VERSION 5.7 ;
BUSBITCHARS "[]" ;
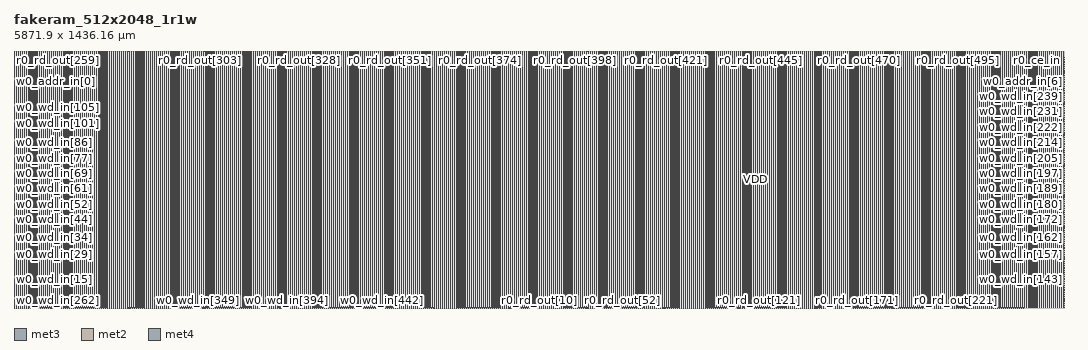
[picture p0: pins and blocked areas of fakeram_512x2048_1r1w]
MACRO fakeram_512x2048_1r1w
  FOREIGN fakeram_512x2048_1r1w 0 0 ;
  SYMMETRY X Y R90 ;
  SIZE 5871.900 BY 1436.160 ;
  CLASS BLOCK ;
  PIN w0_wd_in[0]
    DIRECTION INPUT ;
    USE SIGNAL ;
    SHAPE ABUTMENT ;
    PORT
      LAYER met3 ;
      RECT 0.000 3.930 0.900 4.230 ;
    END
  END w0_wd_in[0]
  PIN w0_wd_in[1]
    DIRECTION INPUT ;
    USE SIGNAL ;
    SHAPE ABUTMENT ;
    PORT
      LAYER met3 ;
      RECT 0.000 14.130 0.900 14.430 ;
    END
  END w0_wd_in[1]
  PIN w0_wd_in[2]
    DIRECTION INPUT ;
    USE SIGNAL ;
    SHAPE ABUTMENT ;
    PORT
      LAYER met3 ;
      RECT 0.000 24.330 0.900 24.630 ;
    END
  END w0_wd_in[2]
  PIN w0_wd_in[3]
    DIRECTION INPUT ;
    USE SIGNAL ;
    SHAPE ABUTMENT ;
    PORT
      LAYER met3 ;
      RECT 0.000 34.530 0.900 34.830 ;
    END
  END w0_wd_in[3]
  PIN w0_wd_in[4]
    DIRECTION INPUT ;
    USE SIGNAL ;
    SHAPE ABUTMENT ;
    PORT
      LAYER met3 ;
      RECT 0.000 44.730 0.900 45.030 ;
    END
  END w0_wd_in[4]
  PIN w0_wd_in[5]
    DIRECTION INPUT ;
    USE SIGNAL ;
    SHAPE ABUTMENT ;
    PORT
      LAYER met3 ;
      RECT 0.000 54.930 0.900 55.230 ;
    END
  END w0_wd_in[5]
  PIN w0_wd_in[6]
    DIRECTION INPUT ;
    USE SIGNAL ;
    SHAPE ABUTMENT ;
    PORT
      LAYER met3 ;
      RECT 0.000 65.130 0.900 65.430 ;
    END
  END w0_wd_in[6]
  PIN w0_wd_in[7]
    DIRECTION INPUT ;
    USE SIGNAL ;
    SHAPE ABUTMENT ;
    PORT
      LAYER met3 ;
      RECT 0.000 75.330 0.900 75.630 ;
    END
  END w0_wd_in[7]
  PIN w0_wd_in[8]
    DIRECTION INPUT ;
    USE SIGNAL ;
    SHAPE ABUTMENT ;
    PORT
      LAYER met3 ;
      RECT 0.000 85.530 0.900 85.830 ;
    END
  END w0_wd_in[8]
  PIN w0_wd_in[9]
    DIRECTION INPUT ;
    USE SIGNAL ;
    SHAPE ABUTMENT ;
    PORT
      LAYER met3 ;
      RECT 0.000 95.730 0.900 96.030 ;
    END
  END w0_wd_in[9]
  PIN w0_wd_in[10]
    DIRECTION INPUT ;
    USE SIGNAL ;
    SHAPE ABUTMENT ;
    PORT
      LAYER met3 ;
      RECT 0.000 105.930 0.900 106.230 ;
    END
  END w0_wd_in[10]
  PIN w0_wd_in[11]
    DIRECTION INPUT ;
    USE SIGNAL ;
    SHAPE ABUTMENT ;
    PORT
      LAYER met3 ;
      RECT 0.000 116.130 0.900 116.430 ;
    END
  END w0_wd_in[11]
  PIN w0_wd_in[12]
    DIRECTION INPUT ;
    USE SIGNAL ;
    SHAPE ABUTMENT ;
    PORT
      LAYER met3 ;
      RECT 0.000 126.330 0.900 126.630 ;
    END
  END w0_wd_in[12]
  PIN w0_wd_in[13]
    DIRECTION INPUT ;
    USE SIGNAL ;
    SHAPE ABUTMENT ;
    PORT
      LAYER met3 ;
      RECT 0.000 136.530 0.900 136.830 ;
    END
  END w0_wd_in[13]
  PIN w0_wd_in[14]
    DIRECTION INPUT ;
    USE SIGNAL ;
    SHAPE ABUTMENT ;
    PORT
      LAYER met3 ;
      RECT 0.000 146.730 0.900 147.030 ;
    END
  END w0_wd_in[14]
  PIN w0_wd_in[15]
    DIRECTION INPUT ;
    USE SIGNAL ;
    SHAPE ABUTMENT ;
    PORT
      LAYER met3 ;
      RECT 0.000 156.930 0.900 157.230 ;
    END
  END w0_wd_in[15]
  PIN w0_wd_in[16]
    DIRECTION INPUT ;
    USE SIGNAL ;
    SHAPE ABUTMENT ;
    PORT
      LAYER met3 ;
      RECT 0.000 167.130 0.900 167.430 ;
    END
  END w0_wd_in[16]
  PIN w0_wd_in[17]
    DIRECTION INPUT ;
    USE SIGNAL ;
    SHAPE ABUTMENT ;
    PORT
      LAYER met3 ;
      RECT 0.000 177.330 0.900 177.630 ;
    END
  END w0_wd_in[17]
  PIN w0_wd_in[18]
    DIRECTION INPUT ;
    USE SIGNAL ;
    SHAPE ABUTMENT ;
    PORT
      LAYER met3 ;
      RECT 0.000 187.530 0.900 187.830 ;
    END
  END w0_wd_in[18]
  PIN w0_wd_in[19]
    DIRECTION INPUT ;
    USE SIGNAL ;
    SHAPE ABUTMENT ;
    PORT
      LAYER met3 ;
      RECT 0.000 197.730 0.900 198.030 ;
    END
  END w0_wd_in[19]
  PIN w0_wd_in[20]
    DIRECTION INPUT ;
    USE SIGNAL ;
    SHAPE ABUTMENT ;
    PORT
      LAYER met3 ;
      RECT 0.000 207.930 0.900 208.230 ;
    END
  END w0_wd_in[20]
  PIN w0_wd_in[21]
    DIRECTION INPUT ;
    USE SIGNAL ;
    SHAPE ABUTMENT ;
    PORT
      LAYER met3 ;
      RECT 0.000 218.130 0.900 218.430 ;
    END
  END w0_wd_in[21]
  PIN w0_wd_in[22]
    DIRECTION INPUT ;
    USE SIGNAL ;
    SHAPE ABUTMENT ;
    PORT
      LAYER met3 ;
      RECT 0.000 228.330 0.900 228.630 ;
    END
  END w0_wd_in[22]
  PIN w0_wd_in[23]
    DIRECTION INPUT ;
    USE SIGNAL ;
    SHAPE ABUTMENT ;
    PORT
      LAYER met3 ;
      RECT 0.000 238.530 0.900 238.830 ;
    END
  END w0_wd_in[23]
  PIN w0_wd_in[24]
    DIRECTION INPUT ;
    USE SIGNAL ;
    SHAPE ABUTMENT ;
    PORT
      LAYER met3 ;
      RECT 0.000 248.730 0.900 249.030 ;
    END
  END w0_wd_in[24]
  PIN w0_wd_in[25]
    DIRECTION INPUT ;
    USE SIGNAL ;
    SHAPE ABUTMENT ;
    PORT
      LAYER met3 ;
      RECT 0.000 258.930 0.900 259.230 ;
    END
  END w0_wd_in[25]
  PIN w0_wd_in[26]
    DIRECTION INPUT ;
    USE SIGNAL ;
    SHAPE ABUTMENT ;
    PORT
      LAYER met3 ;
      RECT 0.000 269.130 0.900 269.430 ;
    END
  END w0_wd_in[26]
  PIN w0_wd_in[27]
    DIRECTION INPUT ;
    USE SIGNAL ;
    SHAPE ABUTMENT ;
    PORT
      LAYER met3 ;
      RECT 0.000 279.330 0.900 279.630 ;
    END
  END w0_wd_in[27]
  PIN w0_wd_in[28]
    DIRECTION INPUT ;
    USE SIGNAL ;
    SHAPE ABUTMENT ;
    PORT
      LAYER met3 ;
      RECT 0.000 289.530 0.900 289.830 ;
    END
  END w0_wd_in[28]
  PIN w0_wd_in[29]
    DIRECTION INPUT ;
    USE SIGNAL ;
    SHAPE ABUTMENT ;
    PORT
      LAYER met3 ;
      RECT 0.000 299.730 0.900 300.030 ;
    END
  END w0_wd_in[29]
  PIN w0_wd_in[30]
    DIRECTION INPUT ;
    USE SIGNAL ;
    SHAPE ABUTMENT ;
    PORT
      LAYER met3 ;
      RECT 0.000 309.930 0.900 310.230 ;
    END
  END w0_wd_in[30]
  PIN w0_wd_in[31]
    DIRECTION INPUT ;
    USE SIGNAL ;
    SHAPE ABUTMENT ;
    PORT
      LAYER met3 ;
      RECT 0.000 320.130 0.900 320.430 ;
    END
  END w0_wd_in[31]
  PIN w0_wd_in[32]
    DIRECTION INPUT ;
    USE SIGNAL ;
    SHAPE ABUTMENT ;
    PORT
      LAYER met3 ;
      RECT 0.000 330.330 0.900 330.630 ;
    END
  END w0_wd_in[32]
  PIN w0_wd_in[33]
    DIRECTION INPUT ;
    USE SIGNAL ;
    SHAPE ABUTMENT ;
    PORT
      LAYER met3 ;
      RECT 0.000 340.530 0.900 340.830 ;
    END
  END w0_wd_in[33]
  PIN w0_wd_in[34]
    DIRECTION INPUT ;
    USE SIGNAL ;
    SHAPE ABUTMENT ;
    PORT
      LAYER met3 ;
      RECT 0.000 350.730 0.900 351.030 ;
    END
  END w0_wd_in[34]
  PIN w0_wd_in[35]
    DIRECTION INPUT ;
    USE SIGNAL ;
    SHAPE ABUTMENT ;
    PORT
      LAYER met3 ;
      RECT 0.000 360.930 0.900 361.230 ;
    END
  END w0_wd_in[35]
  PIN w0_wd_in[36]
    DIRECTION INPUT ;
    USE SIGNAL ;
    SHAPE ABUTMENT ;
    PORT
      LAYER met3 ;
      RECT 0.000 371.130 0.900 371.430 ;
    END
  END w0_wd_in[36]
  PIN w0_wd_in[37]
    DIRECTION INPUT ;
    USE SIGNAL ;
    SHAPE ABUTMENT ;
    PORT
      LAYER met3 ;
      RECT 0.000 381.330 0.900 381.630 ;
    END
  END w0_wd_in[37]
  PIN w0_wd_in[38]
    DIRECTION INPUT ;
    USE SIGNAL ;
    SHAPE ABUTMENT ;
    PORT
      LAYER met3 ;
      RECT 0.000 391.530 0.900 391.830 ;
    END
  END w0_wd_in[38]
  PIN w0_wd_in[39]
    DIRECTION INPUT ;
    USE SIGNAL ;
    SHAPE ABUTMENT ;
    PORT
      LAYER met3 ;
      RECT 0.000 401.730 0.900 402.030 ;
    END
  END w0_wd_in[39]
  PIN w0_wd_in[40]
    DIRECTION INPUT ;
    USE SIGNAL ;
    SHAPE ABUTMENT ;
    PORT
      LAYER met3 ;
      RECT 0.000 411.930 0.900 412.230 ;
    END
  END w0_wd_in[40]
  PIN w0_wd_in[41]
    DIRECTION INPUT ;
    USE SIGNAL ;
    SHAPE ABUTMENT ;
    PORT
      LAYER met3 ;
      RECT 0.000 422.130 0.900 422.430 ;
    END
  END w0_wd_in[41]
  PIN w0_wd_in[42]
    DIRECTION INPUT ;
    USE SIGNAL ;
    SHAPE ABUTMENT ;
    PORT
      LAYER met3 ;
      RECT 0.000 432.330 0.900 432.630 ;
    END
  END w0_wd_in[42]
  PIN w0_wd_in[43]
    DIRECTION INPUT ;
    USE SIGNAL ;
    SHAPE ABUTMENT ;
    PORT
      LAYER met3 ;
      RECT 0.000 442.530 0.900 442.830 ;
    END
  END w0_wd_in[43]
  PIN w0_wd_in[44]
    DIRECTION INPUT ;
    USE SIGNAL ;
    SHAPE ABUTMENT ;
    PORT
      LAYER met3 ;
      RECT 0.000 452.730 0.900 453.030 ;
    END
  END w0_wd_in[44]
  PIN w0_wd_in[45]
    DIRECTION INPUT ;
    USE SIGNAL ;
    SHAPE ABUTMENT ;
    PORT
      LAYER met3 ;
      RECT 0.000 462.930 0.900 463.230 ;
    END
  END w0_wd_in[45]
  PIN w0_wd_in[46]
    DIRECTION INPUT ;
    USE SIGNAL ;
    SHAPE ABUTMENT ;
    PORT
      LAYER met3 ;
      RECT 0.000 473.130 0.900 473.430 ;
    END
  END w0_wd_in[46]
  PIN w0_wd_in[47]
    DIRECTION INPUT ;
    USE SIGNAL ;
    SHAPE ABUTMENT ;
    PORT
      LAYER met3 ;
      RECT 0.000 483.330 0.900 483.630 ;
    END
  END w0_wd_in[47]
  PIN w0_wd_in[48]
    DIRECTION INPUT ;
    USE SIGNAL ;
    SHAPE ABUTMENT ;
    PORT
      LAYER met3 ;
      RECT 0.000 493.530 0.900 493.830 ;
    END
  END w0_wd_in[48]
  PIN w0_wd_in[49]
    DIRECTION INPUT ;
    USE SIGNAL ;
    SHAPE ABUTMENT ;
    PORT
      LAYER met3 ;
      RECT 0.000 503.730 0.900 504.030 ;
    END
  END w0_wd_in[49]
  PIN w0_wd_in[50]
    DIRECTION INPUT ;
    USE SIGNAL ;
    SHAPE ABUTMENT ;
    PORT
      LAYER met3 ;
      RECT 0.000 513.930 0.900 514.230 ;
    END
  END w0_wd_in[50]
  PIN w0_wd_in[51]
    DIRECTION INPUT ;
    USE SIGNAL ;
    SHAPE ABUTMENT ;
    PORT
      LAYER met3 ;
      RECT 0.000 524.130 0.900 524.430 ;
    END
  END w0_wd_in[51]
  PIN w0_wd_in[52]
    DIRECTION INPUT ;
    USE SIGNAL ;
    SHAPE ABUTMENT ;
    PORT
      LAYER met3 ;
      RECT 0.000 534.330 0.900 534.630 ;
    END
  END w0_wd_in[52]
  PIN w0_wd_in[53]
    DIRECTION INPUT ;
    USE SIGNAL ;
    SHAPE ABUTMENT ;
    PORT
      LAYER met3 ;
      RECT 0.000 544.530 0.900 544.830 ;
    END
  END w0_wd_in[53]
  PIN w0_wd_in[54]
    DIRECTION INPUT ;
    USE SIGNAL ;
    SHAPE ABUTMENT ;
    PORT
      LAYER met3 ;
      RECT 0.000 554.730 0.900 555.030 ;
    END
  END w0_wd_in[54]
  PIN w0_wd_in[55]
    DIRECTION INPUT ;
    USE SIGNAL ;
    SHAPE ABUTMENT ;
    PORT
      LAYER met3 ;
      RECT 0.000 564.930 0.900 565.230 ;
    END
  END w0_wd_in[55]
  PIN w0_wd_in[56]
    DIRECTION INPUT ;
    USE SIGNAL ;
    SHAPE ABUTMENT ;
    PORT
      LAYER met3 ;
      RECT 0.000 575.130 0.900 575.430 ;
    END
  END w0_wd_in[56]
  PIN w0_wd_in[57]
    DIRECTION INPUT ;
    USE SIGNAL ;
    SHAPE ABUTMENT ;
    PORT
      LAYER met3 ;
      RECT 0.000 585.330 0.900 585.630 ;
    END
  END w0_wd_in[57]
  PIN w0_wd_in[58]
    DIRECTION INPUT ;
    USE SIGNAL ;
    SHAPE ABUTMENT ;
    PORT
      LAYER met3 ;
      RECT 0.000 595.530 0.900 595.830 ;
    END
  END w0_wd_in[58]
  PIN w0_wd_in[59]
    DIRECTION INPUT ;
    USE SIGNAL ;
    SHAPE ABUTMENT ;
    PORT
      LAYER met3 ;
      RECT 0.000 605.730 0.900 606.030 ;
    END
  END w0_wd_in[59]
  PIN w0_wd_in[60]
    DIRECTION INPUT ;
    USE SIGNAL ;
    SHAPE ABUTMENT ;
    PORT
      LAYER met3 ;
      RECT 0.000 615.930 0.900 616.230 ;
    END
  END w0_wd_in[60]
  PIN w0_wd_in[61]
    DIRECTION INPUT ;
    USE SIGNAL ;
    SHAPE ABUTMENT ;
    PORT
      LAYER met3 ;
      RECT 0.000 626.130 0.900 626.430 ;
    END
  END w0_wd_in[61]
  PIN w0_wd_in[62]
    DIRECTION INPUT ;
    USE SIGNAL ;
    SHAPE ABUTMENT ;
    PORT
      LAYER met3 ;
      RECT 0.000 636.330 0.900 636.630 ;
    END
  END w0_wd_in[62]
  PIN w0_wd_in[63]
    DIRECTION INPUT ;
    USE SIGNAL ;
    SHAPE ABUTMENT ;
    PORT
      LAYER met3 ;
      RECT 0.000 646.530 0.900 646.830 ;
    END
  END w0_wd_in[63]
  PIN w0_wd_in[64]
    DIRECTION INPUT ;
    USE SIGNAL ;
    SHAPE ABUTMENT ;
    PORT
      LAYER met3 ;
      RECT 0.000 656.730 0.900 657.030 ;
    END
  END w0_wd_in[64]
  PIN w0_wd_in[65]
    DIRECTION INPUT ;
    USE SIGNAL ;
    SHAPE ABUTMENT ;
    PORT
      LAYER met3 ;
      RECT 0.000 666.930 0.900 667.230 ;
    END
  END w0_wd_in[65]
  PIN w0_wd_in[66]
    DIRECTION INPUT ;
    USE SIGNAL ;
    SHAPE ABUTMENT ;
    PORT
      LAYER met3 ;
      RECT 0.000 677.130 0.900 677.430 ;
    END
  END w0_wd_in[66]
  PIN w0_wd_in[67]
    DIRECTION INPUT ;
    USE SIGNAL ;
    SHAPE ABUTMENT ;
    PORT
      LAYER met3 ;
      RECT 0.000 687.330 0.900 687.630 ;
    END
  END w0_wd_in[67]
  PIN w0_wd_in[68]
    DIRECTION INPUT ;
    USE SIGNAL ;
    SHAPE ABUTMENT ;
    PORT
      LAYER met3 ;
      RECT 0.000 697.530 0.900 697.830 ;
    END
  END w0_wd_in[68]
  PIN w0_wd_in[69]
    DIRECTION INPUT ;
    USE SIGNAL ;
    SHAPE ABUTMENT ;
    PORT
      LAYER met3 ;
      RECT 0.000 707.730 0.900 708.030 ;
    END
  END w0_wd_in[69]
  PIN w0_wd_in[70]
    DIRECTION INPUT ;
    USE SIGNAL ;
    SHAPE ABUTMENT ;
    PORT
      LAYER met3 ;
      RECT 0.000 717.930 0.900 718.230 ;
    END
  END w0_wd_in[70]
  PIN w0_wd_in[71]
    DIRECTION INPUT ;
    USE SIGNAL ;
    SHAPE ABUTMENT ;
    PORT
      LAYER met3 ;
      RECT 0.000 728.130 0.900 728.430 ;
    END
  END w0_wd_in[71]
  PIN w0_wd_in[72]
    DIRECTION INPUT ;
    USE SIGNAL ;
    SHAPE ABUTMENT ;
    PORT
      LAYER met3 ;
      RECT 0.000 738.330 0.900 738.630 ;
    END
  END w0_wd_in[72]
  PIN w0_wd_in[73]
    DIRECTION INPUT ;
    USE SIGNAL ;
    SHAPE ABUTMENT ;
    PORT
      LAYER met3 ;
      RECT 0.000 748.530 0.900 748.830 ;
    END
  END w0_wd_in[73]
  PIN w0_wd_in[74]
    DIRECTION INPUT ;
    USE SIGNAL ;
    SHAPE ABUTMENT ;
    PORT
      LAYER met3 ;
      RECT 0.000 758.730 0.900 759.030 ;
    END
  END w0_wd_in[74]
  PIN w0_wd_in[75]
    DIRECTION INPUT ;
    USE SIGNAL ;
    SHAPE ABUTMENT ;
    PORT
      LAYER met3 ;
      RECT 0.000 768.930 0.900 769.230 ;
    END
  END w0_wd_in[75]
  PIN w0_wd_in[76]
    DIRECTION INPUT ;
    USE SIGNAL ;
    SHAPE ABUTMENT ;
    PORT
      LAYER met3 ;
      RECT 0.000 779.130 0.900 779.430 ;
    END
  END w0_wd_in[76]
  PIN w0_wd_in[77]
    DIRECTION INPUT ;
    USE SIGNAL ;
    SHAPE ABUTMENT ;
    PORT
      LAYER met3 ;
      RECT 0.000 789.330 0.900 789.630 ;
    END
  END w0_wd_in[77]
  PIN w0_wd_in[78]
    DIRECTION INPUT ;
    USE SIGNAL ;
    SHAPE ABUTMENT ;
    PORT
      LAYER met3 ;
      RECT 0.000 799.530 0.900 799.830 ;
    END
  END w0_wd_in[78]
  PIN w0_wd_in[79]
    DIRECTION INPUT ;
    USE SIGNAL ;
    SHAPE ABUTMENT ;
    PORT
      LAYER met3 ;
      RECT 0.000 809.730 0.900 810.030 ;
    END
  END w0_wd_in[79]
  PIN w0_wd_in[80]
    DIRECTION INPUT ;
    USE SIGNAL ;
    SHAPE ABUTMENT ;
    PORT
      LAYER met3 ;
      RECT 0.000 819.930 0.900 820.230 ;
    END
  END w0_wd_in[80]
  PIN w0_wd_in[81]
    DIRECTION INPUT ;
    USE SIGNAL ;
    SHAPE ABUTMENT ;
    PORT
      LAYER met3 ;
      RECT 0.000 830.130 0.900 830.430 ;
    END
  END w0_wd_in[81]
  PIN w0_wd_in[82]
    DIRECTION INPUT ;
    USE SIGNAL ;
    SHAPE ABUTMENT ;
    PORT
      LAYER met3 ;
      RECT 0.000 840.330 0.900 840.630 ;
    END
  END w0_wd_in[82]
  PIN w0_wd_in[83]
    DIRECTION INPUT ;
    USE SIGNAL ;
    SHAPE ABUTMENT ;
    PORT
      LAYER met3 ;
      RECT 0.000 850.530 0.900 850.830 ;
    END
  END w0_wd_in[83]
  PIN w0_wd_in[84]
    DIRECTION INPUT ;
    USE SIGNAL ;
    SHAPE ABUTMENT ;
    PORT
      LAYER met3 ;
      RECT 0.000 860.730 0.900 861.030 ;
    END
  END w0_wd_in[84]
  PIN w0_wd_in[85]
    DIRECTION INPUT ;
    USE SIGNAL ;
    SHAPE ABUTMENT ;
    PORT
      LAYER met3 ;
      RECT 0.000 870.930 0.900 871.230 ;
    END
  END w0_wd_in[85]
  PIN w0_wd_in[86]
    DIRECTION INPUT ;
    USE SIGNAL ;
    SHAPE ABUTMENT ;
    PORT
      LAYER met3 ;
      RECT 0.000 881.130 0.900 881.430 ;
    END
  END w0_wd_in[86]
  PIN w0_wd_in[87]
    DIRECTION INPUT ;
    USE SIGNAL ;
    SHAPE ABUTMENT ;
    PORT
      LAYER met3 ;
      RECT 0.000 891.330 0.900 891.630 ;
    END
  END w0_wd_in[87]
  PIN w0_wd_in[88]
    DIRECTION INPUT ;
    USE SIGNAL ;
    SHAPE ABUTMENT ;
    PORT
      LAYER met3 ;
      RECT 0.000 901.530 0.900 901.830 ;
    END
  END w0_wd_in[88]
  PIN w0_wd_in[89]
    DIRECTION INPUT ;
    USE SIGNAL ;
    SHAPE ABUTMENT ;
    PORT
      LAYER met3 ;
      RECT 0.000 911.730 0.900 912.030 ;
    END
  END w0_wd_in[89]
  PIN w0_wd_in[90]
    DIRECTION INPUT ;
    USE SIGNAL ;
    SHAPE ABUTMENT ;
    PORT
      LAYER met3 ;
      RECT 0.000 921.930 0.900 922.230 ;
    END
  END w0_wd_in[90]
  PIN w0_wd_in[91]
    DIRECTION INPUT ;
    USE SIGNAL ;
    SHAPE ABUTMENT ;
    PORT
      LAYER met3 ;
      RECT 0.000 932.130 0.900 932.430 ;
    END
  END w0_wd_in[91]
  PIN w0_wd_in[92]
    DIRECTION INPUT ;
    USE SIGNAL ;
    SHAPE ABUTMENT ;
    PORT
      LAYER met3 ;
      RECT 0.000 942.330 0.900 942.630 ;
    END
  END w0_wd_in[92]
  PIN w0_wd_in[93]
    DIRECTION INPUT ;
    USE SIGNAL ;
    SHAPE ABUTMENT ;
    PORT
      LAYER met3 ;
      RECT 0.000 952.530 0.900 952.830 ;
    END
  END w0_wd_in[93]
  PIN w0_wd_in[94]
    DIRECTION INPUT ;
    USE SIGNAL ;
    SHAPE ABUTMENT ;
    PORT
      LAYER met3 ;
      RECT 0.000 962.730 0.900 963.030 ;
    END
  END w0_wd_in[94]
  PIN w0_wd_in[95]
    DIRECTION INPUT ;
    USE SIGNAL ;
    SHAPE ABUTMENT ;
    PORT
      LAYER met3 ;
      RECT 0.000 972.930 0.900 973.230 ;
    END
  END w0_wd_in[95]
  PIN w0_wd_in[96]
    DIRECTION INPUT ;
    USE SIGNAL ;
    SHAPE ABUTMENT ;
    PORT
      LAYER met3 ;
      RECT 0.000 983.130 0.900 983.430 ;
    END
  END w0_wd_in[96]
  PIN w0_wd_in[97]
    DIRECTION INPUT ;
    USE SIGNAL ;
    SHAPE ABUTMENT ;
    PORT
      LAYER met3 ;
      RECT 0.000 993.330 0.900 993.630 ;
    END
  END w0_wd_in[97]
  PIN w0_wd_in[98]
    DIRECTION INPUT ;
    USE SIGNAL ;
    SHAPE ABUTMENT ;
    PORT
      LAYER met3 ;
      RECT 0.000 1003.530 0.900 1003.830 ;
    END
  END w0_wd_in[98]
  PIN w0_wd_in[99]
    DIRECTION INPUT ;
    USE SIGNAL ;
    SHAPE ABUTMENT ;
    PORT
      LAYER met3 ;
      RECT 0.000 1013.730 0.900 1014.030 ;
    END
  END w0_wd_in[99]
  PIN w0_wd_in[100]
    DIRECTION INPUT ;
    USE SIGNAL ;
    SHAPE ABUTMENT ;
    PORT
      LAYER met3 ;
      RECT 0.000 1023.930 0.900 1024.230 ;
    END
  END w0_wd_in[100]
  PIN w0_wd_in[101]
    DIRECTION INPUT ;
    USE SIGNAL ;
    SHAPE ABUTMENT ;
    PORT
      LAYER met3 ;
      RECT 0.000 1034.130 0.900 1034.430 ;
    END
  END w0_wd_in[101]
  PIN w0_wd_in[102]
    DIRECTION INPUT ;
    USE SIGNAL ;
    SHAPE ABUTMENT ;
    PORT
      LAYER met3 ;
      RECT 0.000 1044.330 0.900 1044.630 ;
    END
  END w0_wd_in[102]
  PIN w0_wd_in[103]
    DIRECTION INPUT ;
    USE SIGNAL ;
    SHAPE ABUTMENT ;
    PORT
      LAYER met3 ;
      RECT 0.000 1054.530 0.900 1054.830 ;
    END
  END w0_wd_in[103]
  PIN w0_wd_in[104]
    DIRECTION INPUT ;
    USE SIGNAL ;
    SHAPE ABUTMENT ;
    PORT
      LAYER met3 ;
      RECT 0.000 1064.730 0.900 1065.030 ;
    END
  END w0_wd_in[104]
  PIN w0_wd_in[105]
    DIRECTION INPUT ;
    USE SIGNAL ;
    SHAPE ABUTMENT ;
    PORT
      LAYER met3 ;
      RECT 0.000 1074.930 0.900 1075.230 ;
    END
  END w0_wd_in[105]
  PIN w0_wd_in[106]
    DIRECTION INPUT ;
    USE SIGNAL ;
    SHAPE ABUTMENT ;
    PORT
      LAYER met3 ;
      RECT 0.000 1085.130 0.900 1085.430 ;
    END
  END w0_wd_in[106]
  PIN w0_wd_in[107]
    DIRECTION INPUT ;
    USE SIGNAL ;
    SHAPE ABUTMENT ;
    PORT
      LAYER met3 ;
      RECT 0.000 1095.330 0.900 1095.630 ;
    END
  END w0_wd_in[107]
  PIN w0_wd_in[108]
    DIRECTION INPUT ;
    USE SIGNAL ;
    SHAPE ABUTMENT ;
    PORT
      LAYER met3 ;
      RECT 0.000 1105.530 0.900 1105.830 ;
    END
  END w0_wd_in[108]
  PIN w0_wd_in[109]
    DIRECTION INPUT ;
    USE SIGNAL ;
    SHAPE ABUTMENT ;
    PORT
      LAYER met3 ;
      RECT 0.000 1115.730 0.900 1116.030 ;
    END
  END w0_wd_in[109]
  PIN w0_wd_in[110]
    DIRECTION INPUT ;
    USE SIGNAL ;
    SHAPE ABUTMENT ;
    PORT
      LAYER met3 ;
      RECT 0.000 1125.930 0.900 1126.230 ;
    END
  END w0_wd_in[110]
  PIN w0_wd_in[111]
    DIRECTION INPUT ;
    USE SIGNAL ;
    SHAPE ABUTMENT ;
    PORT
      LAYER met3 ;
      RECT 0.000 1136.130 0.900 1136.430 ;
    END
  END w0_wd_in[111]
  PIN w0_wd_in[112]
    DIRECTION INPUT ;
    USE SIGNAL ;
    SHAPE ABUTMENT ;
    PORT
      LAYER met3 ;
      RECT 0.000 1146.330 0.900 1146.630 ;
    END
  END w0_wd_in[112]
  PIN w0_wd_in[113]
    DIRECTION INPUT ;
    USE SIGNAL ;
    SHAPE ABUTMENT ;
    PORT
      LAYER met3 ;
      RECT 0.000 1156.530 0.900 1156.830 ;
    END
  END w0_wd_in[113]
  PIN w0_wd_in[114]
    DIRECTION INPUT ;
    USE SIGNAL ;
    SHAPE ABUTMENT ;
    PORT
      LAYER met3 ;
      RECT 0.000 1166.730 0.900 1167.030 ;
    END
  END w0_wd_in[114]
  PIN w0_wd_in[115]
    DIRECTION INPUT ;
    USE SIGNAL ;
    SHAPE ABUTMENT ;
    PORT
      LAYER met3 ;
      RECT 0.000 1176.930 0.900 1177.230 ;
    END
  END w0_wd_in[115]
  PIN w0_wd_in[116]
    DIRECTION INPUT ;
    USE SIGNAL ;
    SHAPE ABUTMENT ;
    PORT
      LAYER met3 ;
      RECT 0.000 1187.130 0.900 1187.430 ;
    END
  END w0_wd_in[116]
  PIN w0_wd_in[117]
    DIRECTION INPUT ;
    USE SIGNAL ;
    SHAPE ABUTMENT ;
    PORT
      LAYER met3 ;
      RECT 0.000 1197.330 0.900 1197.630 ;
    END
  END w0_wd_in[117]
  PIN w0_wd_in[118]
    DIRECTION INPUT ;
    USE SIGNAL ;
    SHAPE ABUTMENT ;
    PORT
      LAYER met3 ;
      RECT 0.000 1207.530 0.900 1207.830 ;
    END
  END w0_wd_in[118]
  PIN w0_wd_in[119]
    DIRECTION INPUT ;
    USE SIGNAL ;
    SHAPE ABUTMENT ;
    PORT
      LAYER met3 ;
      RECT 0.000 1217.730 0.900 1218.030 ;
    END
  END w0_wd_in[119]
  PIN w0_wd_in[120]
    DIRECTION INPUT ;
    USE SIGNAL ;
    SHAPE ABUTMENT ;
    PORT
      LAYER met3 ;
      RECT 0.000 1227.930 0.900 1228.230 ;
    END
  END w0_wd_in[120]
  PIN w0_wd_in[121]
    DIRECTION INPUT ;
    USE SIGNAL ;
    SHAPE ABUTMENT ;
    PORT
      LAYER met3 ;
      RECT 0.000 1238.130 0.900 1238.430 ;
    END
  END w0_wd_in[121]
  PIN w0_wd_in[122]
    DIRECTION INPUT ;
    USE SIGNAL ;
    SHAPE ABUTMENT ;
    PORT
      LAYER met3 ;
      RECT 0.000 1248.330 0.900 1248.630 ;
    END
  END w0_wd_in[122]
  PIN w0_wd_in[123]
    DIRECTION INPUT ;
    USE SIGNAL ;
    SHAPE ABUTMENT ;
    PORT
      LAYER met3 ;
      RECT 0.000 1258.530 0.900 1258.830 ;
    END
  END w0_wd_in[123]
  PIN w0_wd_in[124]
    DIRECTION INPUT ;
    USE SIGNAL ;
    SHAPE ABUTMENT ;
    PORT
      LAYER met3 ;
      RECT 0.000 1268.730 0.900 1269.030 ;
    END
  END w0_wd_in[124]
  PIN w0_wd_in[125]
    DIRECTION INPUT ;
    USE SIGNAL ;
    SHAPE ABUTMENT ;
    PORT
      LAYER met3 ;
      RECT 0.000 1278.930 0.900 1279.230 ;
    END
  END w0_wd_in[125]
  PIN w0_wd_in[126]
    DIRECTION INPUT ;
    USE SIGNAL ;
    SHAPE ABUTMENT ;
    PORT
      LAYER met3 ;
      RECT 0.000 1289.130 0.900 1289.430 ;
    END
  END w0_wd_in[126]
  PIN w0_wd_in[127]
    DIRECTION INPUT ;
    USE SIGNAL ;
    SHAPE ABUTMENT ;
    PORT
      LAYER met3 ;
      RECT 0.000 1299.330 0.900 1299.630 ;
    END
  END w0_wd_in[127]
  PIN w0_wd_in[128]
    DIRECTION INPUT ;
    USE SIGNAL ;
    SHAPE ABUTMENT ;
    PORT
      LAYER met3 ;
      RECT 5871.000 3.930 5871.900 4.230 ;
    END
  END w0_wd_in[128]
  PIN w0_wd_in[129]
    DIRECTION INPUT ;
    USE SIGNAL ;
    SHAPE ABUTMENT ;
    PORT
      LAYER met3 ;
      RECT 5871.000 14.130 5871.900 14.430 ;
    END
  END w0_wd_in[129]
  PIN w0_wd_in[130]
    DIRECTION INPUT ;
    USE SIGNAL ;
    SHAPE ABUTMENT ;
    PORT
      LAYER met3 ;
      RECT 5871.000 24.330 5871.900 24.630 ;
    END
  END w0_wd_in[130]
  PIN w0_wd_in[131]
    DIRECTION INPUT ;
    USE SIGNAL ;
    SHAPE ABUTMENT ;
    PORT
      LAYER met3 ;
      RECT 5871.000 34.530 5871.900 34.830 ;
    END
  END w0_wd_in[131]
  PIN w0_wd_in[132]
    DIRECTION INPUT ;
    USE SIGNAL ;
    SHAPE ABUTMENT ;
    PORT
      LAYER met3 ;
      RECT 5871.000 44.730 5871.900 45.030 ;
    END
  END w0_wd_in[132]
  PIN w0_wd_in[133]
    DIRECTION INPUT ;
    USE SIGNAL ;
    SHAPE ABUTMENT ;
    PORT
      LAYER met3 ;
      RECT 5871.000 54.930 5871.900 55.230 ;
    END
  END w0_wd_in[133]
  PIN w0_wd_in[134]
    DIRECTION INPUT ;
    USE SIGNAL ;
    SHAPE ABUTMENT ;
    PORT
      LAYER met3 ;
      RECT 5871.000 65.130 5871.900 65.430 ;
    END
  END w0_wd_in[134]
  PIN w0_wd_in[135]
    DIRECTION INPUT ;
    USE SIGNAL ;
    SHAPE ABUTMENT ;
    PORT
      LAYER met3 ;
      RECT 5871.000 75.330 5871.900 75.630 ;
    END
  END w0_wd_in[135]
  PIN w0_wd_in[136]
    DIRECTION INPUT ;
    USE SIGNAL ;
    SHAPE ABUTMENT ;
    PORT
      LAYER met3 ;
      RECT 5871.000 85.530 5871.900 85.830 ;
    END
  END w0_wd_in[136]
  PIN w0_wd_in[137]
    DIRECTION INPUT ;
    USE SIGNAL ;
    SHAPE ABUTMENT ;
    PORT
      LAYER met3 ;
      RECT 5871.000 95.730 5871.900 96.030 ;
    END
  END w0_wd_in[137]
  PIN w0_wd_in[138]
    DIRECTION INPUT ;
    USE SIGNAL ;
    SHAPE ABUTMENT ;
    PORT
      LAYER met3 ;
      RECT 5871.000 105.930 5871.900 106.230 ;
    END
  END w0_wd_in[138]
  PIN w0_wd_in[139]
    DIRECTION INPUT ;
    USE SIGNAL ;
    SHAPE ABUTMENT ;
    PORT
      LAYER met3 ;
      RECT 5871.000 116.130 5871.900 116.430 ;
    END
  END w0_wd_in[139]
  PIN w0_wd_in[140]
    DIRECTION INPUT ;
    USE SIGNAL ;
    SHAPE ABUTMENT ;
    PORT
      LAYER met3 ;
      RECT 5871.000 126.330 5871.900 126.630 ;
    END
  END w0_wd_in[140]
  PIN w0_wd_in[141]
    DIRECTION INPUT ;
    USE SIGNAL ;
    SHAPE ABUTMENT ;
    PORT
      LAYER met3 ;
      RECT 5871.000 136.530 5871.900 136.830 ;
    END
  END w0_wd_in[141]
  PIN w0_wd_in[142]
    DIRECTION INPUT ;
    USE SIGNAL ;
    SHAPE ABUTMENT ;
    PORT
      LAYER met3 ;
      RECT 5871.000 146.730 5871.900 147.030 ;
    END
  END w0_wd_in[142]
  PIN w0_wd_in[143]
    DIRECTION INPUT ;
    USE SIGNAL ;
    SHAPE ABUTMENT ;
    PORT
      LAYER met3 ;
      RECT 5871.000 156.930 5871.900 157.230 ;
    END
  END w0_wd_in[143]
  PIN w0_wd_in[144]
    DIRECTION INPUT ;
    USE SIGNAL ;
    SHAPE ABUTMENT ;
    PORT
      LAYER met3 ;
      RECT 5871.000 167.130 5871.900 167.430 ;
    END
  END w0_wd_in[144]
  PIN w0_wd_in[145]
    DIRECTION INPUT ;
    USE SIGNAL ;
    SHAPE ABUTMENT ;
    PORT
      LAYER met3 ;
      RECT 5871.000 177.330 5871.900 177.630 ;
    END
  END w0_wd_in[145]
  PIN w0_wd_in[146]
    DIRECTION INPUT ;
    USE SIGNAL ;
    SHAPE ABUTMENT ;
    PORT
      LAYER met3 ;
      RECT 5871.000 187.530 5871.900 187.830 ;
    END
  END w0_wd_in[146]
  PIN w0_wd_in[147]
    DIRECTION INPUT ;
    USE SIGNAL ;
    SHAPE ABUTMENT ;
    PORT
      LAYER met3 ;
      RECT 5871.000 197.730 5871.900 198.030 ;
    END
  END w0_wd_in[147]
  PIN w0_wd_in[148]
    DIRECTION INPUT ;
    USE SIGNAL ;
    SHAPE ABUTMENT ;
    PORT
      LAYER met3 ;
      RECT 5871.000 207.930 5871.900 208.230 ;
    END
  END w0_wd_in[148]
  PIN w0_wd_in[149]
    DIRECTION INPUT ;
    USE SIGNAL ;
    SHAPE ABUTMENT ;
    PORT
      LAYER met3 ;
      RECT 5871.000 218.130 5871.900 218.430 ;
    END
  END w0_wd_in[149]
  PIN w0_wd_in[150]
    DIRECTION INPUT ;
    USE SIGNAL ;
    SHAPE ABUTMENT ;
    PORT
      LAYER met3 ;
      RECT 5871.000 228.330 5871.900 228.630 ;
    END
  END w0_wd_in[150]
  PIN w0_wd_in[151]
    DIRECTION INPUT ;
    USE SIGNAL ;
    SHAPE ABUTMENT ;
    PORT
      LAYER met3 ;
      RECT 5871.000 238.530 5871.900 238.830 ;
    END
  END w0_wd_in[151]
  PIN w0_wd_in[152]
    DIRECTION INPUT ;
    USE SIGNAL ;
    SHAPE ABUTMENT ;
    PORT
      LAYER met3 ;
      RECT 5871.000 248.730 5871.900 249.030 ;
    END
  END w0_wd_in[152]
  PIN w0_wd_in[153]
    DIRECTION INPUT ;
    USE SIGNAL ;
    SHAPE ABUTMENT ;
    PORT
      LAYER met3 ;
      RECT 5871.000 258.930 5871.900 259.230 ;
    END
  END w0_wd_in[153]
  PIN w0_wd_in[154]
    DIRECTION INPUT ;
    USE SIGNAL ;
    SHAPE ABUTMENT ;
    PORT
      LAYER met3 ;
      RECT 5871.000 269.130 5871.900 269.430 ;
    END
  END w0_wd_in[154]
  PIN w0_wd_in[155]
    DIRECTION INPUT ;
    USE SIGNAL ;
    SHAPE ABUTMENT ;
    PORT
      LAYER met3 ;
      RECT 5871.000 279.330 5871.900 279.630 ;
    END
  END w0_wd_in[155]
  PIN w0_wd_in[156]
    DIRECTION INPUT ;
    USE SIGNAL ;
    SHAPE ABUTMENT ;
    PORT
      LAYER met3 ;
      RECT 5871.000 289.530 5871.900 289.830 ;
    END
  END w0_wd_in[156]
  PIN w0_wd_in[157]
    DIRECTION INPUT ;
    USE SIGNAL ;
    SHAPE ABUTMENT ;
    PORT
      LAYER met3 ;
      RECT 5871.000 299.730 5871.900 300.030 ;
    END
  END w0_wd_in[157]
  PIN w0_wd_in[158]
    DIRECTION INPUT ;
    USE SIGNAL ;
    SHAPE ABUTMENT ;
    PORT
      LAYER met3 ;
      RECT 5871.000 309.930 5871.900 310.230 ;
    END
  END w0_wd_in[158]
  PIN w0_wd_in[159]
    DIRECTION INPUT ;
    USE SIGNAL ;
    SHAPE ABUTMENT ;
    PORT
      LAYER met3 ;
      RECT 5871.000 320.130 5871.900 320.430 ;
    END
  END w0_wd_in[159]
  PIN w0_wd_in[160]
    DIRECTION INPUT ;
    USE SIGNAL ;
    SHAPE ABUTMENT ;
    PORT
      LAYER met3 ;
      RECT 5871.000 330.330 5871.900 330.630 ;
    END
  END w0_wd_in[160]
  PIN w0_wd_in[161]
    DIRECTION INPUT ;
    USE SIGNAL ;
    SHAPE ABUTMENT ;
    PORT
      LAYER met3 ;
      RECT 5871.000 340.530 5871.900 340.830 ;
    END
  END w0_wd_in[161]
  PIN w0_wd_in[162]
    DIRECTION INPUT ;
    USE SIGNAL ;
    SHAPE ABUTMENT ;
    PORT
      LAYER met3 ;
      RECT 5871.000 350.730 5871.900 351.030 ;
    END
  END w0_wd_in[162]
  PIN w0_wd_in[163]
    DIRECTION INPUT ;
    USE SIGNAL ;
    SHAPE ABUTMENT ;
    PORT
      LAYER met3 ;
      RECT 5871.000 360.930 5871.900 361.230 ;
    END
  END w0_wd_in[163]
  PIN w0_wd_in[164]
    DIRECTION INPUT ;
    USE SIGNAL ;
    SHAPE ABUTMENT ;
    PORT
      LAYER met3 ;
      RECT 5871.000 371.130 5871.900 371.430 ;
    END
  END w0_wd_in[164]
  PIN w0_wd_in[165]
    DIRECTION INPUT ;
    USE SIGNAL ;
    SHAPE ABUTMENT ;
    PORT
      LAYER met3 ;
      RECT 5871.000 381.330 5871.900 381.630 ;
    END
  END w0_wd_in[165]
  PIN w0_wd_in[166]
    DIRECTION INPUT ;
    USE SIGNAL ;
    SHAPE ABUTMENT ;
    PORT
      LAYER met3 ;
      RECT 5871.000 391.530 5871.900 391.830 ;
    END
  END w0_wd_in[166]
  PIN w0_wd_in[167]
    DIRECTION INPUT ;
    USE SIGNAL ;
    SHAPE ABUTMENT ;
    PORT
      LAYER met3 ;
      RECT 5871.000 401.730 5871.900 402.030 ;
    END
  END w0_wd_in[167]
  PIN w0_wd_in[168]
    DIRECTION INPUT ;
    USE SIGNAL ;
    SHAPE ABUTMENT ;
    PORT
      LAYER met3 ;
      RECT 5871.000 411.930 5871.900 412.230 ;
    END
  END w0_wd_in[168]
  PIN w0_wd_in[169]
    DIRECTION INPUT ;
    USE SIGNAL ;
    SHAPE ABUTMENT ;
    PORT
      LAYER met3 ;
      RECT 5871.000 422.130 5871.900 422.430 ;
    END
  END w0_wd_in[169]
  PIN w0_wd_in[170]
    DIRECTION INPUT ;
    USE SIGNAL ;
    SHAPE ABUTMENT ;
    PORT
      LAYER met3 ;
      RECT 5871.000 432.330 5871.900 432.630 ;
    END
  END w0_wd_in[170]
  PIN w0_wd_in[171]
    DIRECTION INPUT ;
    USE SIGNAL ;
    SHAPE ABUTMENT ;
    PORT
      LAYER met3 ;
      RECT 5871.000 442.530 5871.900 442.830 ;
    END
  END w0_wd_in[171]
  PIN w0_wd_in[172]
    DIRECTION INPUT ;
    USE SIGNAL ;
    SHAPE ABUTMENT ;
    PORT
      LAYER met3 ;
      RECT 5871.000 452.730 5871.900 453.030 ;
    END
  END w0_wd_in[172]
  PIN w0_wd_in[173]
    DIRECTION INPUT ;
    USE SIGNAL ;
    SHAPE ABUTMENT ;
    PORT
      LAYER met3 ;
      RECT 5871.000 462.930 5871.900 463.230 ;
    END
  END w0_wd_in[173]
  PIN w0_wd_in[174]
    DIRECTION INPUT ;
    USE SIGNAL ;
    SHAPE ABUTMENT ;
    PORT
      LAYER met3 ;
      RECT 5871.000 473.130 5871.900 473.430 ;
    END
  END w0_wd_in[174]
  PIN w0_wd_in[175]
    DIRECTION INPUT ;
    USE SIGNAL ;
    SHAPE ABUTMENT ;
    PORT
      LAYER met3 ;
      RECT 5871.000 483.330 5871.900 483.630 ;
    END
  END w0_wd_in[175]
  PIN w0_wd_in[176]
    DIRECTION INPUT ;
    USE SIGNAL ;
    SHAPE ABUTMENT ;
    PORT
      LAYER met3 ;
      RECT 5871.000 493.530 5871.900 493.830 ;
    END
  END w0_wd_in[176]
  PIN w0_wd_in[177]
    DIRECTION INPUT ;
    USE SIGNAL ;
    SHAPE ABUTMENT ;
    PORT
      LAYER met3 ;
      RECT 5871.000 503.730 5871.900 504.030 ;
    END
  END w0_wd_in[177]
  PIN w0_wd_in[178]
    DIRECTION INPUT ;
    USE SIGNAL ;
    SHAPE ABUTMENT ;
    PORT
      LAYER met3 ;
      RECT 5871.000 513.930 5871.900 514.230 ;
    END
  END w0_wd_in[178]
  PIN w0_wd_in[179]
    DIRECTION INPUT ;
    USE SIGNAL ;
    SHAPE ABUTMENT ;
    PORT
      LAYER met3 ;
      RECT 5871.000 524.130 5871.900 524.430 ;
    END
  END w0_wd_in[179]
  PIN w0_wd_in[180]
    DIRECTION INPUT ;
    USE SIGNAL ;
    SHAPE ABUTMENT ;
    PORT
      LAYER met3 ;
      RECT 5871.000 534.330 5871.900 534.630 ;
    END
  END w0_wd_in[180]
  PIN w0_wd_in[181]
    DIRECTION INPUT ;
    USE SIGNAL ;
    SHAPE ABUTMENT ;
    PORT
      LAYER met3 ;
      RECT 5871.000 544.530 5871.900 544.830 ;
    END
  END w0_wd_in[181]
  PIN w0_wd_in[182]
    DIRECTION INPUT ;
    USE SIGNAL ;
    SHAPE ABUTMENT ;
    PORT
      LAYER met3 ;
      RECT 5871.000 554.730 5871.900 555.030 ;
    END
  END w0_wd_in[182]
  PIN w0_wd_in[183]
    DIRECTION INPUT ;
    USE SIGNAL ;
    SHAPE ABUTMENT ;
    PORT
      LAYER met3 ;
      RECT 5871.000 564.930 5871.900 565.230 ;
    END
  END w0_wd_in[183]
  PIN w0_wd_in[184]
    DIRECTION INPUT ;
    USE SIGNAL ;
    SHAPE ABUTMENT ;
    PORT
      LAYER met3 ;
      RECT 5871.000 575.130 5871.900 575.430 ;
    END
  END w0_wd_in[184]
  PIN w0_wd_in[185]
    DIRECTION INPUT ;
    USE SIGNAL ;
    SHAPE ABUTMENT ;
    PORT
      LAYER met3 ;
      RECT 5871.000 585.330 5871.900 585.630 ;
    END
  END w0_wd_in[185]
  PIN w0_wd_in[186]
    DIRECTION INPUT ;
    USE SIGNAL ;
    SHAPE ABUTMENT ;
    PORT
      LAYER met3 ;
      RECT 5871.000 595.530 5871.900 595.830 ;
    END
  END w0_wd_in[186]
  PIN w0_wd_in[187]
    DIRECTION INPUT ;
    USE SIGNAL ;
    SHAPE ABUTMENT ;
    PORT
      LAYER met3 ;
      RECT 5871.000 605.730 5871.900 606.030 ;
    END
  END w0_wd_in[187]
  PIN w0_wd_in[188]
    DIRECTION INPUT ;
    USE SIGNAL ;
    SHAPE ABUTMENT ;
    PORT
      LAYER met3 ;
      RECT 5871.000 615.930 5871.900 616.230 ;
    END
  END w0_wd_in[188]
  PIN w0_wd_in[189]
    DIRECTION INPUT ;
    USE SIGNAL ;
    SHAPE ABUTMENT ;
    PORT
      LAYER met3 ;
      RECT 5871.000 626.130 5871.900 626.430 ;
    END
  END w0_wd_in[189]
  PIN w0_wd_in[190]
    DIRECTION INPUT ;
    USE SIGNAL ;
    SHAPE ABUTMENT ;
    PORT
      LAYER met3 ;
      RECT 5871.000 636.330 5871.900 636.630 ;
    END
  END w0_wd_in[190]
  PIN w0_wd_in[191]
    DIRECTION INPUT ;
    USE SIGNAL ;
    SHAPE ABUTMENT ;
    PORT
      LAYER met3 ;
      RECT 5871.000 646.530 5871.900 646.830 ;
    END
  END w0_wd_in[191]
  PIN w0_wd_in[192]
    DIRECTION INPUT ;
    USE SIGNAL ;
    SHAPE ABUTMENT ;
    PORT
      LAYER met3 ;
      RECT 5871.000 656.730 5871.900 657.030 ;
    END
  END w0_wd_in[192]
  PIN w0_wd_in[193]
    DIRECTION INPUT ;
    USE SIGNAL ;
    SHAPE ABUTMENT ;
    PORT
      LAYER met3 ;
      RECT 5871.000 666.930 5871.900 667.230 ;
    END
  END w0_wd_in[193]
  PIN w0_wd_in[194]
    DIRECTION INPUT ;
    USE SIGNAL ;
    SHAPE ABUTMENT ;
    PORT
      LAYER met3 ;
      RECT 5871.000 677.130 5871.900 677.430 ;
    END
  END w0_wd_in[194]
  PIN w0_wd_in[195]
    DIRECTION INPUT ;
    USE SIGNAL ;
    SHAPE ABUTMENT ;
    PORT
      LAYER met3 ;
      RECT 5871.000 687.330 5871.900 687.630 ;
    END
  END w0_wd_in[195]
  PIN w0_wd_in[196]
    DIRECTION INPUT ;
    USE SIGNAL ;
    SHAPE ABUTMENT ;
    PORT
      LAYER met3 ;
      RECT 5871.000 697.530 5871.900 697.830 ;
    END
  END w0_wd_in[196]
  PIN w0_wd_in[197]
    DIRECTION INPUT ;
    USE SIGNAL ;
    SHAPE ABUTMENT ;
    PORT
      LAYER met3 ;
      RECT 5871.000 707.730 5871.900 708.030 ;
    END
  END w0_wd_in[197]
  PIN w0_wd_in[198]
    DIRECTION INPUT ;
    USE SIGNAL ;
    SHAPE ABUTMENT ;
    PORT
      LAYER met3 ;
      RECT 5871.000 717.930 5871.900 718.230 ;
    END
  END w0_wd_in[198]
  PIN w0_wd_in[199]
    DIRECTION INPUT ;
    USE SIGNAL ;
    SHAPE ABUTMENT ;
    PORT
      LAYER met3 ;
      RECT 5871.000 728.130 5871.900 728.430 ;
    END
  END w0_wd_in[199]
  PIN w0_wd_in[200]
    DIRECTION INPUT ;
    USE SIGNAL ;
    SHAPE ABUTMENT ;
    PORT
      LAYER met3 ;
      RECT 5871.000 738.330 5871.900 738.630 ;
    END
  END w0_wd_in[200]
  PIN w0_wd_in[201]
    DIRECTION INPUT ;
    USE SIGNAL ;
    SHAPE ABUTMENT ;
    PORT
      LAYER met3 ;
      RECT 5871.000 748.530 5871.900 748.830 ;
    END
  END w0_wd_in[201]
  PIN w0_wd_in[202]
    DIRECTION INPUT ;
    USE SIGNAL ;
    SHAPE ABUTMENT ;
    PORT
      LAYER met3 ;
      RECT 5871.000 758.730 5871.900 759.030 ;
    END
  END w0_wd_in[202]
  PIN w0_wd_in[203]
    DIRECTION INPUT ;
    USE SIGNAL ;
    SHAPE ABUTMENT ;
    PORT
      LAYER met3 ;
      RECT 5871.000 768.930 5871.900 769.230 ;
    END
  END w0_wd_in[203]
  PIN w0_wd_in[204]
    DIRECTION INPUT ;
    USE SIGNAL ;
    SHAPE ABUTMENT ;
    PORT
      LAYER met3 ;
      RECT 5871.000 779.130 5871.900 779.430 ;
    END
  END w0_wd_in[204]
  PIN w0_wd_in[205]
    DIRECTION INPUT ;
    USE SIGNAL ;
    SHAPE ABUTMENT ;
    PORT
      LAYER met3 ;
      RECT 5871.000 789.330 5871.900 789.630 ;
    END
  END w0_wd_in[205]
  PIN w0_wd_in[206]
    DIRECTION INPUT ;
    USE SIGNAL ;
    SHAPE ABUTMENT ;
    PORT
      LAYER met3 ;
      RECT 5871.000 799.530 5871.900 799.830 ;
    END
  END w0_wd_in[206]
  PIN w0_wd_in[207]
    DIRECTION INPUT ;
    USE SIGNAL ;
    SHAPE ABUTMENT ;
    PORT
      LAYER met3 ;
      RECT 5871.000 809.730 5871.900 810.030 ;
    END
  END w0_wd_in[207]
  PIN w0_wd_in[208]
    DIRECTION INPUT ;
    USE SIGNAL ;
    SHAPE ABUTMENT ;
    PORT
      LAYER met3 ;
      RECT 5871.000 819.930 5871.900 820.230 ;
    END
  END w0_wd_in[208]
  PIN w0_wd_in[209]
    DIRECTION INPUT ;
    USE SIGNAL ;
    SHAPE ABUTMENT ;
    PORT
      LAYER met3 ;
      RECT 5871.000 830.130 5871.900 830.430 ;
    END
  END w0_wd_in[209]
  PIN w0_wd_in[210]
    DIRECTION INPUT ;
    USE SIGNAL ;
    SHAPE ABUTMENT ;
    PORT
      LAYER met3 ;
      RECT 5871.000 840.330 5871.900 840.630 ;
    END
  END w0_wd_in[210]
  PIN w0_wd_in[211]
    DIRECTION INPUT ;
    USE SIGNAL ;
    SHAPE ABUTMENT ;
    PORT
      LAYER met3 ;
      RECT 5871.000 850.530 5871.900 850.830 ;
    END
  END w0_wd_in[211]
  PIN w0_wd_in[212]
    DIRECTION INPUT ;
    USE SIGNAL ;
    SHAPE ABUTMENT ;
    PORT
      LAYER met3 ;
      RECT 5871.000 860.730 5871.900 861.030 ;
    END
  END w0_wd_in[212]
  PIN w0_wd_in[213]
    DIRECTION INPUT ;
    USE SIGNAL ;
    SHAPE ABUTMENT ;
    PORT
      LAYER met3 ;
      RECT 5871.000 870.930 5871.900 871.230 ;
    END
  END w0_wd_in[213]
  PIN w0_wd_in[214]
    DIRECTION INPUT ;
    USE SIGNAL ;
    SHAPE ABUTMENT ;
    PORT
      LAYER met3 ;
      RECT 5871.000 881.130 5871.900 881.430 ;
    END
  END w0_wd_in[214]
  PIN w0_wd_in[215]
    DIRECTION INPUT ;
    USE SIGNAL ;
    SHAPE ABUTMENT ;
    PORT
      LAYER met3 ;
      RECT 5871.000 891.330 5871.900 891.630 ;
    END
  END w0_wd_in[215]
  PIN w0_wd_in[216]
    DIRECTION INPUT ;
    USE SIGNAL ;
    SHAPE ABUTMENT ;
    PORT
      LAYER met3 ;
      RECT 5871.000 901.530 5871.900 901.830 ;
    END
  END w0_wd_in[216]
  PIN w0_wd_in[217]
    DIRECTION INPUT ;
    USE SIGNAL ;
    SHAPE ABUTMENT ;
    PORT
      LAYER met3 ;
      RECT 5871.000 911.730 5871.900 912.030 ;
    END
  END w0_wd_in[217]
  PIN w0_wd_in[218]
    DIRECTION INPUT ;
    USE SIGNAL ;
    SHAPE ABUTMENT ;
    PORT
      LAYER met3 ;
      RECT 5871.000 921.930 5871.900 922.230 ;
    END
  END w0_wd_in[218]
  PIN w0_wd_in[219]
    DIRECTION INPUT ;
    USE SIGNAL ;
    SHAPE ABUTMENT ;
    PORT
      LAYER met3 ;
      RECT 5871.000 932.130 5871.900 932.430 ;
    END
  END w0_wd_in[219]
  PIN w0_wd_in[220]
    DIRECTION INPUT ;
    USE SIGNAL ;
    SHAPE ABUTMENT ;
    PORT
      LAYER met3 ;
      RECT 5871.000 942.330 5871.900 942.630 ;
    END
  END w0_wd_in[220]
  PIN w0_wd_in[221]
    DIRECTION INPUT ;
    USE SIGNAL ;
    SHAPE ABUTMENT ;
    PORT
      LAYER met3 ;
      RECT 5871.000 952.530 5871.900 952.830 ;
    END
  END w0_wd_in[221]
  PIN w0_wd_in[222]
    DIRECTION INPUT ;
    USE SIGNAL ;
    SHAPE ABUTMENT ;
    PORT
      LAYER met3 ;
      RECT 5871.000 962.730 5871.900 963.030 ;
    END
  END w0_wd_in[222]
  PIN w0_wd_in[223]
    DIRECTION INPUT ;
    USE SIGNAL ;
    SHAPE ABUTMENT ;
    PORT
      LAYER met3 ;
      RECT 5871.000 972.930 5871.900 973.230 ;
    END
  END w0_wd_in[223]
  PIN w0_wd_in[224]
    DIRECTION INPUT ;
    USE SIGNAL ;
    SHAPE ABUTMENT ;
    PORT
      LAYER met3 ;
      RECT 5871.000 983.130 5871.900 983.430 ;
    END
  END w0_wd_in[224]
  PIN w0_wd_in[225]
    DIRECTION INPUT ;
    USE SIGNAL ;
    SHAPE ABUTMENT ;
    PORT
      LAYER met3 ;
      RECT 5871.000 993.330 5871.900 993.630 ;
    END
  END w0_wd_in[225]
  PIN w0_wd_in[226]
    DIRECTION INPUT ;
    USE SIGNAL ;
    SHAPE ABUTMENT ;
    PORT
      LAYER met3 ;
      RECT 5871.000 1003.530 5871.900 1003.830 ;
    END
  END w0_wd_in[226]
  PIN w0_wd_in[227]
    DIRECTION INPUT ;
    USE SIGNAL ;
    SHAPE ABUTMENT ;
    PORT
      LAYER met3 ;
      RECT 5871.000 1013.730 5871.900 1014.030 ;
    END
  END w0_wd_in[227]
  PIN w0_wd_in[228]
    DIRECTION INPUT ;
    USE SIGNAL ;
    SHAPE ABUTMENT ;
    PORT
      LAYER met3 ;
      RECT 5871.000 1023.930 5871.900 1024.230 ;
    END
  END w0_wd_in[228]
  PIN w0_wd_in[229]
    DIRECTION INPUT ;
    USE SIGNAL ;
    SHAPE ABUTMENT ;
    PORT
      LAYER met3 ;
      RECT 5871.000 1034.130 5871.900 1034.430 ;
    END
  END w0_wd_in[229]
  PIN w0_wd_in[230]
    DIRECTION INPUT ;
    USE SIGNAL ;
    SHAPE ABUTMENT ;
    PORT
      LAYER met3 ;
      RECT 5871.000 1044.330 5871.900 1044.630 ;
    END
  END w0_wd_in[230]
  PIN w0_wd_in[231]
    DIRECTION INPUT ;
    USE SIGNAL ;
    SHAPE ABUTMENT ;
    PORT
      LAYER met3 ;
      RECT 5871.000 1054.530 5871.900 1054.830 ;
    END
  END w0_wd_in[231]
  PIN w0_wd_in[232]
    DIRECTION INPUT ;
    USE SIGNAL ;
    SHAPE ABUTMENT ;
    PORT
      LAYER met3 ;
      RECT 5871.000 1064.730 5871.900 1065.030 ;
    END
  END w0_wd_in[232]
  PIN w0_wd_in[233]
    DIRECTION INPUT ;
    USE SIGNAL ;
    SHAPE ABUTMENT ;
    PORT
      LAYER met3 ;
      RECT 5871.000 1074.930 5871.900 1075.230 ;
    END
  END w0_wd_in[233]
  PIN w0_wd_in[234]
    DIRECTION INPUT ;
    USE SIGNAL ;
    SHAPE ABUTMENT ;
    PORT
      LAYER met3 ;
      RECT 5871.000 1085.130 5871.900 1085.430 ;
    END
  END w0_wd_in[234]
  PIN w0_wd_in[235]
    DIRECTION INPUT ;
    USE SIGNAL ;
    SHAPE ABUTMENT ;
    PORT
      LAYER met3 ;
      RECT 5871.000 1095.330 5871.900 1095.630 ;
    END
  END w0_wd_in[235]
  PIN w0_wd_in[236]
    DIRECTION INPUT ;
    USE SIGNAL ;
    SHAPE ABUTMENT ;
    PORT
      LAYER met3 ;
      RECT 5871.000 1105.530 5871.900 1105.830 ;
    END
  END w0_wd_in[236]
  PIN w0_wd_in[237]
    DIRECTION INPUT ;
    USE SIGNAL ;
    SHAPE ABUTMENT ;
    PORT
      LAYER met3 ;
      RECT 5871.000 1115.730 5871.900 1116.030 ;
    END
  END w0_wd_in[237]
  PIN w0_wd_in[238]
    DIRECTION INPUT ;
    USE SIGNAL ;
    SHAPE ABUTMENT ;
    PORT
      LAYER met3 ;
      RECT 5871.000 1125.930 5871.900 1126.230 ;
    END
  END w0_wd_in[238]
  PIN w0_wd_in[239]
    DIRECTION INPUT ;
    USE SIGNAL ;
    SHAPE ABUTMENT ;
    PORT
      LAYER met3 ;
      RECT 5871.000 1136.130 5871.900 1136.430 ;
    END
  END w0_wd_in[239]
  PIN w0_wd_in[240]
    DIRECTION INPUT ;
    USE SIGNAL ;
    SHAPE ABUTMENT ;
    PORT
      LAYER met3 ;
      RECT 5871.000 1146.330 5871.900 1146.630 ;
    END
  END w0_wd_in[240]
  PIN w0_wd_in[241]
    DIRECTION INPUT ;
    USE SIGNAL ;
    SHAPE ABUTMENT ;
    PORT
      LAYER met3 ;
      RECT 5871.000 1156.530 5871.900 1156.830 ;
    END
  END w0_wd_in[241]
  PIN w0_wd_in[242]
    DIRECTION INPUT ;
    USE SIGNAL ;
    SHAPE ABUTMENT ;
    PORT
      LAYER met3 ;
      RECT 5871.000 1166.730 5871.900 1167.030 ;
    END
  END w0_wd_in[242]
  PIN w0_wd_in[243]
    DIRECTION INPUT ;
    USE SIGNAL ;
    SHAPE ABUTMENT ;
    PORT
      LAYER met3 ;
      RECT 5871.000 1176.930 5871.900 1177.230 ;
    END
  END w0_wd_in[243]
  PIN w0_wd_in[244]
    DIRECTION INPUT ;
    USE SIGNAL ;
    SHAPE ABUTMENT ;
    PORT
      LAYER met3 ;
      RECT 5871.000 1187.130 5871.900 1187.430 ;
    END
  END w0_wd_in[244]
  PIN w0_wd_in[245]
    DIRECTION INPUT ;
    USE SIGNAL ;
    SHAPE ABUTMENT ;
    PORT
      LAYER met3 ;
      RECT 5871.000 1197.330 5871.900 1197.630 ;
    END
  END w0_wd_in[245]
  PIN w0_wd_in[246]
    DIRECTION INPUT ;
    USE SIGNAL ;
    SHAPE ABUTMENT ;
    PORT
      LAYER met3 ;
      RECT 5871.000 1207.530 5871.900 1207.830 ;
    END
  END w0_wd_in[246]
  PIN w0_wd_in[247]
    DIRECTION INPUT ;
    USE SIGNAL ;
    SHAPE ABUTMENT ;
    PORT
      LAYER met3 ;
      RECT 5871.000 1217.730 5871.900 1218.030 ;
    END
  END w0_wd_in[247]
  PIN w0_wd_in[248]
    DIRECTION INPUT ;
    USE SIGNAL ;
    SHAPE ABUTMENT ;
    PORT
      LAYER met3 ;
      RECT 5871.000 1227.930 5871.900 1228.230 ;
    END
  END w0_wd_in[248]
  PIN w0_wd_in[249]
    DIRECTION INPUT ;
    USE SIGNAL ;
    SHAPE ABUTMENT ;
    PORT
      LAYER met3 ;
      RECT 5871.000 1238.130 5871.900 1238.430 ;
    END
  END w0_wd_in[249]
  PIN w0_wd_in[250]
    DIRECTION INPUT ;
    USE SIGNAL ;
    SHAPE ABUTMENT ;
    PORT
      LAYER met3 ;
      RECT 5871.000 1248.330 5871.900 1248.630 ;
    END
  END w0_wd_in[250]
  PIN w0_wd_in[251]
    DIRECTION INPUT ;
    USE SIGNAL ;
    SHAPE ABUTMENT ;
    PORT
      LAYER met3 ;
      RECT 5871.000 1258.530 5871.900 1258.830 ;
    END
  END w0_wd_in[251]
  PIN w0_wd_in[252]
    DIRECTION INPUT ;
    USE SIGNAL ;
    SHAPE ABUTMENT ;
    PORT
      LAYER met3 ;
      RECT 5871.000 1268.730 5871.900 1269.030 ;
    END
  END w0_wd_in[252]
  PIN w0_wd_in[253]
    DIRECTION INPUT ;
    USE SIGNAL ;
    SHAPE ABUTMENT ;
    PORT
      LAYER met3 ;
      RECT 5871.000 1278.930 5871.900 1279.230 ;
    END
  END w0_wd_in[253]
  PIN w0_wd_in[254]
    DIRECTION INPUT ;
    USE SIGNAL ;
    SHAPE ABUTMENT ;
    PORT
      LAYER met3 ;
      RECT 5871.000 1289.130 5871.900 1289.430 ;
    END
  END w0_wd_in[254]
  PIN w0_wd_in[255]
    DIRECTION INPUT ;
    USE SIGNAL ;
    SHAPE ABUTMENT ;
    PORT
      LAYER met3 ;
      RECT 5871.000 1299.330 5871.900 1299.630 ;
    END
  END w0_wd_in[255]
  PIN w0_wd_in[256]
    DIRECTION OUTPUT ;
    USE SIGNAL ;
    SHAPE ABUTMENT ;
    PORT
      LAYER met2 ;
      RECT 2.690 0.000 2.830 0.420 ;
    END
  END w0_wd_in[256]
  PIN w0_wd_in[257]
    DIRECTION OUTPUT ;
    USE SIGNAL ;
    SHAPE ABUTMENT ;
    PORT
      LAYER met2 ;
      RECT 13.730 0.000 13.870 0.420 ;
    END
  END w0_wd_in[257]
  PIN w0_wd_in[258]
    DIRECTION OUTPUT ;
    USE SIGNAL ;
    SHAPE ABUTMENT ;
    PORT
      LAYER met2 ;
      RECT 24.770 0.000 24.910 0.420 ;
    END
  END w0_wd_in[258]
  PIN w0_wd_in[259]
    DIRECTION OUTPUT ;
    USE SIGNAL ;
    SHAPE ABUTMENT ;
    PORT
      LAYER met2 ;
      RECT 35.810 0.000 35.950 0.420 ;
    END
  END w0_wd_in[259]
  PIN w0_wd_in[260]
    DIRECTION OUTPUT ;
    USE SIGNAL ;
    SHAPE ABUTMENT ;
    PORT
      LAYER met2 ;
      RECT 46.850 0.000 46.990 0.420 ;
    END
  END w0_wd_in[260]
  PIN w0_wd_in[261]
    DIRECTION OUTPUT ;
    USE SIGNAL ;
    SHAPE ABUTMENT ;
    PORT
      LAYER met2 ;
      RECT 57.890 0.000 58.030 0.420 ;
    END
  END w0_wd_in[261]
  PIN w0_wd_in[262]
    DIRECTION OUTPUT ;
    USE SIGNAL ;
    SHAPE ABUTMENT ;
    PORT
      LAYER met2 ;
      RECT 68.930 0.000 69.070 0.420 ;
    END
  END w0_wd_in[262]
  PIN w0_wd_in[263]
    DIRECTION OUTPUT ;
    USE SIGNAL ;
    SHAPE ABUTMENT ;
    PORT
      LAYER met2 ;
      RECT 79.970 0.000 80.110 0.420 ;
    END
  END w0_wd_in[263]
  PIN w0_wd_in[264]
    DIRECTION OUTPUT ;
    USE SIGNAL ;
    SHAPE ABUTMENT ;
    PORT
      LAYER met2 ;
      RECT 91.010 0.000 91.150 0.420 ;
    END
  END w0_wd_in[264]
  PIN w0_wd_in[265]
    DIRECTION OUTPUT ;
    USE SIGNAL ;
    SHAPE ABUTMENT ;
    PORT
      LAYER met2 ;
      RECT 102.050 0.000 102.190 0.420 ;
    END
  END w0_wd_in[265]
  PIN w0_wd_in[266]
    DIRECTION OUTPUT ;
    USE SIGNAL ;
    SHAPE ABUTMENT ;
    PORT
      LAYER met2 ;
      RECT 113.090 0.000 113.230 0.420 ;
    END
  END w0_wd_in[266]
  PIN w0_wd_in[267]
    DIRECTION OUTPUT ;
    USE SIGNAL ;
    SHAPE ABUTMENT ;
    PORT
      LAYER met2 ;
      RECT 124.130 0.000 124.270 0.420 ;
    END
  END w0_wd_in[267]
  PIN w0_wd_in[268]
    DIRECTION OUTPUT ;
    USE SIGNAL ;
    SHAPE ABUTMENT ;
    PORT
      LAYER met2 ;
      RECT 135.170 0.000 135.310 0.420 ;
    END
  END w0_wd_in[268]
  PIN w0_wd_in[269]
    DIRECTION OUTPUT ;
    USE SIGNAL ;
    SHAPE ABUTMENT ;
    PORT
      LAYER met2 ;
      RECT 146.210 0.000 146.350 0.420 ;
    END
  END w0_wd_in[269]
  PIN w0_wd_in[270]
    DIRECTION OUTPUT ;
    USE SIGNAL ;
    SHAPE ABUTMENT ;
    PORT
      LAYER met2 ;
      RECT 157.250 0.000 157.390 0.420 ;
    END
  END w0_wd_in[270]
  PIN w0_wd_in[271]
    DIRECTION OUTPUT ;
    USE SIGNAL ;
    SHAPE ABUTMENT ;
    PORT
      LAYER met2 ;
      RECT 168.290 0.000 168.430 0.420 ;
    END
  END w0_wd_in[271]
  PIN w0_wd_in[272]
    DIRECTION OUTPUT ;
    USE SIGNAL ;
    SHAPE ABUTMENT ;
    PORT
      LAYER met2 ;
      RECT 179.330 0.000 179.470 0.420 ;
    END
  END w0_wd_in[272]
  PIN w0_wd_in[273]
    DIRECTION OUTPUT ;
    USE SIGNAL ;
    SHAPE ABUTMENT ;
    PORT
      LAYER met2 ;
      RECT 190.370 0.000 190.510 0.420 ;
    END
  END w0_wd_in[273]
  PIN w0_wd_in[274]
    DIRECTION OUTPUT ;
    USE SIGNAL ;
    SHAPE ABUTMENT ;
    PORT
      LAYER met2 ;
      RECT 201.410 0.000 201.550 0.420 ;
    END
  END w0_wd_in[274]
  PIN w0_wd_in[275]
    DIRECTION OUTPUT ;
    USE SIGNAL ;
    SHAPE ABUTMENT ;
    PORT
      LAYER met2 ;
      RECT 212.450 0.000 212.590 0.420 ;
    END
  END w0_wd_in[275]
  PIN w0_wd_in[276]
    DIRECTION OUTPUT ;
    USE SIGNAL ;
    SHAPE ABUTMENT ;
    PORT
      LAYER met2 ;
      RECT 223.490 0.000 223.630 0.420 ;
    END
  END w0_wd_in[276]
  PIN w0_wd_in[277]
    DIRECTION OUTPUT ;
    USE SIGNAL ;
    SHAPE ABUTMENT ;
    PORT
      LAYER met2 ;
      RECT 234.530 0.000 234.670 0.420 ;
    END
  END w0_wd_in[277]
  PIN w0_wd_in[278]
    DIRECTION OUTPUT ;
    USE SIGNAL ;
    SHAPE ABUTMENT ;
    PORT
      LAYER met2 ;
      RECT 245.570 0.000 245.710 0.420 ;
    END
  END w0_wd_in[278]
  PIN w0_wd_in[279]
    DIRECTION OUTPUT ;
    USE SIGNAL ;
    SHAPE ABUTMENT ;
    PORT
      LAYER met2 ;
      RECT 256.610 0.000 256.750 0.420 ;
    END
  END w0_wd_in[279]
  PIN w0_wd_in[280]
    DIRECTION OUTPUT ;
    USE SIGNAL ;
    SHAPE ABUTMENT ;
    PORT
      LAYER met2 ;
      RECT 267.650 0.000 267.790 0.420 ;
    END
  END w0_wd_in[280]
  PIN w0_wd_in[281]
    DIRECTION OUTPUT ;
    USE SIGNAL ;
    SHAPE ABUTMENT ;
    PORT
      LAYER met2 ;
      RECT 278.690 0.000 278.830 0.420 ;
    END
  END w0_wd_in[281]
  PIN w0_wd_in[282]
    DIRECTION OUTPUT ;
    USE SIGNAL ;
    SHAPE ABUTMENT ;
    PORT
      LAYER met2 ;
      RECT 289.730 0.000 289.870 0.420 ;
    END
  END w0_wd_in[282]
  PIN w0_wd_in[283]
    DIRECTION OUTPUT ;
    USE SIGNAL ;
    SHAPE ABUTMENT ;
    PORT
      LAYER met2 ;
      RECT 300.770 0.000 300.910 0.420 ;
    END
  END w0_wd_in[283]
  PIN w0_wd_in[284]
    DIRECTION OUTPUT ;
    USE SIGNAL ;
    SHAPE ABUTMENT ;
    PORT
      LAYER met2 ;
      RECT 311.810 0.000 311.950 0.420 ;
    END
  END w0_wd_in[284]
  PIN w0_wd_in[285]
    DIRECTION OUTPUT ;
    USE SIGNAL ;
    SHAPE ABUTMENT ;
    PORT
      LAYER met2 ;
      RECT 322.850 0.000 322.990 0.420 ;
    END
  END w0_wd_in[285]
  PIN w0_wd_in[286]
    DIRECTION OUTPUT ;
    USE SIGNAL ;
    SHAPE ABUTMENT ;
    PORT
      LAYER met2 ;
      RECT 333.890 0.000 334.030 0.420 ;
    END
  END w0_wd_in[286]
  PIN w0_wd_in[287]
    DIRECTION OUTPUT ;
    USE SIGNAL ;
    SHAPE ABUTMENT ;
    PORT
      LAYER met2 ;
      RECT 344.930 0.000 345.070 0.420 ;
    END
  END w0_wd_in[287]
  PIN w0_wd_in[288]
    DIRECTION OUTPUT ;
    USE SIGNAL ;
    SHAPE ABUTMENT ;
    PORT
      LAYER met2 ;
      RECT 355.970 0.000 356.110 0.420 ;
    END
  END w0_wd_in[288]
  PIN w0_wd_in[289]
    DIRECTION OUTPUT ;
    USE SIGNAL ;
    SHAPE ABUTMENT ;
    PORT
      LAYER met2 ;
      RECT 367.010 0.000 367.150 0.420 ;
    END
  END w0_wd_in[289]
  PIN w0_wd_in[290]
    DIRECTION OUTPUT ;
    USE SIGNAL ;
    SHAPE ABUTMENT ;
    PORT
      LAYER met2 ;
      RECT 378.050 0.000 378.190 0.420 ;
    END
  END w0_wd_in[290]
  PIN w0_wd_in[291]
    DIRECTION OUTPUT ;
    USE SIGNAL ;
    SHAPE ABUTMENT ;
    PORT
      LAYER met2 ;
      RECT 389.090 0.000 389.230 0.420 ;
    END
  END w0_wd_in[291]
  PIN w0_wd_in[292]
    DIRECTION OUTPUT ;
    USE SIGNAL ;
    SHAPE ABUTMENT ;
    PORT
      LAYER met2 ;
      RECT 400.130 0.000 400.270 0.420 ;
    END
  END w0_wd_in[292]
  PIN w0_wd_in[293]
    DIRECTION OUTPUT ;
    USE SIGNAL ;
    SHAPE ABUTMENT ;
    PORT
      LAYER met2 ;
      RECT 411.170 0.000 411.310 0.420 ;
    END
  END w0_wd_in[293]
  PIN w0_wd_in[294]
    DIRECTION OUTPUT ;
    USE SIGNAL ;
    SHAPE ABUTMENT ;
    PORT
      LAYER met2 ;
      RECT 422.210 0.000 422.350 0.420 ;
    END
  END w0_wd_in[294]
  PIN w0_wd_in[295]
    DIRECTION OUTPUT ;
    USE SIGNAL ;
    SHAPE ABUTMENT ;
    PORT
      LAYER met2 ;
      RECT 433.250 0.000 433.390 0.420 ;
    END
  END w0_wd_in[295]
  PIN w0_wd_in[296]
    DIRECTION OUTPUT ;
    USE SIGNAL ;
    SHAPE ABUTMENT ;
    PORT
      LAYER met2 ;
      RECT 444.290 0.000 444.430 0.420 ;
    END
  END w0_wd_in[296]
  PIN w0_wd_in[297]
    DIRECTION OUTPUT ;
    USE SIGNAL ;
    SHAPE ABUTMENT ;
    PORT
      LAYER met2 ;
      RECT 455.330 0.000 455.470 0.420 ;
    END
  END w0_wd_in[297]
  PIN w0_wd_in[298]
    DIRECTION OUTPUT ;
    USE SIGNAL ;
    SHAPE ABUTMENT ;
    PORT
      LAYER met2 ;
      RECT 466.370 0.000 466.510 0.420 ;
    END
  END w0_wd_in[298]
  PIN w0_wd_in[299]
    DIRECTION OUTPUT ;
    USE SIGNAL ;
    SHAPE ABUTMENT ;
    PORT
      LAYER met2 ;
      RECT 477.410 0.000 477.550 0.420 ;
    END
  END w0_wd_in[299]
  PIN w0_wd_in[300]
    DIRECTION OUTPUT ;
    USE SIGNAL ;
    SHAPE ABUTMENT ;
    PORT
      LAYER met2 ;
      RECT 488.450 0.000 488.590 0.420 ;
    END
  END w0_wd_in[300]
  PIN w0_wd_in[301]
    DIRECTION OUTPUT ;
    USE SIGNAL ;
    SHAPE ABUTMENT ;
    PORT
      LAYER met2 ;
      RECT 499.490 0.000 499.630 0.420 ;
    END
  END w0_wd_in[301]
  PIN w0_wd_in[302]
    DIRECTION OUTPUT ;
    USE SIGNAL ;
    SHAPE ABUTMENT ;
    PORT
      LAYER met2 ;
      RECT 510.530 0.000 510.670 0.420 ;
    END
  END w0_wd_in[302]
  PIN w0_wd_in[303]
    DIRECTION OUTPUT ;
    USE SIGNAL ;
    SHAPE ABUTMENT ;
    PORT
      LAYER met2 ;
      RECT 521.570 0.000 521.710 0.420 ;
    END
  END w0_wd_in[303]
  PIN w0_wd_in[304]
    DIRECTION OUTPUT ;
    USE SIGNAL ;
    SHAPE ABUTMENT ;
    PORT
      LAYER met2 ;
      RECT 532.610 0.000 532.750 0.420 ;
    END
  END w0_wd_in[304]
  PIN w0_wd_in[305]
    DIRECTION OUTPUT ;
    USE SIGNAL ;
    SHAPE ABUTMENT ;
    PORT
      LAYER met2 ;
      RECT 543.650 0.000 543.790 0.420 ;
    END
  END w0_wd_in[305]
  PIN w0_wd_in[306]
    DIRECTION OUTPUT ;
    USE SIGNAL ;
    SHAPE ABUTMENT ;
    PORT
      LAYER met2 ;
      RECT 554.690 0.000 554.830 0.420 ;
    END
  END w0_wd_in[306]
  PIN w0_wd_in[307]
    DIRECTION OUTPUT ;
    USE SIGNAL ;
    SHAPE ABUTMENT ;
    PORT
      LAYER met2 ;
      RECT 565.730 0.000 565.870 0.420 ;
    END
  END w0_wd_in[307]
  PIN w0_wd_in[308]
    DIRECTION OUTPUT ;
    USE SIGNAL ;
    SHAPE ABUTMENT ;
    PORT
      LAYER met2 ;
      RECT 576.770 0.000 576.910 0.420 ;
    END
  END w0_wd_in[308]
  PIN w0_wd_in[309]
    DIRECTION OUTPUT ;
    USE SIGNAL ;
    SHAPE ABUTMENT ;
    PORT
      LAYER met2 ;
      RECT 587.810 0.000 587.950 0.420 ;
    END
  END w0_wd_in[309]
  PIN w0_wd_in[310]
    DIRECTION OUTPUT ;
    USE SIGNAL ;
    SHAPE ABUTMENT ;
    PORT
      LAYER met2 ;
      RECT 598.850 0.000 598.990 0.420 ;
    END
  END w0_wd_in[310]
  PIN w0_wd_in[311]
    DIRECTION OUTPUT ;
    USE SIGNAL ;
    SHAPE ABUTMENT ;
    PORT
      LAYER met2 ;
      RECT 609.890 0.000 610.030 0.420 ;
    END
  END w0_wd_in[311]
  PIN w0_wd_in[312]
    DIRECTION OUTPUT ;
    USE SIGNAL ;
    SHAPE ABUTMENT ;
    PORT
      LAYER met2 ;
      RECT 620.930 0.000 621.070 0.420 ;
    END
  END w0_wd_in[312]
  PIN w0_wd_in[313]
    DIRECTION OUTPUT ;
    USE SIGNAL ;
    SHAPE ABUTMENT ;
    PORT
      LAYER met2 ;
      RECT 631.970 0.000 632.110 0.420 ;
    END
  END w0_wd_in[313]
  PIN w0_wd_in[314]
    DIRECTION OUTPUT ;
    USE SIGNAL ;
    SHAPE ABUTMENT ;
    PORT
      LAYER met2 ;
      RECT 643.010 0.000 643.150 0.420 ;
    END
  END w0_wd_in[314]
  PIN w0_wd_in[315]
    DIRECTION OUTPUT ;
    USE SIGNAL ;
    SHAPE ABUTMENT ;
    PORT
      LAYER met2 ;
      RECT 654.050 0.000 654.190 0.420 ;
    END
  END w0_wd_in[315]
  PIN w0_wd_in[316]
    DIRECTION OUTPUT ;
    USE SIGNAL ;
    SHAPE ABUTMENT ;
    PORT
      LAYER met2 ;
      RECT 665.090 0.000 665.230 0.420 ;
    END
  END w0_wd_in[316]
  PIN w0_wd_in[317]
    DIRECTION OUTPUT ;
    USE SIGNAL ;
    SHAPE ABUTMENT ;
    PORT
      LAYER met2 ;
      RECT 676.130 0.000 676.270 0.420 ;
    END
  END w0_wd_in[317]
  PIN w0_wd_in[318]
    DIRECTION OUTPUT ;
    USE SIGNAL ;
    SHAPE ABUTMENT ;
    PORT
      LAYER met2 ;
      RECT 687.170 0.000 687.310 0.420 ;
    END
  END w0_wd_in[318]
  PIN w0_wd_in[319]
    DIRECTION OUTPUT ;
    USE SIGNAL ;
    SHAPE ABUTMENT ;
    PORT
      LAYER met2 ;
      RECT 698.210 0.000 698.350 0.420 ;
    END
  END w0_wd_in[319]
  PIN w0_wd_in[320]
    DIRECTION OUTPUT ;
    USE SIGNAL ;
    SHAPE ABUTMENT ;
    PORT
      LAYER met2 ;
      RECT 709.250 0.000 709.390 0.420 ;
    END
  END w0_wd_in[320]
  PIN w0_wd_in[321]
    DIRECTION OUTPUT ;
    USE SIGNAL ;
    SHAPE ABUTMENT ;
    PORT
      LAYER met2 ;
      RECT 720.290 0.000 720.430 0.420 ;
    END
  END w0_wd_in[321]
  PIN w0_wd_in[322]
    DIRECTION OUTPUT ;
    USE SIGNAL ;
    SHAPE ABUTMENT ;
    PORT
      LAYER met2 ;
      RECT 731.330 0.000 731.470 0.420 ;
    END
  END w0_wd_in[322]
  PIN w0_wd_in[323]
    DIRECTION OUTPUT ;
    USE SIGNAL ;
    SHAPE ABUTMENT ;
    PORT
      LAYER met2 ;
      RECT 742.370 0.000 742.510 0.420 ;
    END
  END w0_wd_in[323]
  PIN w0_wd_in[324]
    DIRECTION OUTPUT ;
    USE SIGNAL ;
    SHAPE ABUTMENT ;
    PORT
      LAYER met2 ;
      RECT 753.410 0.000 753.550 0.420 ;
    END
  END w0_wd_in[324]
  PIN w0_wd_in[325]
    DIRECTION OUTPUT ;
    USE SIGNAL ;
    SHAPE ABUTMENT ;
    PORT
      LAYER met2 ;
      RECT 764.450 0.000 764.590 0.420 ;
    END
  END w0_wd_in[325]
  PIN w0_wd_in[326]
    DIRECTION OUTPUT ;
    USE SIGNAL ;
    SHAPE ABUTMENT ;
    PORT
      LAYER met2 ;
      RECT 775.490 0.000 775.630 0.420 ;
    END
  END w0_wd_in[326]
  PIN w0_wd_in[327]
    DIRECTION OUTPUT ;
    USE SIGNAL ;
    SHAPE ABUTMENT ;
    PORT
      LAYER met2 ;
      RECT 786.530 0.000 786.670 0.420 ;
    END
  END w0_wd_in[327]
  PIN w0_wd_in[328]
    DIRECTION OUTPUT ;
    USE SIGNAL ;
    SHAPE ABUTMENT ;
    PORT
      LAYER met2 ;
      RECT 797.570 0.000 797.710 0.420 ;
    END
  END w0_wd_in[328]
  PIN w0_wd_in[329]
    DIRECTION OUTPUT ;
    USE SIGNAL ;
    SHAPE ABUTMENT ;
    PORT
      LAYER met2 ;
      RECT 808.610 0.000 808.750 0.420 ;
    END
  END w0_wd_in[329]
  PIN w0_wd_in[330]
    DIRECTION OUTPUT ;
    USE SIGNAL ;
    SHAPE ABUTMENT ;
    PORT
      LAYER met2 ;
      RECT 819.650 0.000 819.790 0.420 ;
    END
  END w0_wd_in[330]
  PIN w0_wd_in[331]
    DIRECTION OUTPUT ;
    USE SIGNAL ;
    SHAPE ABUTMENT ;
    PORT
      LAYER met2 ;
      RECT 830.690 0.000 830.830 0.420 ;
    END
  END w0_wd_in[331]
  PIN w0_wd_in[332]
    DIRECTION OUTPUT ;
    USE SIGNAL ;
    SHAPE ABUTMENT ;
    PORT
      LAYER met2 ;
      RECT 841.730 0.000 841.870 0.420 ;
    END
  END w0_wd_in[332]
  PIN w0_wd_in[333]
    DIRECTION OUTPUT ;
    USE SIGNAL ;
    SHAPE ABUTMENT ;
    PORT
      LAYER met2 ;
      RECT 852.770 0.000 852.910 0.420 ;
    END
  END w0_wd_in[333]
  PIN w0_wd_in[334]
    DIRECTION OUTPUT ;
    USE SIGNAL ;
    SHAPE ABUTMENT ;
    PORT
      LAYER met2 ;
      RECT 863.810 0.000 863.950 0.420 ;
    END
  END w0_wd_in[334]
  PIN w0_wd_in[335]
    DIRECTION OUTPUT ;
    USE SIGNAL ;
    SHAPE ABUTMENT ;
    PORT
      LAYER met2 ;
      RECT 874.850 0.000 874.990 0.420 ;
    END
  END w0_wd_in[335]
  PIN w0_wd_in[336]
    DIRECTION OUTPUT ;
    USE SIGNAL ;
    SHAPE ABUTMENT ;
    PORT
      LAYER met2 ;
      RECT 885.890 0.000 886.030 0.420 ;
    END
  END w0_wd_in[336]
  PIN w0_wd_in[337]
    DIRECTION OUTPUT ;
    USE SIGNAL ;
    SHAPE ABUTMENT ;
    PORT
      LAYER met2 ;
      RECT 896.930 0.000 897.070 0.420 ;
    END
  END w0_wd_in[337]
  PIN w0_wd_in[338]
    DIRECTION OUTPUT ;
    USE SIGNAL ;
    SHAPE ABUTMENT ;
    PORT
      LAYER met2 ;
      RECT 907.970 0.000 908.110 0.420 ;
    END
  END w0_wd_in[338]
  PIN w0_wd_in[339]
    DIRECTION OUTPUT ;
    USE SIGNAL ;
    SHAPE ABUTMENT ;
    PORT
      LAYER met2 ;
      RECT 919.010 0.000 919.150 0.420 ;
    END
  END w0_wd_in[339]
  PIN w0_wd_in[340]
    DIRECTION OUTPUT ;
    USE SIGNAL ;
    SHAPE ABUTMENT ;
    PORT
      LAYER met2 ;
      RECT 930.050 0.000 930.190 0.420 ;
    END
  END w0_wd_in[340]
  PIN w0_wd_in[341]
    DIRECTION OUTPUT ;
    USE SIGNAL ;
    SHAPE ABUTMENT ;
    PORT
      LAYER met2 ;
      RECT 941.090 0.000 941.230 0.420 ;
    END
  END w0_wd_in[341]
  PIN w0_wd_in[342]
    DIRECTION OUTPUT ;
    USE SIGNAL ;
    SHAPE ABUTMENT ;
    PORT
      LAYER met2 ;
      RECT 952.130 0.000 952.270 0.420 ;
    END
  END w0_wd_in[342]
  PIN w0_wd_in[343]
    DIRECTION OUTPUT ;
    USE SIGNAL ;
    SHAPE ABUTMENT ;
    PORT
      LAYER met2 ;
      RECT 963.170 0.000 963.310 0.420 ;
    END
  END w0_wd_in[343]
  PIN w0_wd_in[344]
    DIRECTION OUTPUT ;
    USE SIGNAL ;
    SHAPE ABUTMENT ;
    PORT
      LAYER met2 ;
      RECT 974.210 0.000 974.350 0.420 ;
    END
  END w0_wd_in[344]
  PIN w0_wd_in[345]
    DIRECTION OUTPUT ;
    USE SIGNAL ;
    SHAPE ABUTMENT ;
    PORT
      LAYER met2 ;
      RECT 985.250 0.000 985.390 0.420 ;
    END
  END w0_wd_in[345]
  PIN w0_wd_in[346]
    DIRECTION OUTPUT ;
    USE SIGNAL ;
    SHAPE ABUTMENT ;
    PORT
      LAYER met2 ;
      RECT 996.290 0.000 996.430 0.420 ;
    END
  END w0_wd_in[346]
  PIN w0_wd_in[347]
    DIRECTION OUTPUT ;
    USE SIGNAL ;
    SHAPE ABUTMENT ;
    PORT
      LAYER met2 ;
      RECT 1007.330 0.000 1007.470 0.420 ;
    END
  END w0_wd_in[347]
  PIN w0_wd_in[348]
    DIRECTION OUTPUT ;
    USE SIGNAL ;
    SHAPE ABUTMENT ;
    PORT
      LAYER met2 ;
      RECT 1018.370 0.000 1018.510 0.420 ;
    END
  END w0_wd_in[348]
  PIN w0_wd_in[349]
    DIRECTION OUTPUT ;
    USE SIGNAL ;
    SHAPE ABUTMENT ;
    PORT
      LAYER met2 ;
      RECT 1029.410 0.000 1029.550 0.420 ;
    END
  END w0_wd_in[349]
  PIN w0_wd_in[350]
    DIRECTION OUTPUT ;
    USE SIGNAL ;
    SHAPE ABUTMENT ;
    PORT
      LAYER met2 ;
      RECT 1040.450 0.000 1040.590 0.420 ;
    END
  END w0_wd_in[350]
  PIN w0_wd_in[351]
    DIRECTION OUTPUT ;
    USE SIGNAL ;
    SHAPE ABUTMENT ;
    PORT
      LAYER met2 ;
      RECT 1051.490 0.000 1051.630 0.420 ;
    END
  END w0_wd_in[351]
  PIN w0_wd_in[352]
    DIRECTION OUTPUT ;
    USE SIGNAL ;
    SHAPE ABUTMENT ;
    PORT
      LAYER met2 ;
      RECT 1062.530 0.000 1062.670 0.420 ;
    END
  END w0_wd_in[352]
  PIN w0_wd_in[353]
    DIRECTION OUTPUT ;
    USE SIGNAL ;
    SHAPE ABUTMENT ;
    PORT
      LAYER met2 ;
      RECT 1073.570 0.000 1073.710 0.420 ;
    END
  END w0_wd_in[353]
  PIN w0_wd_in[354]
    DIRECTION OUTPUT ;
    USE SIGNAL ;
    SHAPE ABUTMENT ;
    PORT
      LAYER met2 ;
      RECT 1084.610 0.000 1084.750 0.420 ;
    END
  END w0_wd_in[354]
  PIN w0_wd_in[355]
    DIRECTION OUTPUT ;
    USE SIGNAL ;
    SHAPE ABUTMENT ;
    PORT
      LAYER met2 ;
      RECT 1095.650 0.000 1095.790 0.420 ;
    END
  END w0_wd_in[355]
  PIN w0_wd_in[356]
    DIRECTION OUTPUT ;
    USE SIGNAL ;
    SHAPE ABUTMENT ;
    PORT
      LAYER met2 ;
      RECT 1106.690 0.000 1106.830 0.420 ;
    END
  END w0_wd_in[356]
  PIN w0_wd_in[357]
    DIRECTION OUTPUT ;
    USE SIGNAL ;
    SHAPE ABUTMENT ;
    PORT
      LAYER met2 ;
      RECT 1117.730 0.000 1117.870 0.420 ;
    END
  END w0_wd_in[357]
  PIN w0_wd_in[358]
    DIRECTION OUTPUT ;
    USE SIGNAL ;
    SHAPE ABUTMENT ;
    PORT
      LAYER met2 ;
      RECT 1128.770 0.000 1128.910 0.420 ;
    END
  END w0_wd_in[358]
  PIN w0_wd_in[359]
    DIRECTION OUTPUT ;
    USE SIGNAL ;
    SHAPE ABUTMENT ;
    PORT
      LAYER met2 ;
      RECT 1139.810 0.000 1139.950 0.420 ;
    END
  END w0_wd_in[359]
  PIN w0_wd_in[360]
    DIRECTION OUTPUT ;
    USE SIGNAL ;
    SHAPE ABUTMENT ;
    PORT
      LAYER met2 ;
      RECT 1150.850 0.000 1150.990 0.420 ;
    END
  END w0_wd_in[360]
  PIN w0_wd_in[361]
    DIRECTION OUTPUT ;
    USE SIGNAL ;
    SHAPE ABUTMENT ;
    PORT
      LAYER met2 ;
      RECT 1161.890 0.000 1162.030 0.420 ;
    END
  END w0_wd_in[361]
  PIN w0_wd_in[362]
    DIRECTION OUTPUT ;
    USE SIGNAL ;
    SHAPE ABUTMENT ;
    PORT
      LAYER met2 ;
      RECT 1172.930 0.000 1173.070 0.420 ;
    END
  END w0_wd_in[362]
  PIN w0_wd_in[363]
    DIRECTION OUTPUT ;
    USE SIGNAL ;
    SHAPE ABUTMENT ;
    PORT
      LAYER met2 ;
      RECT 1183.970 0.000 1184.110 0.420 ;
    END
  END w0_wd_in[363]
  PIN w0_wd_in[364]
    DIRECTION OUTPUT ;
    USE SIGNAL ;
    SHAPE ABUTMENT ;
    PORT
      LAYER met2 ;
      RECT 1195.010 0.000 1195.150 0.420 ;
    END
  END w0_wd_in[364]
  PIN w0_wd_in[365]
    DIRECTION OUTPUT ;
    USE SIGNAL ;
    SHAPE ABUTMENT ;
    PORT
      LAYER met2 ;
      RECT 1206.050 0.000 1206.190 0.420 ;
    END
  END w0_wd_in[365]
  PIN w0_wd_in[366]
    DIRECTION OUTPUT ;
    USE SIGNAL ;
    SHAPE ABUTMENT ;
    PORT
      LAYER met2 ;
      RECT 1217.090 0.000 1217.230 0.420 ;
    END
  END w0_wd_in[366]
  PIN w0_wd_in[367]
    DIRECTION OUTPUT ;
    USE SIGNAL ;
    SHAPE ABUTMENT ;
    PORT
      LAYER met2 ;
      RECT 1228.130 0.000 1228.270 0.420 ;
    END
  END w0_wd_in[367]
  PIN w0_wd_in[368]
    DIRECTION OUTPUT ;
    USE SIGNAL ;
    SHAPE ABUTMENT ;
    PORT
      LAYER met2 ;
      RECT 1239.170 0.000 1239.310 0.420 ;
    END
  END w0_wd_in[368]
  PIN w0_wd_in[369]
    DIRECTION OUTPUT ;
    USE SIGNAL ;
    SHAPE ABUTMENT ;
    PORT
      LAYER met2 ;
      RECT 1250.210 0.000 1250.350 0.420 ;
    END
  END w0_wd_in[369]
  PIN w0_wd_in[370]
    DIRECTION OUTPUT ;
    USE SIGNAL ;
    SHAPE ABUTMENT ;
    PORT
      LAYER met2 ;
      RECT 1261.250 0.000 1261.390 0.420 ;
    END
  END w0_wd_in[370]
  PIN w0_wd_in[371]
    DIRECTION OUTPUT ;
    USE SIGNAL ;
    SHAPE ABUTMENT ;
    PORT
      LAYER met2 ;
      RECT 1272.290 0.000 1272.430 0.420 ;
    END
  END w0_wd_in[371]
  PIN w0_wd_in[372]
    DIRECTION OUTPUT ;
    USE SIGNAL ;
    SHAPE ABUTMENT ;
    PORT
      LAYER met2 ;
      RECT 1283.330 0.000 1283.470 0.420 ;
    END
  END w0_wd_in[372]
  PIN w0_wd_in[373]
    DIRECTION OUTPUT ;
    USE SIGNAL ;
    SHAPE ABUTMENT ;
    PORT
      LAYER met2 ;
      RECT 1294.370 0.000 1294.510 0.420 ;
    END
  END w0_wd_in[373]
  PIN w0_wd_in[374]
    DIRECTION OUTPUT ;
    USE SIGNAL ;
    SHAPE ABUTMENT ;
    PORT
      LAYER met2 ;
      RECT 1305.410 0.000 1305.550 0.420 ;
    END
  END w0_wd_in[374]
  PIN w0_wd_in[375]
    DIRECTION OUTPUT ;
    USE SIGNAL ;
    SHAPE ABUTMENT ;
    PORT
      LAYER met2 ;
      RECT 1316.450 0.000 1316.590 0.420 ;
    END
  END w0_wd_in[375]
  PIN w0_wd_in[376]
    DIRECTION OUTPUT ;
    USE SIGNAL ;
    SHAPE ABUTMENT ;
    PORT
      LAYER met2 ;
      RECT 1327.490 0.000 1327.630 0.420 ;
    END
  END w0_wd_in[376]
  PIN w0_wd_in[377]
    DIRECTION OUTPUT ;
    USE SIGNAL ;
    SHAPE ABUTMENT ;
    PORT
      LAYER met2 ;
      RECT 1338.530 0.000 1338.670 0.420 ;
    END
  END w0_wd_in[377]
  PIN w0_wd_in[378]
    DIRECTION OUTPUT ;
    USE SIGNAL ;
    SHAPE ABUTMENT ;
    PORT
      LAYER met2 ;
      RECT 1349.570 0.000 1349.710 0.420 ;
    END
  END w0_wd_in[378]
  PIN w0_wd_in[379]
    DIRECTION OUTPUT ;
    USE SIGNAL ;
    SHAPE ABUTMENT ;
    PORT
      LAYER met2 ;
      RECT 1360.610 0.000 1360.750 0.420 ;
    END
  END w0_wd_in[379]
  PIN w0_wd_in[380]
    DIRECTION OUTPUT ;
    USE SIGNAL ;
    SHAPE ABUTMENT ;
    PORT
      LAYER met2 ;
      RECT 1371.650 0.000 1371.790 0.420 ;
    END
  END w0_wd_in[380]
  PIN w0_wd_in[381]
    DIRECTION OUTPUT ;
    USE SIGNAL ;
    SHAPE ABUTMENT ;
    PORT
      LAYER met2 ;
      RECT 1382.690 0.000 1382.830 0.420 ;
    END
  END w0_wd_in[381]
  PIN w0_wd_in[382]
    DIRECTION OUTPUT ;
    USE SIGNAL ;
    SHAPE ABUTMENT ;
    PORT
      LAYER met2 ;
      RECT 1393.730 0.000 1393.870 0.420 ;
    END
  END w0_wd_in[382]
  PIN w0_wd_in[383]
    DIRECTION OUTPUT ;
    USE SIGNAL ;
    SHAPE ABUTMENT ;
    PORT
      LAYER met2 ;
      RECT 1404.770 0.000 1404.910 0.420 ;
    END
  END w0_wd_in[383]
  PIN w0_wd_in[384]
    DIRECTION OUTPUT ;
    USE SIGNAL ;
    SHAPE ABUTMENT ;
    PORT
      LAYER met2 ;
      RECT 1415.810 0.000 1415.950 0.420 ;
    END
  END w0_wd_in[384]
  PIN w0_wd_in[385]
    DIRECTION OUTPUT ;
    USE SIGNAL ;
    SHAPE ABUTMENT ;
    PORT
      LAYER met2 ;
      RECT 1426.850 0.000 1426.990 0.420 ;
    END
  END w0_wd_in[385]
  PIN w0_wd_in[386]
    DIRECTION OUTPUT ;
    USE SIGNAL ;
    SHAPE ABUTMENT ;
    PORT
      LAYER met2 ;
      RECT 1437.890 0.000 1438.030 0.420 ;
    END
  END w0_wd_in[386]
  PIN w0_wd_in[387]
    DIRECTION OUTPUT ;
    USE SIGNAL ;
    SHAPE ABUTMENT ;
    PORT
      LAYER met2 ;
      RECT 1448.930 0.000 1449.070 0.420 ;
    END
  END w0_wd_in[387]
  PIN w0_wd_in[388]
    DIRECTION OUTPUT ;
    USE SIGNAL ;
    SHAPE ABUTMENT ;
    PORT
      LAYER met2 ;
      RECT 1459.970 0.000 1460.110 0.420 ;
    END
  END w0_wd_in[388]
  PIN w0_wd_in[389]
    DIRECTION OUTPUT ;
    USE SIGNAL ;
    SHAPE ABUTMENT ;
    PORT
      LAYER met2 ;
      RECT 1471.010 0.000 1471.150 0.420 ;
    END
  END w0_wd_in[389]
  PIN w0_wd_in[390]
    DIRECTION OUTPUT ;
    USE SIGNAL ;
    SHAPE ABUTMENT ;
    PORT
      LAYER met2 ;
      RECT 1482.050 0.000 1482.190 0.420 ;
    END
  END w0_wd_in[390]
  PIN w0_wd_in[391]
    DIRECTION OUTPUT ;
    USE SIGNAL ;
    SHAPE ABUTMENT ;
    PORT
      LAYER met2 ;
      RECT 1493.090 0.000 1493.230 0.420 ;
    END
  END w0_wd_in[391]
  PIN w0_wd_in[392]
    DIRECTION OUTPUT ;
    USE SIGNAL ;
    SHAPE ABUTMENT ;
    PORT
      LAYER met2 ;
      RECT 1504.130 0.000 1504.270 0.420 ;
    END
  END w0_wd_in[392]
  PIN w0_wd_in[393]
    DIRECTION OUTPUT ;
    USE SIGNAL ;
    SHAPE ABUTMENT ;
    PORT
      LAYER met2 ;
      RECT 1515.170 0.000 1515.310 0.420 ;
    END
  END w0_wd_in[393]
  PIN w0_wd_in[394]
    DIRECTION OUTPUT ;
    USE SIGNAL ;
    SHAPE ABUTMENT ;
    PORT
      LAYER met2 ;
      RECT 1526.210 0.000 1526.350 0.420 ;
    END
  END w0_wd_in[394]
  PIN w0_wd_in[395]
    DIRECTION OUTPUT ;
    USE SIGNAL ;
    SHAPE ABUTMENT ;
    PORT
      LAYER met2 ;
      RECT 1537.250 0.000 1537.390 0.420 ;
    END
  END w0_wd_in[395]
  PIN w0_wd_in[396]
    DIRECTION OUTPUT ;
    USE SIGNAL ;
    SHAPE ABUTMENT ;
    PORT
      LAYER met2 ;
      RECT 1548.290 0.000 1548.430 0.420 ;
    END
  END w0_wd_in[396]
  PIN w0_wd_in[397]
    DIRECTION OUTPUT ;
    USE SIGNAL ;
    SHAPE ABUTMENT ;
    PORT
      LAYER met2 ;
      RECT 1559.330 0.000 1559.470 0.420 ;
    END
  END w0_wd_in[397]
  PIN w0_wd_in[398]
    DIRECTION OUTPUT ;
    USE SIGNAL ;
    SHAPE ABUTMENT ;
    PORT
      LAYER met2 ;
      RECT 1570.370 0.000 1570.510 0.420 ;
    END
  END w0_wd_in[398]
  PIN w0_wd_in[399]
    DIRECTION OUTPUT ;
    USE SIGNAL ;
    SHAPE ABUTMENT ;
    PORT
      LAYER met2 ;
      RECT 1581.410 0.000 1581.550 0.420 ;
    END
  END w0_wd_in[399]
  PIN w0_wd_in[400]
    DIRECTION OUTPUT ;
    USE SIGNAL ;
    SHAPE ABUTMENT ;
    PORT
      LAYER met2 ;
      RECT 1592.450 0.000 1592.590 0.420 ;
    END
  END w0_wd_in[400]
  PIN w0_wd_in[401]
    DIRECTION OUTPUT ;
    USE SIGNAL ;
    SHAPE ABUTMENT ;
    PORT
      LAYER met2 ;
      RECT 1603.490 0.000 1603.630 0.420 ;
    END
  END w0_wd_in[401]
  PIN w0_wd_in[402]
    DIRECTION OUTPUT ;
    USE SIGNAL ;
    SHAPE ABUTMENT ;
    PORT
      LAYER met2 ;
      RECT 1614.530 0.000 1614.670 0.420 ;
    END
  END w0_wd_in[402]
  PIN w0_wd_in[403]
    DIRECTION OUTPUT ;
    USE SIGNAL ;
    SHAPE ABUTMENT ;
    PORT
      LAYER met2 ;
      RECT 1625.570 0.000 1625.710 0.420 ;
    END
  END w0_wd_in[403]
  PIN w0_wd_in[404]
    DIRECTION OUTPUT ;
    USE SIGNAL ;
    SHAPE ABUTMENT ;
    PORT
      LAYER met2 ;
      RECT 1636.610 0.000 1636.750 0.420 ;
    END
  END w0_wd_in[404]
  PIN w0_wd_in[405]
    DIRECTION OUTPUT ;
    USE SIGNAL ;
    SHAPE ABUTMENT ;
    PORT
      LAYER met2 ;
      RECT 1647.650 0.000 1647.790 0.420 ;
    END
  END w0_wd_in[405]
  PIN w0_wd_in[406]
    DIRECTION OUTPUT ;
    USE SIGNAL ;
    SHAPE ABUTMENT ;
    PORT
      LAYER met2 ;
      RECT 1658.690 0.000 1658.830 0.420 ;
    END
  END w0_wd_in[406]
  PIN w0_wd_in[407]
    DIRECTION OUTPUT ;
    USE SIGNAL ;
    SHAPE ABUTMENT ;
    PORT
      LAYER met2 ;
      RECT 1669.730 0.000 1669.870 0.420 ;
    END
  END w0_wd_in[407]
  PIN w0_wd_in[408]
    DIRECTION OUTPUT ;
    USE SIGNAL ;
    SHAPE ABUTMENT ;
    PORT
      LAYER met2 ;
      RECT 1680.770 0.000 1680.910 0.420 ;
    END
  END w0_wd_in[408]
  PIN w0_wd_in[409]
    DIRECTION OUTPUT ;
    USE SIGNAL ;
    SHAPE ABUTMENT ;
    PORT
      LAYER met2 ;
      RECT 1691.810 0.000 1691.950 0.420 ;
    END
  END w0_wd_in[409]
  PIN w0_wd_in[410]
    DIRECTION OUTPUT ;
    USE SIGNAL ;
    SHAPE ABUTMENT ;
    PORT
      LAYER met2 ;
      RECT 1702.850 0.000 1702.990 0.420 ;
    END
  END w0_wd_in[410]
  PIN w0_wd_in[411]
    DIRECTION OUTPUT ;
    USE SIGNAL ;
    SHAPE ABUTMENT ;
    PORT
      LAYER met2 ;
      RECT 1713.890 0.000 1714.030 0.420 ;
    END
  END w0_wd_in[411]
  PIN w0_wd_in[412]
    DIRECTION OUTPUT ;
    USE SIGNAL ;
    SHAPE ABUTMENT ;
    PORT
      LAYER met2 ;
      RECT 1724.930 0.000 1725.070 0.420 ;
    END
  END w0_wd_in[412]
  PIN w0_wd_in[413]
    DIRECTION OUTPUT ;
    USE SIGNAL ;
    SHAPE ABUTMENT ;
    PORT
      LAYER met2 ;
      RECT 1735.970 0.000 1736.110 0.420 ;
    END
  END w0_wd_in[413]
  PIN w0_wd_in[414]
    DIRECTION OUTPUT ;
    USE SIGNAL ;
    SHAPE ABUTMENT ;
    PORT
      LAYER met2 ;
      RECT 1747.010 0.000 1747.150 0.420 ;
    END
  END w0_wd_in[414]
  PIN w0_wd_in[415]
    DIRECTION OUTPUT ;
    USE SIGNAL ;
    SHAPE ABUTMENT ;
    PORT
      LAYER met2 ;
      RECT 1758.050 0.000 1758.190 0.420 ;
    END
  END w0_wd_in[415]
  PIN w0_wd_in[416]
    DIRECTION OUTPUT ;
    USE SIGNAL ;
    SHAPE ABUTMENT ;
    PORT
      LAYER met2 ;
      RECT 1769.090 0.000 1769.230 0.420 ;
    END
  END w0_wd_in[416]
  PIN w0_wd_in[417]
    DIRECTION OUTPUT ;
    USE SIGNAL ;
    SHAPE ABUTMENT ;
    PORT
      LAYER met2 ;
      RECT 1780.130 0.000 1780.270 0.420 ;
    END
  END w0_wd_in[417]
  PIN w0_wd_in[418]
    DIRECTION OUTPUT ;
    USE SIGNAL ;
    SHAPE ABUTMENT ;
    PORT
      LAYER met2 ;
      RECT 1791.170 0.000 1791.310 0.420 ;
    END
  END w0_wd_in[418]
  PIN w0_wd_in[419]
    DIRECTION OUTPUT ;
    USE SIGNAL ;
    SHAPE ABUTMENT ;
    PORT
      LAYER met2 ;
      RECT 1802.210 0.000 1802.350 0.420 ;
    END
  END w0_wd_in[419]
  PIN w0_wd_in[420]
    DIRECTION OUTPUT ;
    USE SIGNAL ;
    SHAPE ABUTMENT ;
    PORT
      LAYER met2 ;
      RECT 1813.250 0.000 1813.390 0.420 ;
    END
  END w0_wd_in[420]
  PIN w0_wd_in[421]
    DIRECTION OUTPUT ;
    USE SIGNAL ;
    SHAPE ABUTMENT ;
    PORT
      LAYER met2 ;
      RECT 1824.290 0.000 1824.430 0.420 ;
    END
  END w0_wd_in[421]
  PIN w0_wd_in[422]
    DIRECTION OUTPUT ;
    USE SIGNAL ;
    SHAPE ABUTMENT ;
    PORT
      LAYER met2 ;
      RECT 1835.330 0.000 1835.470 0.420 ;
    END
  END w0_wd_in[422]
  PIN w0_wd_in[423]
    DIRECTION OUTPUT ;
    USE SIGNAL ;
    SHAPE ABUTMENT ;
    PORT
      LAYER met2 ;
      RECT 1846.370 0.000 1846.510 0.420 ;
    END
  END w0_wd_in[423]
  PIN w0_wd_in[424]
    DIRECTION OUTPUT ;
    USE SIGNAL ;
    SHAPE ABUTMENT ;
    PORT
      LAYER met2 ;
      RECT 1857.410 0.000 1857.550 0.420 ;
    END
  END w0_wd_in[424]
  PIN w0_wd_in[425]
    DIRECTION OUTPUT ;
    USE SIGNAL ;
    SHAPE ABUTMENT ;
    PORT
      LAYER met2 ;
      RECT 1868.450 0.000 1868.590 0.420 ;
    END
  END w0_wd_in[425]
  PIN w0_wd_in[426]
    DIRECTION OUTPUT ;
    USE SIGNAL ;
    SHAPE ABUTMENT ;
    PORT
      LAYER met2 ;
      RECT 1879.490 0.000 1879.630 0.420 ;
    END
  END w0_wd_in[426]
  PIN w0_wd_in[427]
    DIRECTION OUTPUT ;
    USE SIGNAL ;
    SHAPE ABUTMENT ;
    PORT
      LAYER met2 ;
      RECT 1890.530 0.000 1890.670 0.420 ;
    END
  END w0_wd_in[427]
  PIN w0_wd_in[428]
    DIRECTION OUTPUT ;
    USE SIGNAL ;
    SHAPE ABUTMENT ;
    PORT
      LAYER met2 ;
      RECT 1901.570 0.000 1901.710 0.420 ;
    END
  END w0_wd_in[428]
  PIN w0_wd_in[429]
    DIRECTION OUTPUT ;
    USE SIGNAL ;
    SHAPE ABUTMENT ;
    PORT
      LAYER met2 ;
      RECT 1912.610 0.000 1912.750 0.420 ;
    END
  END w0_wd_in[429]
  PIN w0_wd_in[430]
    DIRECTION OUTPUT ;
    USE SIGNAL ;
    SHAPE ABUTMENT ;
    PORT
      LAYER met2 ;
      RECT 1923.650 0.000 1923.790 0.420 ;
    END
  END w0_wd_in[430]
  PIN w0_wd_in[431]
    DIRECTION OUTPUT ;
    USE SIGNAL ;
    SHAPE ABUTMENT ;
    PORT
      LAYER met2 ;
      RECT 1934.690 0.000 1934.830 0.420 ;
    END
  END w0_wd_in[431]
  PIN w0_wd_in[432]
    DIRECTION OUTPUT ;
    USE SIGNAL ;
    SHAPE ABUTMENT ;
    PORT
      LAYER met2 ;
      RECT 1945.730 0.000 1945.870 0.420 ;
    END
  END w0_wd_in[432]
  PIN w0_wd_in[433]
    DIRECTION OUTPUT ;
    USE SIGNAL ;
    SHAPE ABUTMENT ;
    PORT
      LAYER met2 ;
      RECT 1956.770 0.000 1956.910 0.420 ;
    END
  END w0_wd_in[433]
  PIN w0_wd_in[434]
    DIRECTION OUTPUT ;
    USE SIGNAL ;
    SHAPE ABUTMENT ;
    PORT
      LAYER met2 ;
      RECT 1967.810 0.000 1967.950 0.420 ;
    END
  END w0_wd_in[434]
  PIN w0_wd_in[435]
    DIRECTION OUTPUT ;
    USE SIGNAL ;
    SHAPE ABUTMENT ;
    PORT
      LAYER met2 ;
      RECT 1978.850 0.000 1978.990 0.420 ;
    END
  END w0_wd_in[435]
  PIN w0_wd_in[436]
    DIRECTION OUTPUT ;
    USE SIGNAL ;
    SHAPE ABUTMENT ;
    PORT
      LAYER met2 ;
      RECT 1989.890 0.000 1990.030 0.420 ;
    END
  END w0_wd_in[436]
  PIN w0_wd_in[437]
    DIRECTION OUTPUT ;
    USE SIGNAL ;
    SHAPE ABUTMENT ;
    PORT
      LAYER met2 ;
      RECT 2000.930 0.000 2001.070 0.420 ;
    END
  END w0_wd_in[437]
  PIN w0_wd_in[438]
    DIRECTION OUTPUT ;
    USE SIGNAL ;
    SHAPE ABUTMENT ;
    PORT
      LAYER met2 ;
      RECT 2011.970 0.000 2012.110 0.420 ;
    END
  END w0_wd_in[438]
  PIN w0_wd_in[439]
    DIRECTION OUTPUT ;
    USE SIGNAL ;
    SHAPE ABUTMENT ;
    PORT
      LAYER met2 ;
      RECT 2023.010 0.000 2023.150 0.420 ;
    END
  END w0_wd_in[439]
  PIN w0_wd_in[440]
    DIRECTION OUTPUT ;
    USE SIGNAL ;
    SHAPE ABUTMENT ;
    PORT
      LAYER met2 ;
      RECT 2034.050 0.000 2034.190 0.420 ;
    END
  END w0_wd_in[440]
  PIN w0_wd_in[441]
    DIRECTION OUTPUT ;
    USE SIGNAL ;
    SHAPE ABUTMENT ;
    PORT
      LAYER met2 ;
      RECT 2045.090 0.000 2045.230 0.420 ;
    END
  END w0_wd_in[441]
  PIN w0_wd_in[442]
    DIRECTION OUTPUT ;
    USE SIGNAL ;
    SHAPE ABUTMENT ;
    PORT
      LAYER met2 ;
      RECT 2056.130 0.000 2056.270 0.420 ;
    END
  END w0_wd_in[442]
  PIN w0_wd_in[443]
    DIRECTION OUTPUT ;
    USE SIGNAL ;
    SHAPE ABUTMENT ;
    PORT
      LAYER met2 ;
      RECT 2067.170 0.000 2067.310 0.420 ;
    END
  END w0_wd_in[443]
  PIN w0_wd_in[444]
    DIRECTION OUTPUT ;
    USE SIGNAL ;
    SHAPE ABUTMENT ;
    PORT
      LAYER met2 ;
      RECT 2078.210 0.000 2078.350 0.420 ;
    END
  END w0_wd_in[444]
  PIN w0_wd_in[445]
    DIRECTION OUTPUT ;
    USE SIGNAL ;
    SHAPE ABUTMENT ;
    PORT
      LAYER met2 ;
      RECT 2089.250 0.000 2089.390 0.420 ;
    END
  END w0_wd_in[445]
  PIN w0_wd_in[446]
    DIRECTION OUTPUT ;
    USE SIGNAL ;
    SHAPE ABUTMENT ;
    PORT
      LAYER met2 ;
      RECT 2100.290 0.000 2100.430 0.420 ;
    END
  END w0_wd_in[446]
  PIN w0_wd_in[447]
    DIRECTION OUTPUT ;
    USE SIGNAL ;
    SHAPE ABUTMENT ;
    PORT
      LAYER met2 ;
      RECT 2111.330 0.000 2111.470 0.420 ;
    END
  END w0_wd_in[447]
  PIN w0_wd_in[448]
    DIRECTION OUTPUT ;
    USE SIGNAL ;
    SHAPE ABUTMENT ;
    PORT
      LAYER met2 ;
      RECT 2122.370 0.000 2122.510 0.420 ;
    END
  END w0_wd_in[448]
  PIN w0_wd_in[449]
    DIRECTION OUTPUT ;
    USE SIGNAL ;
    SHAPE ABUTMENT ;
    PORT
      LAYER met2 ;
      RECT 2133.410 0.000 2133.550 0.420 ;
    END
  END w0_wd_in[449]
  PIN w0_wd_in[450]
    DIRECTION OUTPUT ;
    USE SIGNAL ;
    SHAPE ABUTMENT ;
    PORT
      LAYER met2 ;
      RECT 2144.450 0.000 2144.590 0.420 ;
    END
  END w0_wd_in[450]
  PIN w0_wd_in[451]
    DIRECTION OUTPUT ;
    USE SIGNAL ;
    SHAPE ABUTMENT ;
    PORT
      LAYER met2 ;
      RECT 2155.490 0.000 2155.630 0.420 ;
    END
  END w0_wd_in[451]
  PIN w0_wd_in[452]
    DIRECTION OUTPUT ;
    USE SIGNAL ;
    SHAPE ABUTMENT ;
    PORT
      LAYER met2 ;
      RECT 2166.530 0.000 2166.670 0.420 ;
    END
  END w0_wd_in[452]
  PIN w0_wd_in[453]
    DIRECTION OUTPUT ;
    USE SIGNAL ;
    SHAPE ABUTMENT ;
    PORT
      LAYER met2 ;
      RECT 2177.570 0.000 2177.710 0.420 ;
    END
  END w0_wd_in[453]
  PIN w0_wd_in[454]
    DIRECTION OUTPUT ;
    USE SIGNAL ;
    SHAPE ABUTMENT ;
    PORT
      LAYER met2 ;
      RECT 2188.610 0.000 2188.750 0.420 ;
    END
  END w0_wd_in[454]
  PIN w0_wd_in[455]
    DIRECTION OUTPUT ;
    USE SIGNAL ;
    SHAPE ABUTMENT ;
    PORT
      LAYER met2 ;
      RECT 2199.650 0.000 2199.790 0.420 ;
    END
  END w0_wd_in[455]
  PIN w0_wd_in[456]
    DIRECTION OUTPUT ;
    USE SIGNAL ;
    SHAPE ABUTMENT ;
    PORT
      LAYER met2 ;
      RECT 2210.690 0.000 2210.830 0.420 ;
    END
  END w0_wd_in[456]
  PIN w0_wd_in[457]
    DIRECTION OUTPUT ;
    USE SIGNAL ;
    SHAPE ABUTMENT ;
    PORT
      LAYER met2 ;
      RECT 2221.730 0.000 2221.870 0.420 ;
    END
  END w0_wd_in[457]
  PIN w0_wd_in[458]
    DIRECTION OUTPUT ;
    USE SIGNAL ;
    SHAPE ABUTMENT ;
    PORT
      LAYER met2 ;
      RECT 2232.770 0.000 2232.910 0.420 ;
    END
  END w0_wd_in[458]
  PIN w0_wd_in[459]
    DIRECTION OUTPUT ;
    USE SIGNAL ;
    SHAPE ABUTMENT ;
    PORT
      LAYER met2 ;
      RECT 2243.810 0.000 2243.950 0.420 ;
    END
  END w0_wd_in[459]
  PIN w0_wd_in[460]
    DIRECTION OUTPUT ;
    USE SIGNAL ;
    SHAPE ABUTMENT ;
    PORT
      LAYER met2 ;
      RECT 2254.850 0.000 2254.990 0.420 ;
    END
  END w0_wd_in[460]
  PIN w0_wd_in[461]
    DIRECTION OUTPUT ;
    USE SIGNAL ;
    SHAPE ABUTMENT ;
    PORT
      LAYER met2 ;
      RECT 2265.890 0.000 2266.030 0.420 ;
    END
  END w0_wd_in[461]
  PIN w0_wd_in[462]
    DIRECTION OUTPUT ;
    USE SIGNAL ;
    SHAPE ABUTMENT ;
    PORT
      LAYER met2 ;
      RECT 2276.930 0.000 2277.070 0.420 ;
    END
  END w0_wd_in[462]
  PIN w0_wd_in[463]
    DIRECTION OUTPUT ;
    USE SIGNAL ;
    SHAPE ABUTMENT ;
    PORT
      LAYER met2 ;
      RECT 2287.970 0.000 2288.110 0.420 ;
    END
  END w0_wd_in[463]
  PIN w0_wd_in[464]
    DIRECTION OUTPUT ;
    USE SIGNAL ;
    SHAPE ABUTMENT ;
    PORT
      LAYER met2 ;
      RECT 2299.010 0.000 2299.150 0.420 ;
    END
  END w0_wd_in[464]
  PIN w0_wd_in[465]
    DIRECTION OUTPUT ;
    USE SIGNAL ;
    SHAPE ABUTMENT ;
    PORT
      LAYER met2 ;
      RECT 2310.050 0.000 2310.190 0.420 ;
    END
  END w0_wd_in[465]
  PIN w0_wd_in[466]
    DIRECTION OUTPUT ;
    USE SIGNAL ;
    SHAPE ABUTMENT ;
    PORT
      LAYER met2 ;
      RECT 2321.090 0.000 2321.230 0.420 ;
    END
  END w0_wd_in[466]
  PIN w0_wd_in[467]
    DIRECTION OUTPUT ;
    USE SIGNAL ;
    SHAPE ABUTMENT ;
    PORT
      LAYER met2 ;
      RECT 2332.130 0.000 2332.270 0.420 ;
    END
  END w0_wd_in[467]
  PIN w0_wd_in[468]
    DIRECTION OUTPUT ;
    USE SIGNAL ;
    SHAPE ABUTMENT ;
    PORT
      LAYER met2 ;
      RECT 2343.170 0.000 2343.310 0.420 ;
    END
  END w0_wd_in[468]
  PIN w0_wd_in[469]
    DIRECTION OUTPUT ;
    USE SIGNAL ;
    SHAPE ABUTMENT ;
    PORT
      LAYER met2 ;
      RECT 2354.210 0.000 2354.350 0.420 ;
    END
  END w0_wd_in[469]
  PIN w0_wd_in[470]
    DIRECTION OUTPUT ;
    USE SIGNAL ;
    SHAPE ABUTMENT ;
    PORT
      LAYER met2 ;
      RECT 2365.250 0.000 2365.390 0.420 ;
    END
  END w0_wd_in[470]
  PIN w0_wd_in[471]
    DIRECTION OUTPUT ;
    USE SIGNAL ;
    SHAPE ABUTMENT ;
    PORT
      LAYER met2 ;
      RECT 2376.290 0.000 2376.430 0.420 ;
    END
  END w0_wd_in[471]
  PIN w0_wd_in[472]
    DIRECTION OUTPUT ;
    USE SIGNAL ;
    SHAPE ABUTMENT ;
    PORT
      LAYER met2 ;
      RECT 2387.330 0.000 2387.470 0.420 ;
    END
  END w0_wd_in[472]
  PIN w0_wd_in[473]
    DIRECTION OUTPUT ;
    USE SIGNAL ;
    SHAPE ABUTMENT ;
    PORT
      LAYER met2 ;
      RECT 2398.370 0.000 2398.510 0.420 ;
    END
  END w0_wd_in[473]
  PIN w0_wd_in[474]
    DIRECTION OUTPUT ;
    USE SIGNAL ;
    SHAPE ABUTMENT ;
    PORT
      LAYER met2 ;
      RECT 2409.410 0.000 2409.550 0.420 ;
    END
  END w0_wd_in[474]
  PIN w0_wd_in[475]
    DIRECTION OUTPUT ;
    USE SIGNAL ;
    SHAPE ABUTMENT ;
    PORT
      LAYER met2 ;
      RECT 2420.450 0.000 2420.590 0.420 ;
    END
  END w0_wd_in[475]
  PIN w0_wd_in[476]
    DIRECTION OUTPUT ;
    USE SIGNAL ;
    SHAPE ABUTMENT ;
    PORT
      LAYER met2 ;
      RECT 2431.490 0.000 2431.630 0.420 ;
    END
  END w0_wd_in[476]
  PIN w0_wd_in[477]
    DIRECTION OUTPUT ;
    USE SIGNAL ;
    SHAPE ABUTMENT ;
    PORT
      LAYER met2 ;
      RECT 2442.530 0.000 2442.670 0.420 ;
    END
  END w0_wd_in[477]
  PIN w0_wd_in[478]
    DIRECTION OUTPUT ;
    USE SIGNAL ;
    SHAPE ABUTMENT ;
    PORT
      LAYER met2 ;
      RECT 2453.570 0.000 2453.710 0.420 ;
    END
  END w0_wd_in[478]
  PIN w0_wd_in[479]
    DIRECTION OUTPUT ;
    USE SIGNAL ;
    SHAPE ABUTMENT ;
    PORT
      LAYER met2 ;
      RECT 2464.610 0.000 2464.750 0.420 ;
    END
  END w0_wd_in[479]
  PIN w0_wd_in[480]
    DIRECTION OUTPUT ;
    USE SIGNAL ;
    SHAPE ABUTMENT ;
    PORT
      LAYER met2 ;
      RECT 2475.650 0.000 2475.790 0.420 ;
    END
  END w0_wd_in[480]
  PIN w0_wd_in[481]
    DIRECTION OUTPUT ;
    USE SIGNAL ;
    SHAPE ABUTMENT ;
    PORT
      LAYER met2 ;
      RECT 2486.690 0.000 2486.830 0.420 ;
    END
  END w0_wd_in[481]
  PIN w0_wd_in[482]
    DIRECTION OUTPUT ;
    USE SIGNAL ;
    SHAPE ABUTMENT ;
    PORT
      LAYER met2 ;
      RECT 2497.730 0.000 2497.870 0.420 ;
    END
  END w0_wd_in[482]
  PIN w0_wd_in[483]
    DIRECTION OUTPUT ;
    USE SIGNAL ;
    SHAPE ABUTMENT ;
    PORT
      LAYER met2 ;
      RECT 2508.770 0.000 2508.910 0.420 ;
    END
  END w0_wd_in[483]
  PIN w0_wd_in[484]
    DIRECTION OUTPUT ;
    USE SIGNAL ;
    SHAPE ABUTMENT ;
    PORT
      LAYER met2 ;
      RECT 2519.810 0.000 2519.950 0.420 ;
    END
  END w0_wd_in[484]
  PIN w0_wd_in[485]
    DIRECTION OUTPUT ;
    USE SIGNAL ;
    SHAPE ABUTMENT ;
    PORT
      LAYER met2 ;
      RECT 2530.850 0.000 2530.990 0.420 ;
    END
  END w0_wd_in[485]
  PIN w0_wd_in[486]
    DIRECTION OUTPUT ;
    USE SIGNAL ;
    SHAPE ABUTMENT ;
    PORT
      LAYER met2 ;
      RECT 2541.890 0.000 2542.030 0.420 ;
    END
  END w0_wd_in[486]
  PIN w0_wd_in[487]
    DIRECTION OUTPUT ;
    USE SIGNAL ;
    SHAPE ABUTMENT ;
    PORT
      LAYER met2 ;
      RECT 2552.930 0.000 2553.070 0.420 ;
    END
  END w0_wd_in[487]
  PIN w0_wd_in[488]
    DIRECTION OUTPUT ;
    USE SIGNAL ;
    SHAPE ABUTMENT ;
    PORT
      LAYER met2 ;
      RECT 2563.970 0.000 2564.110 0.420 ;
    END
  END w0_wd_in[488]
  PIN w0_wd_in[489]
    DIRECTION OUTPUT ;
    USE SIGNAL ;
    SHAPE ABUTMENT ;
    PORT
      LAYER met2 ;
      RECT 2575.010 0.000 2575.150 0.420 ;
    END
  END w0_wd_in[489]
  PIN w0_wd_in[490]
    DIRECTION OUTPUT ;
    USE SIGNAL ;
    SHAPE ABUTMENT ;
    PORT
      LAYER met2 ;
      RECT 2586.050 0.000 2586.190 0.420 ;
    END
  END w0_wd_in[490]
  PIN w0_wd_in[491]
    DIRECTION OUTPUT ;
    USE SIGNAL ;
    SHAPE ABUTMENT ;
    PORT
      LAYER met2 ;
      RECT 2597.090 0.000 2597.230 0.420 ;
    END
  END w0_wd_in[491]
  PIN w0_wd_in[492]
    DIRECTION OUTPUT ;
    USE SIGNAL ;
    SHAPE ABUTMENT ;
    PORT
      LAYER met2 ;
      RECT 2608.130 0.000 2608.270 0.420 ;
    END
  END w0_wd_in[492]
  PIN w0_wd_in[493]
    DIRECTION OUTPUT ;
    USE SIGNAL ;
    SHAPE ABUTMENT ;
    PORT
      LAYER met2 ;
      RECT 2619.170 0.000 2619.310 0.420 ;
    END
  END w0_wd_in[493]
  PIN w0_wd_in[494]
    DIRECTION OUTPUT ;
    USE SIGNAL ;
    SHAPE ABUTMENT ;
    PORT
      LAYER met2 ;
      RECT 2630.210 0.000 2630.350 0.420 ;
    END
  END w0_wd_in[494]
  PIN w0_wd_in[495]
    DIRECTION OUTPUT ;
    USE SIGNAL ;
    SHAPE ABUTMENT ;
    PORT
      LAYER met2 ;
      RECT 2641.250 0.000 2641.390 0.420 ;
    END
  END w0_wd_in[495]
  PIN w0_wd_in[496]
    DIRECTION OUTPUT ;
    USE SIGNAL ;
    SHAPE ABUTMENT ;
    PORT
      LAYER met2 ;
      RECT 2652.290 0.000 2652.430 0.420 ;
    END
  END w0_wd_in[496]
  PIN w0_wd_in[497]
    DIRECTION OUTPUT ;
    USE SIGNAL ;
    SHAPE ABUTMENT ;
    PORT
      LAYER met2 ;
      RECT 2663.330 0.000 2663.470 0.420 ;
    END
  END w0_wd_in[497]
  PIN w0_wd_in[498]
    DIRECTION OUTPUT ;
    USE SIGNAL ;
    SHAPE ABUTMENT ;
    PORT
      LAYER met2 ;
      RECT 2674.370 0.000 2674.510 0.420 ;
    END
  END w0_wd_in[498]
  PIN w0_wd_in[499]
    DIRECTION OUTPUT ;
    USE SIGNAL ;
    SHAPE ABUTMENT ;
    PORT
      LAYER met2 ;
      RECT 2685.410 0.000 2685.550 0.420 ;
    END
  END w0_wd_in[499]
  PIN w0_wd_in[500]
    DIRECTION OUTPUT ;
    USE SIGNAL ;
    SHAPE ABUTMENT ;
    PORT
      LAYER met2 ;
      RECT 2696.450 0.000 2696.590 0.420 ;
    END
  END w0_wd_in[500]
  PIN w0_wd_in[501]
    DIRECTION OUTPUT ;
    USE SIGNAL ;
    SHAPE ABUTMENT ;
    PORT
      LAYER met2 ;
      RECT 2707.490 0.000 2707.630 0.420 ;
    END
  END w0_wd_in[501]
  PIN w0_wd_in[502]
    DIRECTION OUTPUT ;
    USE SIGNAL ;
    SHAPE ABUTMENT ;
    PORT
      LAYER met2 ;
      RECT 2718.530 0.000 2718.670 0.420 ;
    END
  END w0_wd_in[502]
  PIN w0_wd_in[503]
    DIRECTION OUTPUT ;
    USE SIGNAL ;
    SHAPE ABUTMENT ;
    PORT
      LAYER met2 ;
      RECT 2729.570 0.000 2729.710 0.420 ;
    END
  END w0_wd_in[503]
  PIN w0_wd_in[504]
    DIRECTION OUTPUT ;
    USE SIGNAL ;
    SHAPE ABUTMENT ;
    PORT
      LAYER met2 ;
      RECT 2740.610 0.000 2740.750 0.420 ;
    END
  END w0_wd_in[504]
  PIN w0_wd_in[505]
    DIRECTION OUTPUT ;
    USE SIGNAL ;
    SHAPE ABUTMENT ;
    PORT
      LAYER met2 ;
      RECT 2751.650 0.000 2751.790 0.420 ;
    END
  END w0_wd_in[505]
  PIN w0_wd_in[506]
    DIRECTION OUTPUT ;
    USE SIGNAL ;
    SHAPE ABUTMENT ;
    PORT
      LAYER met2 ;
      RECT 2762.690 0.000 2762.830 0.420 ;
    END
  END w0_wd_in[506]
  PIN w0_wd_in[507]
    DIRECTION OUTPUT ;
    USE SIGNAL ;
    SHAPE ABUTMENT ;
    PORT
      LAYER met2 ;
      RECT 2773.730 0.000 2773.870 0.420 ;
    END
  END w0_wd_in[507]
  PIN w0_wd_in[508]
    DIRECTION OUTPUT ;
    USE SIGNAL ;
    SHAPE ABUTMENT ;
    PORT
      LAYER met2 ;
      RECT 2784.770 0.000 2784.910 0.420 ;
    END
  END w0_wd_in[508]
  PIN w0_wd_in[509]
    DIRECTION OUTPUT ;
    USE SIGNAL ;
    SHAPE ABUTMENT ;
    PORT
      LAYER met2 ;
      RECT 2795.810 0.000 2795.950 0.420 ;
    END
  END w0_wd_in[509]
  PIN w0_wd_in[510]
    DIRECTION OUTPUT ;
    USE SIGNAL ;
    SHAPE ABUTMENT ;
    PORT
      LAYER met2 ;
      RECT 2806.850 0.000 2806.990 0.420 ;
    END
  END w0_wd_in[510]
  PIN w0_wd_in[511]
    DIRECTION OUTPUT ;
    USE SIGNAL ;
    SHAPE ABUTMENT ;
    PORT
      LAYER met2 ;
      RECT 2817.890 0.000 2818.030 0.420 ;
    END
  END w0_wd_in[511]
  PIN r0_rd_out[0]
    DIRECTION OUTPUT ;
    USE SIGNAL ;
    SHAPE ABUTMENT ;
    PORT
      LAYER met2 ;
      RECT 2828.930 0.000 2829.070 0.420 ;
    END
  END r0_rd_out[0]
  PIN r0_rd_out[1]
    DIRECTION OUTPUT ;
    USE SIGNAL ;
    SHAPE ABUTMENT ;
    PORT
      LAYER met2 ;
      RECT 2839.970 0.000 2840.110 0.420 ;
    END
  END r0_rd_out[1]
  PIN r0_rd_out[2]
    DIRECTION OUTPUT ;
    USE SIGNAL ;
    SHAPE ABUTMENT ;
    PORT
      LAYER met2 ;
      RECT 2851.010 0.000 2851.150 0.420 ;
    END
  END r0_rd_out[2]
  PIN r0_rd_out[3]
    DIRECTION OUTPUT ;
    USE SIGNAL ;
    SHAPE ABUTMENT ;
    PORT
      LAYER met2 ;
      RECT 2862.050 0.000 2862.190 0.420 ;
    END
  END r0_rd_out[3]
  PIN r0_rd_out[4]
    DIRECTION OUTPUT ;
    USE SIGNAL ;
    SHAPE ABUTMENT ;
    PORT
      LAYER met2 ;
      RECT 2873.090 0.000 2873.230 0.420 ;
    END
  END r0_rd_out[4]
  PIN r0_rd_out[5]
    DIRECTION OUTPUT ;
    USE SIGNAL ;
    SHAPE ABUTMENT ;
    PORT
      LAYER met2 ;
      RECT 2884.130 0.000 2884.270 0.420 ;
    END
  END r0_rd_out[5]
  PIN r0_rd_out[6]
    DIRECTION OUTPUT ;
    USE SIGNAL ;
    SHAPE ABUTMENT ;
    PORT
      LAYER met2 ;
      RECT 2895.170 0.000 2895.310 0.420 ;
    END
  END r0_rd_out[6]
  PIN r0_rd_out[7]
    DIRECTION OUTPUT ;
    USE SIGNAL ;
    SHAPE ABUTMENT ;
    PORT
      LAYER met2 ;
      RECT 2906.210 0.000 2906.350 0.420 ;
    END
  END r0_rd_out[7]
  PIN r0_rd_out[8]
    DIRECTION OUTPUT ;
    USE SIGNAL ;
    SHAPE ABUTMENT ;
    PORT
      LAYER met2 ;
      RECT 2917.250 0.000 2917.390 0.420 ;
    END
  END r0_rd_out[8]
  PIN r0_rd_out[9]
    DIRECTION OUTPUT ;
    USE SIGNAL ;
    SHAPE ABUTMENT ;
    PORT
      LAYER met2 ;
      RECT 2928.290 0.000 2928.430 0.420 ;
    END
  END r0_rd_out[9]
  PIN r0_rd_out[10]
    DIRECTION OUTPUT ;
    USE SIGNAL ;
    SHAPE ABUTMENT ;
    PORT
      LAYER met2 ;
      RECT 2939.330 0.000 2939.470 0.420 ;
    END
  END r0_rd_out[10]
  PIN r0_rd_out[11]
    DIRECTION OUTPUT ;
    USE SIGNAL ;
    SHAPE ABUTMENT ;
    PORT
      LAYER met2 ;
      RECT 2950.370 0.000 2950.510 0.420 ;
    END
  END r0_rd_out[11]
  PIN r0_rd_out[12]
    DIRECTION OUTPUT ;
    USE SIGNAL ;
    SHAPE ABUTMENT ;
    PORT
      LAYER met2 ;
      RECT 2961.410 0.000 2961.550 0.420 ;
    END
  END r0_rd_out[12]
  PIN r0_rd_out[13]
    DIRECTION OUTPUT ;
    USE SIGNAL ;
    SHAPE ABUTMENT ;
    PORT
      LAYER met2 ;
      RECT 2972.450 0.000 2972.590 0.420 ;
    END
  END r0_rd_out[13]
  PIN r0_rd_out[14]
    DIRECTION OUTPUT ;
    USE SIGNAL ;
    SHAPE ABUTMENT ;
    PORT
      LAYER met2 ;
      RECT 2983.490 0.000 2983.630 0.420 ;
    END
  END r0_rd_out[14]
  PIN r0_rd_out[15]
    DIRECTION OUTPUT ;
    USE SIGNAL ;
    SHAPE ABUTMENT ;
    PORT
      LAYER met2 ;
      RECT 2994.530 0.000 2994.670 0.420 ;
    END
  END r0_rd_out[15]
  PIN r0_rd_out[16]
    DIRECTION OUTPUT ;
    USE SIGNAL ;
    SHAPE ABUTMENT ;
    PORT
      LAYER met2 ;
      RECT 3005.570 0.000 3005.710 0.420 ;
    END
  END r0_rd_out[16]
  PIN r0_rd_out[17]
    DIRECTION OUTPUT ;
    USE SIGNAL ;
    SHAPE ABUTMENT ;
    PORT
      LAYER met2 ;
      RECT 3016.610 0.000 3016.750 0.420 ;
    END
  END r0_rd_out[17]
  PIN r0_rd_out[18]
    DIRECTION OUTPUT ;
    USE SIGNAL ;
    SHAPE ABUTMENT ;
    PORT
      LAYER met2 ;
      RECT 3027.650 0.000 3027.790 0.420 ;
    END
  END r0_rd_out[18]
  PIN r0_rd_out[19]
    DIRECTION OUTPUT ;
    USE SIGNAL ;
    SHAPE ABUTMENT ;
    PORT
      LAYER met2 ;
      RECT 3038.690 0.000 3038.830 0.420 ;
    END
  END r0_rd_out[19]
  PIN r0_rd_out[20]
    DIRECTION OUTPUT ;
    USE SIGNAL ;
    SHAPE ABUTMENT ;
    PORT
      LAYER met2 ;
      RECT 3049.730 0.000 3049.870 0.420 ;
    END
  END r0_rd_out[20]
  PIN r0_rd_out[21]
    DIRECTION OUTPUT ;
    USE SIGNAL ;
    SHAPE ABUTMENT ;
    PORT
      LAYER met2 ;
      RECT 3060.770 0.000 3060.910 0.420 ;
    END
  END r0_rd_out[21]
  PIN r0_rd_out[22]
    DIRECTION OUTPUT ;
    USE SIGNAL ;
    SHAPE ABUTMENT ;
    PORT
      LAYER met2 ;
      RECT 3071.810 0.000 3071.950 0.420 ;
    END
  END r0_rd_out[22]
  PIN r0_rd_out[23]
    DIRECTION OUTPUT ;
    USE SIGNAL ;
    SHAPE ABUTMENT ;
    PORT
      LAYER met2 ;
      RECT 3082.850 0.000 3082.990 0.420 ;
    END
  END r0_rd_out[23]
  PIN r0_rd_out[24]
    DIRECTION OUTPUT ;
    USE SIGNAL ;
    SHAPE ABUTMENT ;
    PORT
      LAYER met2 ;
      RECT 3093.890 0.000 3094.030 0.420 ;
    END
  END r0_rd_out[24]
  PIN r0_rd_out[25]
    DIRECTION OUTPUT ;
    USE SIGNAL ;
    SHAPE ABUTMENT ;
    PORT
      LAYER met2 ;
      RECT 3104.930 0.000 3105.070 0.420 ;
    END
  END r0_rd_out[25]
  PIN r0_rd_out[26]
    DIRECTION OUTPUT ;
    USE SIGNAL ;
    SHAPE ABUTMENT ;
    PORT
      LAYER met2 ;
      RECT 3115.970 0.000 3116.110 0.420 ;
    END
  END r0_rd_out[26]
  PIN r0_rd_out[27]
    DIRECTION OUTPUT ;
    USE SIGNAL ;
    SHAPE ABUTMENT ;
    PORT
      LAYER met2 ;
      RECT 3127.010 0.000 3127.150 0.420 ;
    END
  END r0_rd_out[27]
  PIN r0_rd_out[28]
    DIRECTION OUTPUT ;
    USE SIGNAL ;
    SHAPE ABUTMENT ;
    PORT
      LAYER met2 ;
      RECT 3138.050 0.000 3138.190 0.420 ;
    END
  END r0_rd_out[28]
  PIN r0_rd_out[29]
    DIRECTION OUTPUT ;
    USE SIGNAL ;
    SHAPE ABUTMENT ;
    PORT
      LAYER met2 ;
      RECT 3149.090 0.000 3149.230 0.420 ;
    END
  END r0_rd_out[29]
  PIN r0_rd_out[30]
    DIRECTION OUTPUT ;
    USE SIGNAL ;
    SHAPE ABUTMENT ;
    PORT
      LAYER met2 ;
      RECT 3160.130 0.000 3160.270 0.420 ;
    END
  END r0_rd_out[30]
  PIN r0_rd_out[31]
    DIRECTION OUTPUT ;
    USE SIGNAL ;
    SHAPE ABUTMENT ;
    PORT
      LAYER met2 ;
      RECT 3171.170 0.000 3171.310 0.420 ;
    END
  END r0_rd_out[31]
  PIN r0_rd_out[32]
    DIRECTION OUTPUT ;
    USE SIGNAL ;
    SHAPE ABUTMENT ;
    PORT
      LAYER met2 ;
      RECT 3182.210 0.000 3182.350 0.420 ;
    END
  END r0_rd_out[32]
  PIN r0_rd_out[33]
    DIRECTION OUTPUT ;
    USE SIGNAL ;
    SHAPE ABUTMENT ;
    PORT
      LAYER met2 ;
      RECT 3193.250 0.000 3193.390 0.420 ;
    END
  END r0_rd_out[33]
  PIN r0_rd_out[34]
    DIRECTION OUTPUT ;
    USE SIGNAL ;
    SHAPE ABUTMENT ;
    PORT
      LAYER met2 ;
      RECT 3204.290 0.000 3204.430 0.420 ;
    END
  END r0_rd_out[34]
  PIN r0_rd_out[35]
    DIRECTION OUTPUT ;
    USE SIGNAL ;
    SHAPE ABUTMENT ;
    PORT
      LAYER met2 ;
      RECT 3215.330 0.000 3215.470 0.420 ;
    END
  END r0_rd_out[35]
  PIN r0_rd_out[36]
    DIRECTION OUTPUT ;
    USE SIGNAL ;
    SHAPE ABUTMENT ;
    PORT
      LAYER met2 ;
      RECT 3226.370 0.000 3226.510 0.420 ;
    END
  END r0_rd_out[36]
  PIN r0_rd_out[37]
    DIRECTION OUTPUT ;
    USE SIGNAL ;
    SHAPE ABUTMENT ;
    PORT
      LAYER met2 ;
      RECT 3237.410 0.000 3237.550 0.420 ;
    END
  END r0_rd_out[37]
  PIN r0_rd_out[38]
    DIRECTION OUTPUT ;
    USE SIGNAL ;
    SHAPE ABUTMENT ;
    PORT
      LAYER met2 ;
      RECT 3248.450 0.000 3248.590 0.420 ;
    END
  END r0_rd_out[38]
  PIN r0_rd_out[39]
    DIRECTION OUTPUT ;
    USE SIGNAL ;
    SHAPE ABUTMENT ;
    PORT
      LAYER met2 ;
      RECT 3259.490 0.000 3259.630 0.420 ;
    END
  END r0_rd_out[39]
  PIN r0_rd_out[40]
    DIRECTION OUTPUT ;
    USE SIGNAL ;
    SHAPE ABUTMENT ;
    PORT
      LAYER met2 ;
      RECT 3270.530 0.000 3270.670 0.420 ;
    END
  END r0_rd_out[40]
  PIN r0_rd_out[41]
    DIRECTION OUTPUT ;
    USE SIGNAL ;
    SHAPE ABUTMENT ;
    PORT
      LAYER met2 ;
      RECT 3281.570 0.000 3281.710 0.420 ;
    END
  END r0_rd_out[41]
  PIN r0_rd_out[42]
    DIRECTION OUTPUT ;
    USE SIGNAL ;
    SHAPE ABUTMENT ;
    PORT
      LAYER met2 ;
      RECT 3292.610 0.000 3292.750 0.420 ;
    END
  END r0_rd_out[42]
  PIN r0_rd_out[43]
    DIRECTION OUTPUT ;
    USE SIGNAL ;
    SHAPE ABUTMENT ;
    PORT
      LAYER met2 ;
      RECT 3303.650 0.000 3303.790 0.420 ;
    END
  END r0_rd_out[43]
  PIN r0_rd_out[44]
    DIRECTION OUTPUT ;
    USE SIGNAL ;
    SHAPE ABUTMENT ;
    PORT
      LAYER met2 ;
      RECT 3314.690 0.000 3314.830 0.420 ;
    END
  END r0_rd_out[44]
  PIN r0_rd_out[45]
    DIRECTION OUTPUT ;
    USE SIGNAL ;
    SHAPE ABUTMENT ;
    PORT
      LAYER met2 ;
      RECT 3325.730 0.000 3325.870 0.420 ;
    END
  END r0_rd_out[45]
  PIN r0_rd_out[46]
    DIRECTION OUTPUT ;
    USE SIGNAL ;
    SHAPE ABUTMENT ;
    PORT
      LAYER met2 ;
      RECT 3336.770 0.000 3336.910 0.420 ;
    END
  END r0_rd_out[46]
  PIN r0_rd_out[47]
    DIRECTION OUTPUT ;
    USE SIGNAL ;
    SHAPE ABUTMENT ;
    PORT
      LAYER met2 ;
      RECT 3347.810 0.000 3347.950 0.420 ;
    END
  END r0_rd_out[47]
  PIN r0_rd_out[48]
    DIRECTION OUTPUT ;
    USE SIGNAL ;
    SHAPE ABUTMENT ;
    PORT
      LAYER met2 ;
      RECT 3358.850 0.000 3358.990 0.420 ;
    END
  END r0_rd_out[48]
  PIN r0_rd_out[49]
    DIRECTION OUTPUT ;
    USE SIGNAL ;
    SHAPE ABUTMENT ;
    PORT
      LAYER met2 ;
      RECT 3369.890 0.000 3370.030 0.420 ;
    END
  END r0_rd_out[49]
  PIN r0_rd_out[50]
    DIRECTION OUTPUT ;
    USE SIGNAL ;
    SHAPE ABUTMENT ;
    PORT
      LAYER met2 ;
      RECT 3380.930 0.000 3381.070 0.420 ;
    END
  END r0_rd_out[50]
  PIN r0_rd_out[51]
    DIRECTION OUTPUT ;
    USE SIGNAL ;
    SHAPE ABUTMENT ;
    PORT
      LAYER met2 ;
      RECT 3391.970 0.000 3392.110 0.420 ;
    END
  END r0_rd_out[51]
  PIN r0_rd_out[52]
    DIRECTION OUTPUT ;
    USE SIGNAL ;
    SHAPE ABUTMENT ;
    PORT
      LAYER met2 ;
      RECT 3403.010 0.000 3403.150 0.420 ;
    END
  END r0_rd_out[52]
  PIN r0_rd_out[53]
    DIRECTION OUTPUT ;
    USE SIGNAL ;
    SHAPE ABUTMENT ;
    PORT
      LAYER met2 ;
      RECT 3414.050 0.000 3414.190 0.420 ;
    END
  END r0_rd_out[53]
  PIN r0_rd_out[54]
    DIRECTION OUTPUT ;
    USE SIGNAL ;
    SHAPE ABUTMENT ;
    PORT
      LAYER met2 ;
      RECT 3425.090 0.000 3425.230 0.420 ;
    END
  END r0_rd_out[54]
  PIN r0_rd_out[55]
    DIRECTION OUTPUT ;
    USE SIGNAL ;
    SHAPE ABUTMENT ;
    PORT
      LAYER met2 ;
      RECT 3436.130 0.000 3436.270 0.420 ;
    END
  END r0_rd_out[55]
  PIN r0_rd_out[56]
    DIRECTION OUTPUT ;
    USE SIGNAL ;
    SHAPE ABUTMENT ;
    PORT
      LAYER met2 ;
      RECT 3447.170 0.000 3447.310 0.420 ;
    END
  END r0_rd_out[56]
  PIN r0_rd_out[57]
    DIRECTION OUTPUT ;
    USE SIGNAL ;
    SHAPE ABUTMENT ;
    PORT
      LAYER met2 ;
      RECT 3458.210 0.000 3458.350 0.420 ;
    END
  END r0_rd_out[57]
  PIN r0_rd_out[58]
    DIRECTION OUTPUT ;
    USE SIGNAL ;
    SHAPE ABUTMENT ;
    PORT
      LAYER met2 ;
      RECT 3469.250 0.000 3469.390 0.420 ;
    END
  END r0_rd_out[58]
  PIN r0_rd_out[59]
    DIRECTION OUTPUT ;
    USE SIGNAL ;
    SHAPE ABUTMENT ;
    PORT
      LAYER met2 ;
      RECT 3480.290 0.000 3480.430 0.420 ;
    END
  END r0_rd_out[59]
  PIN r0_rd_out[60]
    DIRECTION OUTPUT ;
    USE SIGNAL ;
    SHAPE ABUTMENT ;
    PORT
      LAYER met2 ;
      RECT 3491.330 0.000 3491.470 0.420 ;
    END
  END r0_rd_out[60]
  PIN r0_rd_out[61]
    DIRECTION OUTPUT ;
    USE SIGNAL ;
    SHAPE ABUTMENT ;
    PORT
      LAYER met2 ;
      RECT 3502.370 0.000 3502.510 0.420 ;
    END
  END r0_rd_out[61]
  PIN r0_rd_out[62]
    DIRECTION OUTPUT ;
    USE SIGNAL ;
    SHAPE ABUTMENT ;
    PORT
      LAYER met2 ;
      RECT 3513.410 0.000 3513.550 0.420 ;
    END
  END r0_rd_out[62]
  PIN r0_rd_out[63]
    DIRECTION OUTPUT ;
    USE SIGNAL ;
    SHAPE ABUTMENT ;
    PORT
      LAYER met2 ;
      RECT 3524.450 0.000 3524.590 0.420 ;
    END
  END r0_rd_out[63]
  PIN r0_rd_out[64]
    DIRECTION OUTPUT ;
    USE SIGNAL ;
    SHAPE ABUTMENT ;
    PORT
      LAYER met2 ;
      RECT 3535.490 0.000 3535.630 0.420 ;
    END
  END r0_rd_out[64]
  PIN r0_rd_out[65]
    DIRECTION OUTPUT ;
    USE SIGNAL ;
    SHAPE ABUTMENT ;
    PORT
      LAYER met2 ;
      RECT 3546.530 0.000 3546.670 0.420 ;
    END
  END r0_rd_out[65]
  PIN r0_rd_out[66]
    DIRECTION OUTPUT ;
    USE SIGNAL ;
    SHAPE ABUTMENT ;
    PORT
      LAYER met2 ;
      RECT 3557.570 0.000 3557.710 0.420 ;
    END
  END r0_rd_out[66]
  PIN r0_rd_out[67]
    DIRECTION OUTPUT ;
    USE SIGNAL ;
    SHAPE ABUTMENT ;
    PORT
      LAYER met2 ;
      RECT 3568.610 0.000 3568.750 0.420 ;
    END
  END r0_rd_out[67]
  PIN r0_rd_out[68]
    DIRECTION OUTPUT ;
    USE SIGNAL ;
    SHAPE ABUTMENT ;
    PORT
      LAYER met2 ;
      RECT 3579.650 0.000 3579.790 0.420 ;
    END
  END r0_rd_out[68]
  PIN r0_rd_out[69]
    DIRECTION OUTPUT ;
    USE SIGNAL ;
    SHAPE ABUTMENT ;
    PORT
      LAYER met2 ;
      RECT 3590.690 0.000 3590.830 0.420 ;
    END
  END r0_rd_out[69]
  PIN r0_rd_out[70]
    DIRECTION OUTPUT ;
    USE SIGNAL ;
    SHAPE ABUTMENT ;
    PORT
      LAYER met2 ;
      RECT 3601.730 0.000 3601.870 0.420 ;
    END
  END r0_rd_out[70]
  PIN r0_rd_out[71]
    DIRECTION OUTPUT ;
    USE SIGNAL ;
    SHAPE ABUTMENT ;
    PORT
      LAYER met2 ;
      RECT 3612.770 0.000 3612.910 0.420 ;
    END
  END r0_rd_out[71]
  PIN r0_rd_out[72]
    DIRECTION OUTPUT ;
    USE SIGNAL ;
    SHAPE ABUTMENT ;
    PORT
      LAYER met2 ;
      RECT 3623.810 0.000 3623.950 0.420 ;
    END
  END r0_rd_out[72]
  PIN r0_rd_out[73]
    DIRECTION OUTPUT ;
    USE SIGNAL ;
    SHAPE ABUTMENT ;
    PORT
      LAYER met2 ;
      RECT 3634.850 0.000 3634.990 0.420 ;
    END
  END r0_rd_out[73]
  PIN r0_rd_out[74]
    DIRECTION OUTPUT ;
    USE SIGNAL ;
    SHAPE ABUTMENT ;
    PORT
      LAYER met2 ;
      RECT 3645.890 0.000 3646.030 0.420 ;
    END
  END r0_rd_out[74]
  PIN r0_rd_out[75]
    DIRECTION OUTPUT ;
    USE SIGNAL ;
    SHAPE ABUTMENT ;
    PORT
      LAYER met2 ;
      RECT 3656.930 0.000 3657.070 0.420 ;
    END
  END r0_rd_out[75]
  PIN r0_rd_out[76]
    DIRECTION OUTPUT ;
    USE SIGNAL ;
    SHAPE ABUTMENT ;
    PORT
      LAYER met2 ;
      RECT 3667.970 0.000 3668.110 0.420 ;
    END
  END r0_rd_out[76]
  PIN r0_rd_out[77]
    DIRECTION OUTPUT ;
    USE SIGNAL ;
    SHAPE ABUTMENT ;
    PORT
      LAYER met2 ;
      RECT 3679.010 0.000 3679.150 0.420 ;
    END
  END r0_rd_out[77]
  PIN r0_rd_out[78]
    DIRECTION OUTPUT ;
    USE SIGNAL ;
    SHAPE ABUTMENT ;
    PORT
      LAYER met2 ;
      RECT 3690.050 0.000 3690.190 0.420 ;
    END
  END r0_rd_out[78]
  PIN r0_rd_out[79]
    DIRECTION OUTPUT ;
    USE SIGNAL ;
    SHAPE ABUTMENT ;
    PORT
      LAYER met2 ;
      RECT 3701.090 0.000 3701.230 0.420 ;
    END
  END r0_rd_out[79]
  PIN r0_rd_out[80]
    DIRECTION OUTPUT ;
    USE SIGNAL ;
    SHAPE ABUTMENT ;
    PORT
      LAYER met2 ;
      RECT 3712.130 0.000 3712.270 0.420 ;
    END
  END r0_rd_out[80]
  PIN r0_rd_out[81]
    DIRECTION OUTPUT ;
    USE SIGNAL ;
    SHAPE ABUTMENT ;
    PORT
      LAYER met2 ;
      RECT 3723.170 0.000 3723.310 0.420 ;
    END
  END r0_rd_out[81]
  PIN r0_rd_out[82]
    DIRECTION OUTPUT ;
    USE SIGNAL ;
    SHAPE ABUTMENT ;
    PORT
      LAYER met2 ;
      RECT 3734.210 0.000 3734.350 0.420 ;
    END
  END r0_rd_out[82]
  PIN r0_rd_out[83]
    DIRECTION OUTPUT ;
    USE SIGNAL ;
    SHAPE ABUTMENT ;
    PORT
      LAYER met2 ;
      RECT 3745.250 0.000 3745.390 0.420 ;
    END
  END r0_rd_out[83]
  PIN r0_rd_out[84]
    DIRECTION OUTPUT ;
    USE SIGNAL ;
    SHAPE ABUTMENT ;
    PORT
      LAYER met2 ;
      RECT 3756.290 0.000 3756.430 0.420 ;
    END
  END r0_rd_out[84]
  PIN r0_rd_out[85]
    DIRECTION OUTPUT ;
    USE SIGNAL ;
    SHAPE ABUTMENT ;
    PORT
      LAYER met2 ;
      RECT 3767.330 0.000 3767.470 0.420 ;
    END
  END r0_rd_out[85]
  PIN r0_rd_out[86]
    DIRECTION OUTPUT ;
    USE SIGNAL ;
    SHAPE ABUTMENT ;
    PORT
      LAYER met2 ;
      RECT 3778.370 0.000 3778.510 0.420 ;
    END
  END r0_rd_out[86]
  PIN r0_rd_out[87]
    DIRECTION OUTPUT ;
    USE SIGNAL ;
    SHAPE ABUTMENT ;
    PORT
      LAYER met2 ;
      RECT 3789.410 0.000 3789.550 0.420 ;
    END
  END r0_rd_out[87]
  PIN r0_rd_out[88]
    DIRECTION OUTPUT ;
    USE SIGNAL ;
    SHAPE ABUTMENT ;
    PORT
      LAYER met2 ;
      RECT 3800.450 0.000 3800.590 0.420 ;
    END
  END r0_rd_out[88]
  PIN r0_rd_out[89]
    DIRECTION OUTPUT ;
    USE SIGNAL ;
    SHAPE ABUTMENT ;
    PORT
      LAYER met2 ;
      RECT 3811.490 0.000 3811.630 0.420 ;
    END
  END r0_rd_out[89]
  PIN r0_rd_out[90]
    DIRECTION OUTPUT ;
    USE SIGNAL ;
    SHAPE ABUTMENT ;
    PORT
      LAYER met2 ;
      RECT 3822.530 0.000 3822.670 0.420 ;
    END
  END r0_rd_out[90]
  PIN r0_rd_out[91]
    DIRECTION OUTPUT ;
    USE SIGNAL ;
    SHAPE ABUTMENT ;
    PORT
      LAYER met2 ;
      RECT 3833.570 0.000 3833.710 0.420 ;
    END
  END r0_rd_out[91]
  PIN r0_rd_out[92]
    DIRECTION OUTPUT ;
    USE SIGNAL ;
    SHAPE ABUTMENT ;
    PORT
      LAYER met2 ;
      RECT 3844.610 0.000 3844.750 0.420 ;
    END
  END r0_rd_out[92]
  PIN r0_rd_out[93]
    DIRECTION OUTPUT ;
    USE SIGNAL ;
    SHAPE ABUTMENT ;
    PORT
      LAYER met2 ;
      RECT 3855.650 0.000 3855.790 0.420 ;
    END
  END r0_rd_out[93]
  PIN r0_rd_out[94]
    DIRECTION OUTPUT ;
    USE SIGNAL ;
    SHAPE ABUTMENT ;
    PORT
      LAYER met2 ;
      RECT 3866.690 0.000 3866.830 0.420 ;
    END
  END r0_rd_out[94]
  PIN r0_rd_out[95]
    DIRECTION OUTPUT ;
    USE SIGNAL ;
    SHAPE ABUTMENT ;
    PORT
      LAYER met2 ;
      RECT 3877.730 0.000 3877.870 0.420 ;
    END
  END r0_rd_out[95]
  PIN r0_rd_out[96]
    DIRECTION OUTPUT ;
    USE SIGNAL ;
    SHAPE ABUTMENT ;
    PORT
      LAYER met2 ;
      RECT 3888.770 0.000 3888.910 0.420 ;
    END
  END r0_rd_out[96]
  PIN r0_rd_out[97]
    DIRECTION OUTPUT ;
    USE SIGNAL ;
    SHAPE ABUTMENT ;
    PORT
      LAYER met2 ;
      RECT 3899.810 0.000 3899.950 0.420 ;
    END
  END r0_rd_out[97]
  PIN r0_rd_out[98]
    DIRECTION OUTPUT ;
    USE SIGNAL ;
    SHAPE ABUTMENT ;
    PORT
      LAYER met2 ;
      RECT 3910.850 0.000 3910.990 0.420 ;
    END
  END r0_rd_out[98]
  PIN r0_rd_out[99]
    DIRECTION OUTPUT ;
    USE SIGNAL ;
    SHAPE ABUTMENT ;
    PORT
      LAYER met2 ;
      RECT 3921.890 0.000 3922.030 0.420 ;
    END
  END r0_rd_out[99]
  PIN r0_rd_out[100]
    DIRECTION OUTPUT ;
    USE SIGNAL ;
    SHAPE ABUTMENT ;
    PORT
      LAYER met2 ;
      RECT 3932.930 0.000 3933.070 0.420 ;
    END
  END r0_rd_out[100]
  PIN r0_rd_out[101]
    DIRECTION OUTPUT ;
    USE SIGNAL ;
    SHAPE ABUTMENT ;
    PORT
      LAYER met2 ;
      RECT 3943.970 0.000 3944.110 0.420 ;
    END
  END r0_rd_out[101]
  PIN r0_rd_out[102]
    DIRECTION OUTPUT ;
    USE SIGNAL ;
    SHAPE ABUTMENT ;
    PORT
      LAYER met2 ;
      RECT 3955.010 0.000 3955.150 0.420 ;
    END
  END r0_rd_out[102]
  PIN r0_rd_out[103]
    DIRECTION OUTPUT ;
    USE SIGNAL ;
    SHAPE ABUTMENT ;
    PORT
      LAYER met2 ;
      RECT 3966.050 0.000 3966.190 0.420 ;
    END
  END r0_rd_out[103]
  PIN r0_rd_out[104]
    DIRECTION OUTPUT ;
    USE SIGNAL ;
    SHAPE ABUTMENT ;
    PORT
      LAYER met2 ;
      RECT 3977.090 0.000 3977.230 0.420 ;
    END
  END r0_rd_out[104]
  PIN r0_rd_out[105]
    DIRECTION OUTPUT ;
    USE SIGNAL ;
    SHAPE ABUTMENT ;
    PORT
      LAYER met2 ;
      RECT 3988.130 0.000 3988.270 0.420 ;
    END
  END r0_rd_out[105]
  PIN r0_rd_out[106]
    DIRECTION OUTPUT ;
    USE SIGNAL ;
    SHAPE ABUTMENT ;
    PORT
      LAYER met2 ;
      RECT 3999.170 0.000 3999.310 0.420 ;
    END
  END r0_rd_out[106]
  PIN r0_rd_out[107]
    DIRECTION OUTPUT ;
    USE SIGNAL ;
    SHAPE ABUTMENT ;
    PORT
      LAYER met2 ;
      RECT 4010.210 0.000 4010.350 0.420 ;
    END
  END r0_rd_out[107]
  PIN r0_rd_out[108]
    DIRECTION OUTPUT ;
    USE SIGNAL ;
    SHAPE ABUTMENT ;
    PORT
      LAYER met2 ;
      RECT 4021.250 0.000 4021.390 0.420 ;
    END
  END r0_rd_out[108]
  PIN r0_rd_out[109]
    DIRECTION OUTPUT ;
    USE SIGNAL ;
    SHAPE ABUTMENT ;
    PORT
      LAYER met2 ;
      RECT 4032.290 0.000 4032.430 0.420 ;
    END
  END r0_rd_out[109]
  PIN r0_rd_out[110]
    DIRECTION OUTPUT ;
    USE SIGNAL ;
    SHAPE ABUTMENT ;
    PORT
      LAYER met2 ;
      RECT 4043.330 0.000 4043.470 0.420 ;
    END
  END r0_rd_out[110]
  PIN r0_rd_out[111]
    DIRECTION OUTPUT ;
    USE SIGNAL ;
    SHAPE ABUTMENT ;
    PORT
      LAYER met2 ;
      RECT 4054.370 0.000 4054.510 0.420 ;
    END
  END r0_rd_out[111]
  PIN r0_rd_out[112]
    DIRECTION OUTPUT ;
    USE SIGNAL ;
    SHAPE ABUTMENT ;
    PORT
      LAYER met2 ;
      RECT 4065.410 0.000 4065.550 0.420 ;
    END
  END r0_rd_out[112]
  PIN r0_rd_out[113]
    DIRECTION OUTPUT ;
    USE SIGNAL ;
    SHAPE ABUTMENT ;
    PORT
      LAYER met2 ;
      RECT 4076.450 0.000 4076.590 0.420 ;
    END
  END r0_rd_out[113]
  PIN r0_rd_out[114]
    DIRECTION OUTPUT ;
    USE SIGNAL ;
    SHAPE ABUTMENT ;
    PORT
      LAYER met2 ;
      RECT 4087.490 0.000 4087.630 0.420 ;
    END
  END r0_rd_out[114]
  PIN r0_rd_out[115]
    DIRECTION OUTPUT ;
    USE SIGNAL ;
    SHAPE ABUTMENT ;
    PORT
      LAYER met2 ;
      RECT 4098.530 0.000 4098.670 0.420 ;
    END
  END r0_rd_out[115]
  PIN r0_rd_out[116]
    DIRECTION OUTPUT ;
    USE SIGNAL ;
    SHAPE ABUTMENT ;
    PORT
      LAYER met2 ;
      RECT 4109.570 0.000 4109.710 0.420 ;
    END
  END r0_rd_out[116]
  PIN r0_rd_out[117]
    DIRECTION OUTPUT ;
    USE SIGNAL ;
    SHAPE ABUTMENT ;
    PORT
      LAYER met2 ;
      RECT 4120.610 0.000 4120.750 0.420 ;
    END
  END r0_rd_out[117]
  PIN r0_rd_out[118]
    DIRECTION OUTPUT ;
    USE SIGNAL ;
    SHAPE ABUTMENT ;
    PORT
      LAYER met2 ;
      RECT 4131.650 0.000 4131.790 0.420 ;
    END
  END r0_rd_out[118]
  PIN r0_rd_out[119]
    DIRECTION OUTPUT ;
    USE SIGNAL ;
    SHAPE ABUTMENT ;
    PORT
      LAYER met2 ;
      RECT 4142.690 0.000 4142.830 0.420 ;
    END
  END r0_rd_out[119]
  PIN r0_rd_out[120]
    DIRECTION OUTPUT ;
    USE SIGNAL ;
    SHAPE ABUTMENT ;
    PORT
      LAYER met2 ;
      RECT 4153.730 0.000 4153.870 0.420 ;
    END
  END r0_rd_out[120]
  PIN r0_rd_out[121]
    DIRECTION OUTPUT ;
    USE SIGNAL ;
    SHAPE ABUTMENT ;
    PORT
      LAYER met2 ;
      RECT 4164.770 0.000 4164.910 0.420 ;
    END
  END r0_rd_out[121]
  PIN r0_rd_out[122]
    DIRECTION OUTPUT ;
    USE SIGNAL ;
    SHAPE ABUTMENT ;
    PORT
      LAYER met2 ;
      RECT 4175.810 0.000 4175.950 0.420 ;
    END
  END r0_rd_out[122]
  PIN r0_rd_out[123]
    DIRECTION OUTPUT ;
    USE SIGNAL ;
    SHAPE ABUTMENT ;
    PORT
      LAYER met2 ;
      RECT 4186.850 0.000 4186.990 0.420 ;
    END
  END r0_rd_out[123]
  PIN r0_rd_out[124]
    DIRECTION OUTPUT ;
    USE SIGNAL ;
    SHAPE ABUTMENT ;
    PORT
      LAYER met2 ;
      RECT 4197.890 0.000 4198.030 0.420 ;
    END
  END r0_rd_out[124]
  PIN r0_rd_out[125]
    DIRECTION OUTPUT ;
    USE SIGNAL ;
    SHAPE ABUTMENT ;
    PORT
      LAYER met2 ;
      RECT 4208.930 0.000 4209.070 0.420 ;
    END
  END r0_rd_out[125]
  PIN r0_rd_out[126]
    DIRECTION OUTPUT ;
    USE SIGNAL ;
    SHAPE ABUTMENT ;
    PORT
      LAYER met2 ;
      RECT 4219.970 0.000 4220.110 0.420 ;
    END
  END r0_rd_out[126]
  PIN r0_rd_out[127]
    DIRECTION OUTPUT ;
    USE SIGNAL ;
    SHAPE ABUTMENT ;
    PORT
      LAYER met2 ;
      RECT 4231.010 0.000 4231.150 0.420 ;
    END
  END r0_rd_out[127]
  PIN r0_rd_out[128]
    DIRECTION OUTPUT ;
    USE SIGNAL ;
    SHAPE ABUTMENT ;
    PORT
      LAYER met2 ;
      RECT 4242.050 0.000 4242.190 0.420 ;
    END
  END r0_rd_out[128]
  PIN r0_rd_out[129]
    DIRECTION OUTPUT ;
    USE SIGNAL ;
    SHAPE ABUTMENT ;
    PORT
      LAYER met2 ;
      RECT 4253.090 0.000 4253.230 0.420 ;
    END
  END r0_rd_out[129]
  PIN r0_rd_out[130]
    DIRECTION OUTPUT ;
    USE SIGNAL ;
    SHAPE ABUTMENT ;
    PORT
      LAYER met2 ;
      RECT 4264.130 0.000 4264.270 0.420 ;
    END
  END r0_rd_out[130]
  PIN r0_rd_out[131]
    DIRECTION OUTPUT ;
    USE SIGNAL ;
    SHAPE ABUTMENT ;
    PORT
      LAYER met2 ;
      RECT 4275.170 0.000 4275.310 0.420 ;
    END
  END r0_rd_out[131]
  PIN r0_rd_out[132]
    DIRECTION OUTPUT ;
    USE SIGNAL ;
    SHAPE ABUTMENT ;
    PORT
      LAYER met2 ;
      RECT 4286.210 0.000 4286.350 0.420 ;
    END
  END r0_rd_out[132]
  PIN r0_rd_out[133]
    DIRECTION OUTPUT ;
    USE SIGNAL ;
    SHAPE ABUTMENT ;
    PORT
      LAYER met2 ;
      RECT 4297.250 0.000 4297.390 0.420 ;
    END
  END r0_rd_out[133]
  PIN r0_rd_out[134]
    DIRECTION OUTPUT ;
    USE SIGNAL ;
    SHAPE ABUTMENT ;
    PORT
      LAYER met2 ;
      RECT 4308.290 0.000 4308.430 0.420 ;
    END
  END r0_rd_out[134]
  PIN r0_rd_out[135]
    DIRECTION OUTPUT ;
    USE SIGNAL ;
    SHAPE ABUTMENT ;
    PORT
      LAYER met2 ;
      RECT 4319.330 0.000 4319.470 0.420 ;
    END
  END r0_rd_out[135]
  PIN r0_rd_out[136]
    DIRECTION OUTPUT ;
    USE SIGNAL ;
    SHAPE ABUTMENT ;
    PORT
      LAYER met2 ;
      RECT 4330.370 0.000 4330.510 0.420 ;
    END
  END r0_rd_out[136]
  PIN r0_rd_out[137]
    DIRECTION OUTPUT ;
    USE SIGNAL ;
    SHAPE ABUTMENT ;
    PORT
      LAYER met2 ;
      RECT 4341.410 0.000 4341.550 0.420 ;
    END
  END r0_rd_out[137]
  PIN r0_rd_out[138]
    DIRECTION OUTPUT ;
    USE SIGNAL ;
    SHAPE ABUTMENT ;
    PORT
      LAYER met2 ;
      RECT 4352.450 0.000 4352.590 0.420 ;
    END
  END r0_rd_out[138]
  PIN r0_rd_out[139]
    DIRECTION OUTPUT ;
    USE SIGNAL ;
    SHAPE ABUTMENT ;
    PORT
      LAYER met2 ;
      RECT 4363.490 0.000 4363.630 0.420 ;
    END
  END r0_rd_out[139]
  PIN r0_rd_out[140]
    DIRECTION OUTPUT ;
    USE SIGNAL ;
    SHAPE ABUTMENT ;
    PORT
      LAYER met2 ;
      RECT 4374.530 0.000 4374.670 0.420 ;
    END
  END r0_rd_out[140]
  PIN r0_rd_out[141]
    DIRECTION OUTPUT ;
    USE SIGNAL ;
    SHAPE ABUTMENT ;
    PORT
      LAYER met2 ;
      RECT 4385.570 0.000 4385.710 0.420 ;
    END
  END r0_rd_out[141]
  PIN r0_rd_out[142]
    DIRECTION OUTPUT ;
    USE SIGNAL ;
    SHAPE ABUTMENT ;
    PORT
      LAYER met2 ;
      RECT 4396.610 0.000 4396.750 0.420 ;
    END
  END r0_rd_out[142]
  PIN r0_rd_out[143]
    DIRECTION OUTPUT ;
    USE SIGNAL ;
    SHAPE ABUTMENT ;
    PORT
      LAYER met2 ;
      RECT 4407.650 0.000 4407.790 0.420 ;
    END
  END r0_rd_out[143]
  PIN r0_rd_out[144]
    DIRECTION OUTPUT ;
    USE SIGNAL ;
    SHAPE ABUTMENT ;
    PORT
      LAYER met2 ;
      RECT 4418.690 0.000 4418.830 0.420 ;
    END
  END r0_rd_out[144]
  PIN r0_rd_out[145]
    DIRECTION OUTPUT ;
    USE SIGNAL ;
    SHAPE ABUTMENT ;
    PORT
      LAYER met2 ;
      RECT 4429.730 0.000 4429.870 0.420 ;
    END
  END r0_rd_out[145]
  PIN r0_rd_out[146]
    DIRECTION OUTPUT ;
    USE SIGNAL ;
    SHAPE ABUTMENT ;
    PORT
      LAYER met2 ;
      RECT 4440.770 0.000 4440.910 0.420 ;
    END
  END r0_rd_out[146]
  PIN r0_rd_out[147]
    DIRECTION OUTPUT ;
    USE SIGNAL ;
    SHAPE ABUTMENT ;
    PORT
      LAYER met2 ;
      RECT 4451.810 0.000 4451.950 0.420 ;
    END
  END r0_rd_out[147]
  PIN r0_rd_out[148]
    DIRECTION OUTPUT ;
    USE SIGNAL ;
    SHAPE ABUTMENT ;
    PORT
      LAYER met2 ;
      RECT 4462.850 0.000 4462.990 0.420 ;
    END
  END r0_rd_out[148]
  PIN r0_rd_out[149]
    DIRECTION OUTPUT ;
    USE SIGNAL ;
    SHAPE ABUTMENT ;
    PORT
      LAYER met2 ;
      RECT 4473.890 0.000 4474.030 0.420 ;
    END
  END r0_rd_out[149]
  PIN r0_rd_out[150]
    DIRECTION OUTPUT ;
    USE SIGNAL ;
    SHAPE ABUTMENT ;
    PORT
      LAYER met2 ;
      RECT 4484.930 0.000 4485.070 0.420 ;
    END
  END r0_rd_out[150]
  PIN r0_rd_out[151]
    DIRECTION OUTPUT ;
    USE SIGNAL ;
    SHAPE ABUTMENT ;
    PORT
      LAYER met2 ;
      RECT 4495.970 0.000 4496.110 0.420 ;
    END
  END r0_rd_out[151]
  PIN r0_rd_out[152]
    DIRECTION OUTPUT ;
    USE SIGNAL ;
    SHAPE ABUTMENT ;
    PORT
      LAYER met2 ;
      RECT 4507.010 0.000 4507.150 0.420 ;
    END
  END r0_rd_out[152]
  PIN r0_rd_out[153]
    DIRECTION OUTPUT ;
    USE SIGNAL ;
    SHAPE ABUTMENT ;
    PORT
      LAYER met2 ;
      RECT 4518.050 0.000 4518.190 0.420 ;
    END
  END r0_rd_out[153]
  PIN r0_rd_out[154]
    DIRECTION OUTPUT ;
    USE SIGNAL ;
    SHAPE ABUTMENT ;
    PORT
      LAYER met2 ;
      RECT 4529.090 0.000 4529.230 0.420 ;
    END
  END r0_rd_out[154]
  PIN r0_rd_out[155]
    DIRECTION OUTPUT ;
    USE SIGNAL ;
    SHAPE ABUTMENT ;
    PORT
      LAYER met2 ;
      RECT 4540.130 0.000 4540.270 0.420 ;
    END
  END r0_rd_out[155]
  PIN r0_rd_out[156]
    DIRECTION OUTPUT ;
    USE SIGNAL ;
    SHAPE ABUTMENT ;
    PORT
      LAYER met2 ;
      RECT 4551.170 0.000 4551.310 0.420 ;
    END
  END r0_rd_out[156]
  PIN r0_rd_out[157]
    DIRECTION OUTPUT ;
    USE SIGNAL ;
    SHAPE ABUTMENT ;
    PORT
      LAYER met2 ;
      RECT 4562.210 0.000 4562.350 0.420 ;
    END
  END r0_rd_out[157]
  PIN r0_rd_out[158]
    DIRECTION OUTPUT ;
    USE SIGNAL ;
    SHAPE ABUTMENT ;
    PORT
      LAYER met2 ;
      RECT 4573.250 0.000 4573.390 0.420 ;
    END
  END r0_rd_out[158]
  PIN r0_rd_out[159]
    DIRECTION OUTPUT ;
    USE SIGNAL ;
    SHAPE ABUTMENT ;
    PORT
      LAYER met2 ;
      RECT 4584.290 0.000 4584.430 0.420 ;
    END
  END r0_rd_out[159]
  PIN r0_rd_out[160]
    DIRECTION OUTPUT ;
    USE SIGNAL ;
    SHAPE ABUTMENT ;
    PORT
      LAYER met2 ;
      RECT 4595.330 0.000 4595.470 0.420 ;
    END
  END r0_rd_out[160]
  PIN r0_rd_out[161]
    DIRECTION OUTPUT ;
    USE SIGNAL ;
    SHAPE ABUTMENT ;
    PORT
      LAYER met2 ;
      RECT 4606.370 0.000 4606.510 0.420 ;
    END
  END r0_rd_out[161]
  PIN r0_rd_out[162]
    DIRECTION OUTPUT ;
    USE SIGNAL ;
    SHAPE ABUTMENT ;
    PORT
      LAYER met2 ;
      RECT 4617.410 0.000 4617.550 0.420 ;
    END
  END r0_rd_out[162]
  PIN r0_rd_out[163]
    DIRECTION OUTPUT ;
    USE SIGNAL ;
    SHAPE ABUTMENT ;
    PORT
      LAYER met2 ;
      RECT 4628.450 0.000 4628.590 0.420 ;
    END
  END r0_rd_out[163]
  PIN r0_rd_out[164]
    DIRECTION OUTPUT ;
    USE SIGNAL ;
    SHAPE ABUTMENT ;
    PORT
      LAYER met2 ;
      RECT 4639.490 0.000 4639.630 0.420 ;
    END
  END r0_rd_out[164]
  PIN r0_rd_out[165]
    DIRECTION OUTPUT ;
    USE SIGNAL ;
    SHAPE ABUTMENT ;
    PORT
      LAYER met2 ;
      RECT 4650.530 0.000 4650.670 0.420 ;
    END
  END r0_rd_out[165]
  PIN r0_rd_out[166]
    DIRECTION OUTPUT ;
    USE SIGNAL ;
    SHAPE ABUTMENT ;
    PORT
      LAYER met2 ;
      RECT 4661.570 0.000 4661.710 0.420 ;
    END
  END r0_rd_out[166]
  PIN r0_rd_out[167]
    DIRECTION OUTPUT ;
    USE SIGNAL ;
    SHAPE ABUTMENT ;
    PORT
      LAYER met2 ;
      RECT 4672.610 0.000 4672.750 0.420 ;
    END
  END r0_rd_out[167]
  PIN r0_rd_out[168]
    DIRECTION OUTPUT ;
    USE SIGNAL ;
    SHAPE ABUTMENT ;
    PORT
      LAYER met2 ;
      RECT 4683.650 0.000 4683.790 0.420 ;
    END
  END r0_rd_out[168]
  PIN r0_rd_out[169]
    DIRECTION OUTPUT ;
    USE SIGNAL ;
    SHAPE ABUTMENT ;
    PORT
      LAYER met2 ;
      RECT 4694.690 0.000 4694.830 0.420 ;
    END
  END r0_rd_out[169]
  PIN r0_rd_out[170]
    DIRECTION OUTPUT ;
    USE SIGNAL ;
    SHAPE ABUTMENT ;
    PORT
      LAYER met2 ;
      RECT 4705.730 0.000 4705.870 0.420 ;
    END
  END r0_rd_out[170]
  PIN r0_rd_out[171]
    DIRECTION OUTPUT ;
    USE SIGNAL ;
    SHAPE ABUTMENT ;
    PORT
      LAYER met2 ;
      RECT 4716.770 0.000 4716.910 0.420 ;
    END
  END r0_rd_out[171]
  PIN r0_rd_out[172]
    DIRECTION OUTPUT ;
    USE SIGNAL ;
    SHAPE ABUTMENT ;
    PORT
      LAYER met2 ;
      RECT 4727.810 0.000 4727.950 0.420 ;
    END
  END r0_rd_out[172]
  PIN r0_rd_out[173]
    DIRECTION OUTPUT ;
    USE SIGNAL ;
    SHAPE ABUTMENT ;
    PORT
      LAYER met2 ;
      RECT 4738.850 0.000 4738.990 0.420 ;
    END
  END r0_rd_out[173]
  PIN r0_rd_out[174]
    DIRECTION OUTPUT ;
    USE SIGNAL ;
    SHAPE ABUTMENT ;
    PORT
      LAYER met2 ;
      RECT 4749.890 0.000 4750.030 0.420 ;
    END
  END r0_rd_out[174]
  PIN r0_rd_out[175]
    DIRECTION OUTPUT ;
    USE SIGNAL ;
    SHAPE ABUTMENT ;
    PORT
      LAYER met2 ;
      RECT 4760.930 0.000 4761.070 0.420 ;
    END
  END r0_rd_out[175]
  PIN r0_rd_out[176]
    DIRECTION OUTPUT ;
    USE SIGNAL ;
    SHAPE ABUTMENT ;
    PORT
      LAYER met2 ;
      RECT 4771.970 0.000 4772.110 0.420 ;
    END
  END r0_rd_out[176]
  PIN r0_rd_out[177]
    DIRECTION OUTPUT ;
    USE SIGNAL ;
    SHAPE ABUTMENT ;
    PORT
      LAYER met2 ;
      RECT 4783.010 0.000 4783.150 0.420 ;
    END
  END r0_rd_out[177]
  PIN r0_rd_out[178]
    DIRECTION OUTPUT ;
    USE SIGNAL ;
    SHAPE ABUTMENT ;
    PORT
      LAYER met2 ;
      RECT 4794.050 0.000 4794.190 0.420 ;
    END
  END r0_rd_out[178]
  PIN r0_rd_out[179]
    DIRECTION OUTPUT ;
    USE SIGNAL ;
    SHAPE ABUTMENT ;
    PORT
      LAYER met2 ;
      RECT 4805.090 0.000 4805.230 0.420 ;
    END
  END r0_rd_out[179]
  PIN r0_rd_out[180]
    DIRECTION OUTPUT ;
    USE SIGNAL ;
    SHAPE ABUTMENT ;
    PORT
      LAYER met2 ;
      RECT 4816.130 0.000 4816.270 0.420 ;
    END
  END r0_rd_out[180]
  PIN r0_rd_out[181]
    DIRECTION OUTPUT ;
    USE SIGNAL ;
    SHAPE ABUTMENT ;
    PORT
      LAYER met2 ;
      RECT 4827.170 0.000 4827.310 0.420 ;
    END
  END r0_rd_out[181]
  PIN r0_rd_out[182]
    DIRECTION OUTPUT ;
    USE SIGNAL ;
    SHAPE ABUTMENT ;
    PORT
      LAYER met2 ;
      RECT 4838.210 0.000 4838.350 0.420 ;
    END
  END r0_rd_out[182]
  PIN r0_rd_out[183]
    DIRECTION OUTPUT ;
    USE SIGNAL ;
    SHAPE ABUTMENT ;
    PORT
      LAYER met2 ;
      RECT 4849.250 0.000 4849.390 0.420 ;
    END
  END r0_rd_out[183]
  PIN r0_rd_out[184]
    DIRECTION OUTPUT ;
    USE SIGNAL ;
    SHAPE ABUTMENT ;
    PORT
      LAYER met2 ;
      RECT 4860.290 0.000 4860.430 0.420 ;
    END
  END r0_rd_out[184]
  PIN r0_rd_out[185]
    DIRECTION OUTPUT ;
    USE SIGNAL ;
    SHAPE ABUTMENT ;
    PORT
      LAYER met2 ;
      RECT 4871.330 0.000 4871.470 0.420 ;
    END
  END r0_rd_out[185]
  PIN r0_rd_out[186]
    DIRECTION OUTPUT ;
    USE SIGNAL ;
    SHAPE ABUTMENT ;
    PORT
      LAYER met2 ;
      RECT 4882.370 0.000 4882.510 0.420 ;
    END
  END r0_rd_out[186]
  PIN r0_rd_out[187]
    DIRECTION OUTPUT ;
    USE SIGNAL ;
    SHAPE ABUTMENT ;
    PORT
      LAYER met2 ;
      RECT 4893.410 0.000 4893.550 0.420 ;
    END
  END r0_rd_out[187]
  PIN r0_rd_out[188]
    DIRECTION OUTPUT ;
    USE SIGNAL ;
    SHAPE ABUTMENT ;
    PORT
      LAYER met2 ;
      RECT 4904.450 0.000 4904.590 0.420 ;
    END
  END r0_rd_out[188]
  PIN r0_rd_out[189]
    DIRECTION OUTPUT ;
    USE SIGNAL ;
    SHAPE ABUTMENT ;
    PORT
      LAYER met2 ;
      RECT 4915.490 0.000 4915.630 0.420 ;
    END
  END r0_rd_out[189]
  PIN r0_rd_out[190]
    DIRECTION OUTPUT ;
    USE SIGNAL ;
    SHAPE ABUTMENT ;
    PORT
      LAYER met2 ;
      RECT 4926.530 0.000 4926.670 0.420 ;
    END
  END r0_rd_out[190]
  PIN r0_rd_out[191]
    DIRECTION OUTPUT ;
    USE SIGNAL ;
    SHAPE ABUTMENT ;
    PORT
      LAYER met2 ;
      RECT 4937.570 0.000 4937.710 0.420 ;
    END
  END r0_rd_out[191]
  PIN r0_rd_out[192]
    DIRECTION OUTPUT ;
    USE SIGNAL ;
    SHAPE ABUTMENT ;
    PORT
      LAYER met2 ;
      RECT 4948.610 0.000 4948.750 0.420 ;
    END
  END r0_rd_out[192]
  PIN r0_rd_out[193]
    DIRECTION OUTPUT ;
    USE SIGNAL ;
    SHAPE ABUTMENT ;
    PORT
      LAYER met2 ;
      RECT 4959.650 0.000 4959.790 0.420 ;
    END
  END r0_rd_out[193]
  PIN r0_rd_out[194]
    DIRECTION OUTPUT ;
    USE SIGNAL ;
    SHAPE ABUTMENT ;
    PORT
      LAYER met2 ;
      RECT 4970.690 0.000 4970.830 0.420 ;
    END
  END r0_rd_out[194]
  PIN r0_rd_out[195]
    DIRECTION OUTPUT ;
    USE SIGNAL ;
    SHAPE ABUTMENT ;
    PORT
      LAYER met2 ;
      RECT 4981.730 0.000 4981.870 0.420 ;
    END
  END r0_rd_out[195]
  PIN r0_rd_out[196]
    DIRECTION OUTPUT ;
    USE SIGNAL ;
    SHAPE ABUTMENT ;
    PORT
      LAYER met2 ;
      RECT 4992.770 0.000 4992.910 0.420 ;
    END
  END r0_rd_out[196]
  PIN r0_rd_out[197]
    DIRECTION OUTPUT ;
    USE SIGNAL ;
    SHAPE ABUTMENT ;
    PORT
      LAYER met2 ;
      RECT 5003.810 0.000 5003.950 0.420 ;
    END
  END r0_rd_out[197]
  PIN r0_rd_out[198]
    DIRECTION OUTPUT ;
    USE SIGNAL ;
    SHAPE ABUTMENT ;
    PORT
      LAYER met2 ;
      RECT 5014.850 0.000 5014.990 0.420 ;
    END
  END r0_rd_out[198]
  PIN r0_rd_out[199]
    DIRECTION OUTPUT ;
    USE SIGNAL ;
    SHAPE ABUTMENT ;
    PORT
      LAYER met2 ;
      RECT 5025.890 0.000 5026.030 0.420 ;
    END
  END r0_rd_out[199]
  PIN r0_rd_out[200]
    DIRECTION OUTPUT ;
    USE SIGNAL ;
    SHAPE ABUTMENT ;
    PORT
      LAYER met2 ;
      RECT 5036.930 0.000 5037.070 0.420 ;
    END
  END r0_rd_out[200]
  PIN r0_rd_out[201]
    DIRECTION OUTPUT ;
    USE SIGNAL ;
    SHAPE ABUTMENT ;
    PORT
      LAYER met2 ;
      RECT 5047.970 0.000 5048.110 0.420 ;
    END
  END r0_rd_out[201]
  PIN r0_rd_out[202]
    DIRECTION OUTPUT ;
    USE SIGNAL ;
    SHAPE ABUTMENT ;
    PORT
      LAYER met2 ;
      RECT 5059.010 0.000 5059.150 0.420 ;
    END
  END r0_rd_out[202]
  PIN r0_rd_out[203]
    DIRECTION OUTPUT ;
    USE SIGNAL ;
    SHAPE ABUTMENT ;
    PORT
      LAYER met2 ;
      RECT 5070.050 0.000 5070.190 0.420 ;
    END
  END r0_rd_out[203]
  PIN r0_rd_out[204]
    DIRECTION OUTPUT ;
    USE SIGNAL ;
    SHAPE ABUTMENT ;
    PORT
      LAYER met2 ;
      RECT 5081.090 0.000 5081.230 0.420 ;
    END
  END r0_rd_out[204]
  PIN r0_rd_out[205]
    DIRECTION OUTPUT ;
    USE SIGNAL ;
    SHAPE ABUTMENT ;
    PORT
      LAYER met2 ;
      RECT 5092.130 0.000 5092.270 0.420 ;
    END
  END r0_rd_out[205]
  PIN r0_rd_out[206]
    DIRECTION OUTPUT ;
    USE SIGNAL ;
    SHAPE ABUTMENT ;
    PORT
      LAYER met2 ;
      RECT 5103.170 0.000 5103.310 0.420 ;
    END
  END r0_rd_out[206]
  PIN r0_rd_out[207]
    DIRECTION OUTPUT ;
    USE SIGNAL ;
    SHAPE ABUTMENT ;
    PORT
      LAYER met2 ;
      RECT 5114.210 0.000 5114.350 0.420 ;
    END
  END r0_rd_out[207]
  PIN r0_rd_out[208]
    DIRECTION OUTPUT ;
    USE SIGNAL ;
    SHAPE ABUTMENT ;
    PORT
      LAYER met2 ;
      RECT 5125.250 0.000 5125.390 0.420 ;
    END
  END r0_rd_out[208]
  PIN r0_rd_out[209]
    DIRECTION OUTPUT ;
    USE SIGNAL ;
    SHAPE ABUTMENT ;
    PORT
      LAYER met2 ;
      RECT 5136.290 0.000 5136.430 0.420 ;
    END
  END r0_rd_out[209]
  PIN r0_rd_out[210]
    DIRECTION OUTPUT ;
    USE SIGNAL ;
    SHAPE ABUTMENT ;
    PORT
      LAYER met2 ;
      RECT 5147.330 0.000 5147.470 0.420 ;
    END
  END r0_rd_out[210]
  PIN r0_rd_out[211]
    DIRECTION OUTPUT ;
    USE SIGNAL ;
    SHAPE ABUTMENT ;
    PORT
      LAYER met2 ;
      RECT 5158.370 0.000 5158.510 0.420 ;
    END
  END r0_rd_out[211]
  PIN r0_rd_out[212]
    DIRECTION OUTPUT ;
    USE SIGNAL ;
    SHAPE ABUTMENT ;
    PORT
      LAYER met2 ;
      RECT 5169.410 0.000 5169.550 0.420 ;
    END
  END r0_rd_out[212]
  PIN r0_rd_out[213]
    DIRECTION OUTPUT ;
    USE SIGNAL ;
    SHAPE ABUTMENT ;
    PORT
      LAYER met2 ;
      RECT 5180.450 0.000 5180.590 0.420 ;
    END
  END r0_rd_out[213]
  PIN r0_rd_out[214]
    DIRECTION OUTPUT ;
    USE SIGNAL ;
    SHAPE ABUTMENT ;
    PORT
      LAYER met2 ;
      RECT 5191.490 0.000 5191.630 0.420 ;
    END
  END r0_rd_out[214]
  PIN r0_rd_out[215]
    DIRECTION OUTPUT ;
    USE SIGNAL ;
    SHAPE ABUTMENT ;
    PORT
      LAYER met2 ;
      RECT 5202.530 0.000 5202.670 0.420 ;
    END
  END r0_rd_out[215]
  PIN r0_rd_out[216]
    DIRECTION OUTPUT ;
    USE SIGNAL ;
    SHAPE ABUTMENT ;
    PORT
      LAYER met2 ;
      RECT 5213.570 0.000 5213.710 0.420 ;
    END
  END r0_rd_out[216]
  PIN r0_rd_out[217]
    DIRECTION OUTPUT ;
    USE SIGNAL ;
    SHAPE ABUTMENT ;
    PORT
      LAYER met2 ;
      RECT 5224.610 0.000 5224.750 0.420 ;
    END
  END r0_rd_out[217]
  PIN r0_rd_out[218]
    DIRECTION OUTPUT ;
    USE SIGNAL ;
    SHAPE ABUTMENT ;
    PORT
      LAYER met2 ;
      RECT 5235.650 0.000 5235.790 0.420 ;
    END
  END r0_rd_out[218]
  PIN r0_rd_out[219]
    DIRECTION OUTPUT ;
    USE SIGNAL ;
    SHAPE ABUTMENT ;
    PORT
      LAYER met2 ;
      RECT 5246.690 0.000 5246.830 0.420 ;
    END
  END r0_rd_out[219]
  PIN r0_rd_out[220]
    DIRECTION OUTPUT ;
    USE SIGNAL ;
    SHAPE ABUTMENT ;
    PORT
      LAYER met2 ;
      RECT 5257.730 0.000 5257.870 0.420 ;
    END
  END r0_rd_out[220]
  PIN r0_rd_out[221]
    DIRECTION OUTPUT ;
    USE SIGNAL ;
    SHAPE ABUTMENT ;
    PORT
      LAYER met2 ;
      RECT 5268.770 0.000 5268.910 0.420 ;
    END
  END r0_rd_out[221]
  PIN r0_rd_out[222]
    DIRECTION OUTPUT ;
    USE SIGNAL ;
    SHAPE ABUTMENT ;
    PORT
      LAYER met2 ;
      RECT 5279.810 0.000 5279.950 0.420 ;
    END
  END r0_rd_out[222]
  PIN r0_rd_out[223]
    DIRECTION OUTPUT ;
    USE SIGNAL ;
    SHAPE ABUTMENT ;
    PORT
      LAYER met2 ;
      RECT 5290.850 0.000 5290.990 0.420 ;
    END
  END r0_rd_out[223]
  PIN r0_rd_out[224]
    DIRECTION OUTPUT ;
    USE SIGNAL ;
    SHAPE ABUTMENT ;
    PORT
      LAYER met2 ;
      RECT 5301.890 0.000 5302.030 0.420 ;
    END
  END r0_rd_out[224]
  PIN r0_rd_out[225]
    DIRECTION OUTPUT ;
    USE SIGNAL ;
    SHAPE ABUTMENT ;
    PORT
      LAYER met2 ;
      RECT 5312.930 0.000 5313.070 0.420 ;
    END
  END r0_rd_out[225]
  PIN r0_rd_out[226]
    DIRECTION OUTPUT ;
    USE SIGNAL ;
    SHAPE ABUTMENT ;
    PORT
      LAYER met2 ;
      RECT 5323.970 0.000 5324.110 0.420 ;
    END
  END r0_rd_out[226]
  PIN r0_rd_out[227]
    DIRECTION OUTPUT ;
    USE SIGNAL ;
    SHAPE ABUTMENT ;
    PORT
      LAYER met2 ;
      RECT 5335.010 0.000 5335.150 0.420 ;
    END
  END r0_rd_out[227]
  PIN r0_rd_out[228]
    DIRECTION OUTPUT ;
    USE SIGNAL ;
    SHAPE ABUTMENT ;
    PORT
      LAYER met2 ;
      RECT 5346.050 0.000 5346.190 0.420 ;
    END
  END r0_rd_out[228]
  PIN r0_rd_out[229]
    DIRECTION OUTPUT ;
    USE SIGNAL ;
    SHAPE ABUTMENT ;
    PORT
      LAYER met2 ;
      RECT 5357.090 0.000 5357.230 0.420 ;
    END
  END r0_rd_out[229]
  PIN r0_rd_out[230]
    DIRECTION OUTPUT ;
    USE SIGNAL ;
    SHAPE ABUTMENT ;
    PORT
      LAYER met2 ;
      RECT 5368.130 0.000 5368.270 0.420 ;
    END
  END r0_rd_out[230]
  PIN r0_rd_out[231]
    DIRECTION OUTPUT ;
    USE SIGNAL ;
    SHAPE ABUTMENT ;
    PORT
      LAYER met2 ;
      RECT 5379.170 0.000 5379.310 0.420 ;
    END
  END r0_rd_out[231]
  PIN r0_rd_out[232]
    DIRECTION OUTPUT ;
    USE SIGNAL ;
    SHAPE ABUTMENT ;
    PORT
      LAYER met2 ;
      RECT 5390.210 0.000 5390.350 0.420 ;
    END
  END r0_rd_out[232]
  PIN r0_rd_out[233]
    DIRECTION OUTPUT ;
    USE SIGNAL ;
    SHAPE ABUTMENT ;
    PORT
      LAYER met2 ;
      RECT 5401.250 0.000 5401.390 0.420 ;
    END
  END r0_rd_out[233]
  PIN r0_rd_out[234]
    DIRECTION OUTPUT ;
    USE SIGNAL ;
    SHAPE ABUTMENT ;
    PORT
      LAYER met2 ;
      RECT 5412.290 0.000 5412.430 0.420 ;
    END
  END r0_rd_out[234]
  PIN r0_rd_out[235]
    DIRECTION OUTPUT ;
    USE SIGNAL ;
    SHAPE ABUTMENT ;
    PORT
      LAYER met2 ;
      RECT 5423.330 0.000 5423.470 0.420 ;
    END
  END r0_rd_out[235]
  PIN r0_rd_out[236]
    DIRECTION OUTPUT ;
    USE SIGNAL ;
    SHAPE ABUTMENT ;
    PORT
      LAYER met2 ;
      RECT 5434.370 0.000 5434.510 0.420 ;
    END
  END r0_rd_out[236]
  PIN r0_rd_out[237]
    DIRECTION OUTPUT ;
    USE SIGNAL ;
    SHAPE ABUTMENT ;
    PORT
      LAYER met2 ;
      RECT 5445.410 0.000 5445.550 0.420 ;
    END
  END r0_rd_out[237]
  PIN r0_rd_out[238]
    DIRECTION OUTPUT ;
    USE SIGNAL ;
    SHAPE ABUTMENT ;
    PORT
      LAYER met2 ;
      RECT 5456.450 0.000 5456.590 0.420 ;
    END
  END r0_rd_out[238]
  PIN r0_rd_out[239]
    DIRECTION OUTPUT ;
    USE SIGNAL ;
    SHAPE ABUTMENT ;
    PORT
      LAYER met2 ;
      RECT 5467.490 0.000 5467.630 0.420 ;
    END
  END r0_rd_out[239]
  PIN r0_rd_out[240]
    DIRECTION OUTPUT ;
    USE SIGNAL ;
    SHAPE ABUTMENT ;
    PORT
      LAYER met2 ;
      RECT 5478.530 0.000 5478.670 0.420 ;
    END
  END r0_rd_out[240]
  PIN r0_rd_out[241]
    DIRECTION OUTPUT ;
    USE SIGNAL ;
    SHAPE ABUTMENT ;
    PORT
      LAYER met2 ;
      RECT 5489.570 0.000 5489.710 0.420 ;
    END
  END r0_rd_out[241]
  PIN r0_rd_out[242]
    DIRECTION OUTPUT ;
    USE SIGNAL ;
    SHAPE ABUTMENT ;
    PORT
      LAYER met2 ;
      RECT 5500.610 0.000 5500.750 0.420 ;
    END
  END r0_rd_out[242]
  PIN r0_rd_out[243]
    DIRECTION OUTPUT ;
    USE SIGNAL ;
    SHAPE ABUTMENT ;
    PORT
      LAYER met2 ;
      RECT 5511.650 0.000 5511.790 0.420 ;
    END
  END r0_rd_out[243]
  PIN r0_rd_out[244]
    DIRECTION OUTPUT ;
    USE SIGNAL ;
    SHAPE ABUTMENT ;
    PORT
      LAYER met2 ;
      RECT 5522.690 0.000 5522.830 0.420 ;
    END
  END r0_rd_out[244]
  PIN r0_rd_out[245]
    DIRECTION OUTPUT ;
    USE SIGNAL ;
    SHAPE ABUTMENT ;
    PORT
      LAYER met2 ;
      RECT 5533.730 0.000 5533.870 0.420 ;
    END
  END r0_rd_out[245]
  PIN r0_rd_out[246]
    DIRECTION OUTPUT ;
    USE SIGNAL ;
    SHAPE ABUTMENT ;
    PORT
      LAYER met2 ;
      RECT 5544.770 0.000 5544.910 0.420 ;
    END
  END r0_rd_out[246]
  PIN r0_rd_out[247]
    DIRECTION OUTPUT ;
    USE SIGNAL ;
    SHAPE ABUTMENT ;
    PORT
      LAYER met2 ;
      RECT 5555.810 0.000 5555.950 0.420 ;
    END
  END r0_rd_out[247]
  PIN r0_rd_out[248]
    DIRECTION OUTPUT ;
    USE SIGNAL ;
    SHAPE ABUTMENT ;
    PORT
      LAYER met2 ;
      RECT 5566.850 0.000 5566.990 0.420 ;
    END
  END r0_rd_out[248]
  PIN r0_rd_out[249]
    DIRECTION OUTPUT ;
    USE SIGNAL ;
    SHAPE ABUTMENT ;
    PORT
      LAYER met2 ;
      RECT 5577.890 0.000 5578.030 0.420 ;
    END
  END r0_rd_out[249]
  PIN r0_rd_out[250]
    DIRECTION OUTPUT ;
    USE SIGNAL ;
    SHAPE ABUTMENT ;
    PORT
      LAYER met2 ;
      RECT 5588.930 0.000 5589.070 0.420 ;
    END
  END r0_rd_out[250]
  PIN r0_rd_out[251]
    DIRECTION OUTPUT ;
    USE SIGNAL ;
    SHAPE ABUTMENT ;
    PORT
      LAYER met2 ;
      RECT 5599.970 0.000 5600.110 0.420 ;
    END
  END r0_rd_out[251]
  PIN r0_rd_out[252]
    DIRECTION OUTPUT ;
    USE SIGNAL ;
    SHAPE ABUTMENT ;
    PORT
      LAYER met2 ;
      RECT 5611.010 0.000 5611.150 0.420 ;
    END
  END r0_rd_out[252]
  PIN r0_rd_out[253]
    DIRECTION OUTPUT ;
    USE SIGNAL ;
    SHAPE ABUTMENT ;
    PORT
      LAYER met2 ;
      RECT 5622.050 0.000 5622.190 0.420 ;
    END
  END r0_rd_out[253]
  PIN r0_rd_out[254]
    DIRECTION OUTPUT ;
    USE SIGNAL ;
    SHAPE ABUTMENT ;
    PORT
      LAYER met2 ;
      RECT 5633.090 0.000 5633.230 0.420 ;
    END
  END r0_rd_out[254]
  PIN r0_rd_out[255]
    DIRECTION OUTPUT ;
    USE SIGNAL ;
    SHAPE ABUTMENT ;
    PORT
      LAYER met2 ;
      RECT 5644.130 0.000 5644.270 0.420 ;
    END
  END r0_rd_out[255]
  PIN r0_rd_out[256]
    DIRECTION OUTPUT ;
    USE SIGNAL ;
    SHAPE ABUTMENT ;
    PORT
      LAYER met2 ;
      RECT 2.690 1435.740 2.830 1436.160 ;
    END
  END r0_rd_out[256]
  PIN r0_rd_out[257]
    DIRECTION OUTPUT ;
    USE SIGNAL ;
    SHAPE ABUTMENT ;
    PORT
      LAYER met2 ;
      RECT 24.770 1435.740 24.910 1436.160 ;
    END
  END r0_rd_out[257]
  PIN r0_rd_out[258]
    DIRECTION OUTPUT ;
    USE SIGNAL ;
    SHAPE ABUTMENT ;
    PORT
      LAYER met2 ;
      RECT 46.850 1435.740 46.990 1436.160 ;
    END
  END r0_rd_out[258]
  PIN r0_rd_out[259]
    DIRECTION OUTPUT ;
    USE SIGNAL ;
    SHAPE ABUTMENT ;
    PORT
      LAYER met2 ;
      RECT 68.930 1435.740 69.070 1436.160 ;
    END
  END r0_rd_out[259]
  PIN r0_rd_out[260]
    DIRECTION OUTPUT ;
    USE SIGNAL ;
    SHAPE ABUTMENT ;
    PORT
      LAYER met2 ;
      RECT 91.010 1435.740 91.150 1436.160 ;
    END
  END r0_rd_out[260]
  PIN r0_rd_out[261]
    DIRECTION OUTPUT ;
    USE SIGNAL ;
    SHAPE ABUTMENT ;
    PORT
      LAYER met2 ;
      RECT 113.090 1435.740 113.230 1436.160 ;
    END
  END r0_rd_out[261]
  PIN r0_rd_out[262]
    DIRECTION OUTPUT ;
    USE SIGNAL ;
    SHAPE ABUTMENT ;
    PORT
      LAYER met2 ;
      RECT 135.170 1435.740 135.310 1436.160 ;
    END
  END r0_rd_out[262]
  PIN r0_rd_out[263]
    DIRECTION OUTPUT ;
    USE SIGNAL ;
    SHAPE ABUTMENT ;
    PORT
      LAYER met2 ;
      RECT 157.250 1435.740 157.390 1436.160 ;
    END
  END r0_rd_out[263]
  PIN r0_rd_out[264]
    DIRECTION OUTPUT ;
    USE SIGNAL ;
    SHAPE ABUTMENT ;
    PORT
      LAYER met2 ;
      RECT 179.330 1435.740 179.470 1436.160 ;
    END
  END r0_rd_out[264]
  PIN r0_rd_out[265]
    DIRECTION OUTPUT ;
    USE SIGNAL ;
    SHAPE ABUTMENT ;
    PORT
      LAYER met2 ;
      RECT 201.410 1435.740 201.550 1436.160 ;
    END
  END r0_rd_out[265]
  PIN r0_rd_out[266]
    DIRECTION OUTPUT ;
    USE SIGNAL ;
    SHAPE ABUTMENT ;
    PORT
      LAYER met2 ;
      RECT 223.490 1435.740 223.630 1436.160 ;
    END
  END r0_rd_out[266]
  PIN r0_rd_out[267]
    DIRECTION OUTPUT ;
    USE SIGNAL ;
    SHAPE ABUTMENT ;
    PORT
      LAYER met2 ;
      RECT 245.570 1435.740 245.710 1436.160 ;
    END
  END r0_rd_out[267]
  PIN r0_rd_out[268]
    DIRECTION OUTPUT ;
    USE SIGNAL ;
    SHAPE ABUTMENT ;
    PORT
      LAYER met2 ;
      RECT 267.650 1435.740 267.790 1436.160 ;
    END
  END r0_rd_out[268]
  PIN r0_rd_out[269]
    DIRECTION OUTPUT ;
    USE SIGNAL ;
    SHAPE ABUTMENT ;
    PORT
      LAYER met2 ;
      RECT 289.730 1435.740 289.870 1436.160 ;
    END
  END r0_rd_out[269]
  PIN r0_rd_out[270]
    DIRECTION OUTPUT ;
    USE SIGNAL ;
    SHAPE ABUTMENT ;
    PORT
      LAYER met2 ;
      RECT 311.810 1435.740 311.950 1436.160 ;
    END
  END r0_rd_out[270]
  PIN r0_rd_out[271]
    DIRECTION OUTPUT ;
    USE SIGNAL ;
    SHAPE ABUTMENT ;
    PORT
      LAYER met2 ;
      RECT 333.890 1435.740 334.030 1436.160 ;
    END
  END r0_rd_out[271]
  PIN r0_rd_out[272]
    DIRECTION OUTPUT ;
    USE SIGNAL ;
    SHAPE ABUTMENT ;
    PORT
      LAYER met2 ;
      RECT 355.970 1435.740 356.110 1436.160 ;
    END
  END r0_rd_out[272]
  PIN r0_rd_out[273]
    DIRECTION OUTPUT ;
    USE SIGNAL ;
    SHAPE ABUTMENT ;
    PORT
      LAYER met2 ;
      RECT 378.050 1435.740 378.190 1436.160 ;
    END
  END r0_rd_out[273]
  PIN r0_rd_out[274]
    DIRECTION OUTPUT ;
    USE SIGNAL ;
    SHAPE ABUTMENT ;
    PORT
      LAYER met2 ;
      RECT 400.130 1435.740 400.270 1436.160 ;
    END
  END r0_rd_out[274]
  PIN r0_rd_out[275]
    DIRECTION OUTPUT ;
    USE SIGNAL ;
    SHAPE ABUTMENT ;
    PORT
      LAYER met2 ;
      RECT 422.210 1435.740 422.350 1436.160 ;
    END
  END r0_rd_out[275]
  PIN r0_rd_out[276]
    DIRECTION OUTPUT ;
    USE SIGNAL ;
    SHAPE ABUTMENT ;
    PORT
      LAYER met2 ;
      RECT 444.290 1435.740 444.430 1436.160 ;
    END
  END r0_rd_out[276]
  PIN r0_rd_out[277]
    DIRECTION OUTPUT ;
    USE SIGNAL ;
    SHAPE ABUTMENT ;
    PORT
      LAYER met2 ;
      RECT 466.370 1435.740 466.510 1436.160 ;
    END
  END r0_rd_out[277]
  PIN r0_rd_out[278]
    DIRECTION OUTPUT ;
    USE SIGNAL ;
    SHAPE ABUTMENT ;
    PORT
      LAYER met2 ;
      RECT 488.450 1435.740 488.590 1436.160 ;
    END
  END r0_rd_out[278]
  PIN r0_rd_out[279]
    DIRECTION OUTPUT ;
    USE SIGNAL ;
    SHAPE ABUTMENT ;
    PORT
      LAYER met2 ;
      RECT 510.530 1435.740 510.670 1436.160 ;
    END
  END r0_rd_out[279]
  PIN r0_rd_out[280]
    DIRECTION OUTPUT ;
    USE SIGNAL ;
    SHAPE ABUTMENT ;
    PORT
      LAYER met2 ;
      RECT 532.610 1435.740 532.750 1436.160 ;
    END
  END r0_rd_out[280]
  PIN r0_rd_out[281]
    DIRECTION OUTPUT ;
    USE SIGNAL ;
    SHAPE ABUTMENT ;
    PORT
      LAYER met2 ;
      RECT 554.690 1435.740 554.830 1436.160 ;
    END
  END r0_rd_out[281]
  PIN r0_rd_out[282]
    DIRECTION OUTPUT ;
    USE SIGNAL ;
    SHAPE ABUTMENT ;
    PORT
      LAYER met2 ;
      RECT 576.770 1435.740 576.910 1436.160 ;
    END
  END r0_rd_out[282]
  PIN r0_rd_out[283]
    DIRECTION OUTPUT ;
    USE SIGNAL ;
    SHAPE ABUTMENT ;
    PORT
      LAYER met2 ;
      RECT 598.850 1435.740 598.990 1436.160 ;
    END
  END r0_rd_out[283]
  PIN r0_rd_out[284]
    DIRECTION OUTPUT ;
    USE SIGNAL ;
    SHAPE ABUTMENT ;
    PORT
      LAYER met2 ;
      RECT 620.930 1435.740 621.070 1436.160 ;
    END
  END r0_rd_out[284]
  PIN r0_rd_out[285]
    DIRECTION OUTPUT ;
    USE SIGNAL ;
    SHAPE ABUTMENT ;
    PORT
      LAYER met2 ;
      RECT 643.010 1435.740 643.150 1436.160 ;
    END
  END r0_rd_out[285]
  PIN r0_rd_out[286]
    DIRECTION OUTPUT ;
    USE SIGNAL ;
    SHAPE ABUTMENT ;
    PORT
      LAYER met2 ;
      RECT 665.090 1435.740 665.230 1436.160 ;
    END
  END r0_rd_out[286]
  PIN r0_rd_out[287]
    DIRECTION OUTPUT ;
    USE SIGNAL ;
    SHAPE ABUTMENT ;
    PORT
      LAYER met2 ;
      RECT 687.170 1435.740 687.310 1436.160 ;
    END
  END r0_rd_out[287]
  PIN r0_rd_out[288]
    DIRECTION OUTPUT ;
    USE SIGNAL ;
    SHAPE ABUTMENT ;
    PORT
      LAYER met2 ;
      RECT 709.250 1435.740 709.390 1436.160 ;
    END
  END r0_rd_out[288]
  PIN r0_rd_out[289]
    DIRECTION OUTPUT ;
    USE SIGNAL ;
    SHAPE ABUTMENT ;
    PORT
      LAYER met2 ;
      RECT 731.330 1435.740 731.470 1436.160 ;
    END
  END r0_rd_out[289]
  PIN r0_rd_out[290]
    DIRECTION OUTPUT ;
    USE SIGNAL ;
    SHAPE ABUTMENT ;
    PORT
      LAYER met2 ;
      RECT 753.410 1435.740 753.550 1436.160 ;
    END
  END r0_rd_out[290]
  PIN r0_rd_out[291]
    DIRECTION OUTPUT ;
    USE SIGNAL ;
    SHAPE ABUTMENT ;
    PORT
      LAYER met2 ;
      RECT 775.490 1435.740 775.630 1436.160 ;
    END
  END r0_rd_out[291]
  PIN r0_rd_out[292]
    DIRECTION OUTPUT ;
    USE SIGNAL ;
    SHAPE ABUTMENT ;
    PORT
      LAYER met2 ;
      RECT 797.570 1435.740 797.710 1436.160 ;
    END
  END r0_rd_out[292]
  PIN r0_rd_out[293]
    DIRECTION OUTPUT ;
    USE SIGNAL ;
    SHAPE ABUTMENT ;
    PORT
      LAYER met2 ;
      RECT 819.650 1435.740 819.790 1436.160 ;
    END
  END r0_rd_out[293]
  PIN r0_rd_out[294]
    DIRECTION OUTPUT ;
    USE SIGNAL ;
    SHAPE ABUTMENT ;
    PORT
      LAYER met2 ;
      RECT 841.730 1435.740 841.870 1436.160 ;
    END
  END r0_rd_out[294]
  PIN r0_rd_out[295]
    DIRECTION OUTPUT ;
    USE SIGNAL ;
    SHAPE ABUTMENT ;
    PORT
      LAYER met2 ;
      RECT 863.810 1435.740 863.950 1436.160 ;
    END
  END r0_rd_out[295]
  PIN r0_rd_out[296]
    DIRECTION OUTPUT ;
    USE SIGNAL ;
    SHAPE ABUTMENT ;
    PORT
      LAYER met2 ;
      RECT 885.890 1435.740 886.030 1436.160 ;
    END
  END r0_rd_out[296]
  PIN r0_rd_out[297]
    DIRECTION OUTPUT ;
    USE SIGNAL ;
    SHAPE ABUTMENT ;
    PORT
      LAYER met2 ;
      RECT 907.970 1435.740 908.110 1436.160 ;
    END
  END r0_rd_out[297]
  PIN r0_rd_out[298]
    DIRECTION OUTPUT ;
    USE SIGNAL ;
    SHAPE ABUTMENT ;
    PORT
      LAYER met2 ;
      RECT 930.050 1435.740 930.190 1436.160 ;
    END
  END r0_rd_out[298]
  PIN r0_rd_out[299]
    DIRECTION OUTPUT ;
    USE SIGNAL ;
    SHAPE ABUTMENT ;
    PORT
      LAYER met2 ;
      RECT 952.130 1435.740 952.270 1436.160 ;
    END
  END r0_rd_out[299]
  PIN r0_rd_out[300]
    DIRECTION OUTPUT ;
    USE SIGNAL ;
    SHAPE ABUTMENT ;
    PORT
      LAYER met2 ;
      RECT 974.210 1435.740 974.350 1436.160 ;
    END
  END r0_rd_out[300]
  PIN r0_rd_out[301]
    DIRECTION OUTPUT ;
    USE SIGNAL ;
    SHAPE ABUTMENT ;
    PORT
      LAYER met2 ;
      RECT 996.290 1435.740 996.430 1436.160 ;
    END
  END r0_rd_out[301]
  PIN r0_rd_out[302]
    DIRECTION OUTPUT ;
    USE SIGNAL ;
    SHAPE ABUTMENT ;
    PORT
      LAYER met2 ;
      RECT 1018.370 1435.740 1018.510 1436.160 ;
    END
  END r0_rd_out[302]
  PIN r0_rd_out[303]
    DIRECTION OUTPUT ;
    USE SIGNAL ;
    SHAPE ABUTMENT ;
    PORT
      LAYER met2 ;
      RECT 1040.450 1435.740 1040.590 1436.160 ;
    END
  END r0_rd_out[303]
  PIN r0_rd_out[304]
    DIRECTION OUTPUT ;
    USE SIGNAL ;
    SHAPE ABUTMENT ;
    PORT
      LAYER met2 ;
      RECT 1062.530 1435.740 1062.670 1436.160 ;
    END
  END r0_rd_out[304]
  PIN r0_rd_out[305]
    DIRECTION OUTPUT ;
    USE SIGNAL ;
    SHAPE ABUTMENT ;
    PORT
      LAYER met2 ;
      RECT 1084.610 1435.740 1084.750 1436.160 ;
    END
  END r0_rd_out[305]
  PIN r0_rd_out[306]
    DIRECTION OUTPUT ;
    USE SIGNAL ;
    SHAPE ABUTMENT ;
    PORT
      LAYER met2 ;
      RECT 1106.690 1435.740 1106.830 1436.160 ;
    END
  END r0_rd_out[306]
  PIN r0_rd_out[307]
    DIRECTION OUTPUT ;
    USE SIGNAL ;
    SHAPE ABUTMENT ;
    PORT
      LAYER met2 ;
      RECT 1128.770 1435.740 1128.910 1436.160 ;
    END
  END r0_rd_out[307]
  PIN r0_rd_out[308]
    DIRECTION OUTPUT ;
    USE SIGNAL ;
    SHAPE ABUTMENT ;
    PORT
      LAYER met2 ;
      RECT 1150.850 1435.740 1150.990 1436.160 ;
    END
  END r0_rd_out[308]
  PIN r0_rd_out[309]
    DIRECTION OUTPUT ;
    USE SIGNAL ;
    SHAPE ABUTMENT ;
    PORT
      LAYER met2 ;
      RECT 1172.930 1435.740 1173.070 1436.160 ;
    END
  END r0_rd_out[309]
  PIN r0_rd_out[310]
    DIRECTION OUTPUT ;
    USE SIGNAL ;
    SHAPE ABUTMENT ;
    PORT
      LAYER met2 ;
      RECT 1195.010 1435.740 1195.150 1436.160 ;
    END
  END r0_rd_out[310]
  PIN r0_rd_out[311]
    DIRECTION OUTPUT ;
    USE SIGNAL ;
    SHAPE ABUTMENT ;
    PORT
      LAYER met2 ;
      RECT 1217.090 1435.740 1217.230 1436.160 ;
    END
  END r0_rd_out[311]
  PIN r0_rd_out[312]
    DIRECTION OUTPUT ;
    USE SIGNAL ;
    SHAPE ABUTMENT ;
    PORT
      LAYER met2 ;
      RECT 1239.170 1435.740 1239.310 1436.160 ;
    END
  END r0_rd_out[312]
  PIN r0_rd_out[313]
    DIRECTION OUTPUT ;
    USE SIGNAL ;
    SHAPE ABUTMENT ;
    PORT
      LAYER met2 ;
      RECT 1261.250 1435.740 1261.390 1436.160 ;
    END
  END r0_rd_out[313]
  PIN r0_rd_out[314]
    DIRECTION OUTPUT ;
    USE SIGNAL ;
    SHAPE ABUTMENT ;
    PORT
      LAYER met2 ;
      RECT 1283.330 1435.740 1283.470 1436.160 ;
    END
  END r0_rd_out[314]
  PIN r0_rd_out[315]
    DIRECTION OUTPUT ;
    USE SIGNAL ;
    SHAPE ABUTMENT ;
    PORT
      LAYER met2 ;
      RECT 1305.410 1435.740 1305.550 1436.160 ;
    END
  END r0_rd_out[315]
  PIN r0_rd_out[316]
    DIRECTION OUTPUT ;
    USE SIGNAL ;
    SHAPE ABUTMENT ;
    PORT
      LAYER met2 ;
      RECT 1327.490 1435.740 1327.630 1436.160 ;
    END
  END r0_rd_out[316]
  PIN r0_rd_out[317]
    DIRECTION OUTPUT ;
    USE SIGNAL ;
    SHAPE ABUTMENT ;
    PORT
      LAYER met2 ;
      RECT 1349.570 1435.740 1349.710 1436.160 ;
    END
  END r0_rd_out[317]
  PIN r0_rd_out[318]
    DIRECTION OUTPUT ;
    USE SIGNAL ;
    SHAPE ABUTMENT ;
    PORT
      LAYER met2 ;
      RECT 1371.650 1435.740 1371.790 1436.160 ;
    END
  END r0_rd_out[318]
  PIN r0_rd_out[319]
    DIRECTION OUTPUT ;
    USE SIGNAL ;
    SHAPE ABUTMENT ;
    PORT
      LAYER met2 ;
      RECT 1393.730 1435.740 1393.870 1436.160 ;
    END
  END r0_rd_out[319]
  PIN r0_rd_out[320]
    DIRECTION OUTPUT ;
    USE SIGNAL ;
    SHAPE ABUTMENT ;
    PORT
      LAYER met2 ;
      RECT 1415.810 1435.740 1415.950 1436.160 ;
    END
  END r0_rd_out[320]
  PIN r0_rd_out[321]
    DIRECTION OUTPUT ;
    USE SIGNAL ;
    SHAPE ABUTMENT ;
    PORT
      LAYER met2 ;
      RECT 1437.890 1435.740 1438.030 1436.160 ;
    END
  END r0_rd_out[321]
  PIN r0_rd_out[322]
    DIRECTION OUTPUT ;
    USE SIGNAL ;
    SHAPE ABUTMENT ;
    PORT
      LAYER met2 ;
      RECT 1459.970 1435.740 1460.110 1436.160 ;
    END
  END r0_rd_out[322]
  PIN r0_rd_out[323]
    DIRECTION OUTPUT ;
    USE SIGNAL ;
    SHAPE ABUTMENT ;
    PORT
      LAYER met2 ;
      RECT 1482.050 1435.740 1482.190 1436.160 ;
    END
  END r0_rd_out[323]
  PIN r0_rd_out[324]
    DIRECTION OUTPUT ;
    USE SIGNAL ;
    SHAPE ABUTMENT ;
    PORT
      LAYER met2 ;
      RECT 1504.130 1435.740 1504.270 1436.160 ;
    END
  END r0_rd_out[324]
  PIN r0_rd_out[325]
    DIRECTION OUTPUT ;
    USE SIGNAL ;
    SHAPE ABUTMENT ;
    PORT
      LAYER met2 ;
      RECT 1526.210 1435.740 1526.350 1436.160 ;
    END
  END r0_rd_out[325]
  PIN r0_rd_out[326]
    DIRECTION OUTPUT ;
    USE SIGNAL ;
    SHAPE ABUTMENT ;
    PORT
      LAYER met2 ;
      RECT 1548.290 1435.740 1548.430 1436.160 ;
    END
  END r0_rd_out[326]
  PIN r0_rd_out[327]
    DIRECTION OUTPUT ;
    USE SIGNAL ;
    SHAPE ABUTMENT ;
    PORT
      LAYER met2 ;
      RECT 1570.370 1435.740 1570.510 1436.160 ;
    END
  END r0_rd_out[327]
  PIN r0_rd_out[328]
    DIRECTION OUTPUT ;
    USE SIGNAL ;
    SHAPE ABUTMENT ;
    PORT
      LAYER met2 ;
      RECT 1592.450 1435.740 1592.590 1436.160 ;
    END
  END r0_rd_out[328]
  PIN r0_rd_out[329]
    DIRECTION OUTPUT ;
    USE SIGNAL ;
    SHAPE ABUTMENT ;
    PORT
      LAYER met2 ;
      RECT 1614.530 1435.740 1614.670 1436.160 ;
    END
  END r0_rd_out[329]
  PIN r0_rd_out[330]
    DIRECTION OUTPUT ;
    USE SIGNAL ;
    SHAPE ABUTMENT ;
    PORT
      LAYER met2 ;
      RECT 1636.610 1435.740 1636.750 1436.160 ;
    END
  END r0_rd_out[330]
  PIN r0_rd_out[331]
    DIRECTION OUTPUT ;
    USE SIGNAL ;
    SHAPE ABUTMENT ;
    PORT
      LAYER met2 ;
      RECT 1658.690 1435.740 1658.830 1436.160 ;
    END
  END r0_rd_out[331]
  PIN r0_rd_out[332]
    DIRECTION OUTPUT ;
    USE SIGNAL ;
    SHAPE ABUTMENT ;
    PORT
      LAYER met2 ;
      RECT 1680.770 1435.740 1680.910 1436.160 ;
    END
  END r0_rd_out[332]
  PIN r0_rd_out[333]
    DIRECTION OUTPUT ;
    USE SIGNAL ;
    SHAPE ABUTMENT ;
    PORT
      LAYER met2 ;
      RECT 1702.850 1435.740 1702.990 1436.160 ;
    END
  END r0_rd_out[333]
  PIN r0_rd_out[334]
    DIRECTION OUTPUT ;
    USE SIGNAL ;
    SHAPE ABUTMENT ;
    PORT
      LAYER met2 ;
      RECT 1724.930 1435.740 1725.070 1436.160 ;
    END
  END r0_rd_out[334]
  PIN r0_rd_out[335]
    DIRECTION OUTPUT ;
    USE SIGNAL ;
    SHAPE ABUTMENT ;
    PORT
      LAYER met2 ;
      RECT 1747.010 1435.740 1747.150 1436.160 ;
    END
  END r0_rd_out[335]
  PIN r0_rd_out[336]
    DIRECTION OUTPUT ;
    USE SIGNAL ;
    SHAPE ABUTMENT ;
    PORT
      LAYER met2 ;
      RECT 1769.090 1435.740 1769.230 1436.160 ;
    END
  END r0_rd_out[336]
  PIN r0_rd_out[337]
    DIRECTION OUTPUT ;
    USE SIGNAL ;
    SHAPE ABUTMENT ;
    PORT
      LAYER met2 ;
      RECT 1791.170 1435.740 1791.310 1436.160 ;
    END
  END r0_rd_out[337]
  PIN r0_rd_out[338]
    DIRECTION OUTPUT ;
    USE SIGNAL ;
    SHAPE ABUTMENT ;
    PORT
      LAYER met2 ;
      RECT 1813.250 1435.740 1813.390 1436.160 ;
    END
  END r0_rd_out[338]
  PIN r0_rd_out[339]
    DIRECTION OUTPUT ;
    USE SIGNAL ;
    SHAPE ABUTMENT ;
    PORT
      LAYER met2 ;
      RECT 1835.330 1435.740 1835.470 1436.160 ;
    END
  END r0_rd_out[339]
  PIN r0_rd_out[340]
    DIRECTION OUTPUT ;
    USE SIGNAL ;
    SHAPE ABUTMENT ;
    PORT
      LAYER met2 ;
      RECT 1857.410 1435.740 1857.550 1436.160 ;
    END
  END r0_rd_out[340]
  PIN r0_rd_out[341]
    DIRECTION OUTPUT ;
    USE SIGNAL ;
    SHAPE ABUTMENT ;
    PORT
      LAYER met2 ;
      RECT 1879.490 1435.740 1879.630 1436.160 ;
    END
  END r0_rd_out[341]
  PIN r0_rd_out[342]
    DIRECTION OUTPUT ;
    USE SIGNAL ;
    SHAPE ABUTMENT ;
    PORT
      LAYER met2 ;
      RECT 1901.570 1435.740 1901.710 1436.160 ;
    END
  END r0_rd_out[342]
  PIN r0_rd_out[343]
    DIRECTION OUTPUT ;
    USE SIGNAL ;
    SHAPE ABUTMENT ;
    PORT
      LAYER met2 ;
      RECT 1923.650 1435.740 1923.790 1436.160 ;
    END
  END r0_rd_out[343]
  PIN r0_rd_out[344]
    DIRECTION OUTPUT ;
    USE SIGNAL ;
    SHAPE ABUTMENT ;
    PORT
      LAYER met2 ;
      RECT 1945.730 1435.740 1945.870 1436.160 ;
    END
  END r0_rd_out[344]
  PIN r0_rd_out[345]
    DIRECTION OUTPUT ;
    USE SIGNAL ;
    SHAPE ABUTMENT ;
    PORT
      LAYER met2 ;
      RECT 1967.810 1435.740 1967.950 1436.160 ;
    END
  END r0_rd_out[345]
  PIN r0_rd_out[346]
    DIRECTION OUTPUT ;
    USE SIGNAL ;
    SHAPE ABUTMENT ;
    PORT
      LAYER met2 ;
      RECT 1989.890 1435.740 1990.030 1436.160 ;
    END
  END r0_rd_out[346]
  PIN r0_rd_out[347]
    DIRECTION OUTPUT ;
    USE SIGNAL ;
    SHAPE ABUTMENT ;
    PORT
      LAYER met2 ;
      RECT 2011.970 1435.740 2012.110 1436.160 ;
    END
  END r0_rd_out[347]
  PIN r0_rd_out[348]
    DIRECTION OUTPUT ;
    USE SIGNAL ;
    SHAPE ABUTMENT ;
    PORT
      LAYER met2 ;
      RECT 2034.050 1435.740 2034.190 1436.160 ;
    END
  END r0_rd_out[348]
  PIN r0_rd_out[349]
    DIRECTION OUTPUT ;
    USE SIGNAL ;
    SHAPE ABUTMENT ;
    PORT
      LAYER met2 ;
      RECT 2056.130 1435.740 2056.270 1436.160 ;
    END
  END r0_rd_out[349]
  PIN r0_rd_out[350]
    DIRECTION OUTPUT ;
    USE SIGNAL ;
    SHAPE ABUTMENT ;
    PORT
      LAYER met2 ;
      RECT 2078.210 1435.740 2078.350 1436.160 ;
    END
  END r0_rd_out[350]
  PIN r0_rd_out[351]
    DIRECTION OUTPUT ;
    USE SIGNAL ;
    SHAPE ABUTMENT ;
    PORT
      LAYER met2 ;
      RECT 2100.290 1435.740 2100.430 1436.160 ;
    END
  END r0_rd_out[351]
  PIN r0_rd_out[352]
    DIRECTION OUTPUT ;
    USE SIGNAL ;
    SHAPE ABUTMENT ;
    PORT
      LAYER met2 ;
      RECT 2122.370 1435.740 2122.510 1436.160 ;
    END
  END r0_rd_out[352]
  PIN r0_rd_out[353]
    DIRECTION OUTPUT ;
    USE SIGNAL ;
    SHAPE ABUTMENT ;
    PORT
      LAYER met2 ;
      RECT 2144.450 1435.740 2144.590 1436.160 ;
    END
  END r0_rd_out[353]
  PIN r0_rd_out[354]
    DIRECTION OUTPUT ;
    USE SIGNAL ;
    SHAPE ABUTMENT ;
    PORT
      LAYER met2 ;
      RECT 2166.530 1435.740 2166.670 1436.160 ;
    END
  END r0_rd_out[354]
  PIN r0_rd_out[355]
    DIRECTION OUTPUT ;
    USE SIGNAL ;
    SHAPE ABUTMENT ;
    PORT
      LAYER met2 ;
      RECT 2188.610 1435.740 2188.750 1436.160 ;
    END
  END r0_rd_out[355]
  PIN r0_rd_out[356]
    DIRECTION OUTPUT ;
    USE SIGNAL ;
    SHAPE ABUTMENT ;
    PORT
      LAYER met2 ;
      RECT 2210.690 1435.740 2210.830 1436.160 ;
    END
  END r0_rd_out[356]
  PIN r0_rd_out[357]
    DIRECTION OUTPUT ;
    USE SIGNAL ;
    SHAPE ABUTMENT ;
    PORT
      LAYER met2 ;
      RECT 2232.770 1435.740 2232.910 1436.160 ;
    END
  END r0_rd_out[357]
  PIN r0_rd_out[358]
    DIRECTION OUTPUT ;
    USE SIGNAL ;
    SHAPE ABUTMENT ;
    PORT
      LAYER met2 ;
      RECT 2254.850 1435.740 2254.990 1436.160 ;
    END
  END r0_rd_out[358]
  PIN r0_rd_out[359]
    DIRECTION OUTPUT ;
    USE SIGNAL ;
    SHAPE ABUTMENT ;
    PORT
      LAYER met2 ;
      RECT 2276.930 1435.740 2277.070 1436.160 ;
    END
  END r0_rd_out[359]
  PIN r0_rd_out[360]
    DIRECTION OUTPUT ;
    USE SIGNAL ;
    SHAPE ABUTMENT ;
    PORT
      LAYER met2 ;
      RECT 2299.010 1435.740 2299.150 1436.160 ;
    END
  END r0_rd_out[360]
  PIN r0_rd_out[361]
    DIRECTION OUTPUT ;
    USE SIGNAL ;
    SHAPE ABUTMENT ;
    PORT
      LAYER met2 ;
      RECT 2321.090 1435.740 2321.230 1436.160 ;
    END
  END r0_rd_out[361]
  PIN r0_rd_out[362]
    DIRECTION OUTPUT ;
    USE SIGNAL ;
    SHAPE ABUTMENT ;
    PORT
      LAYER met2 ;
      RECT 2343.170 1435.740 2343.310 1436.160 ;
    END
  END r0_rd_out[362]
  PIN r0_rd_out[363]
    DIRECTION OUTPUT ;
    USE SIGNAL ;
    SHAPE ABUTMENT ;
    PORT
      LAYER met2 ;
      RECT 2365.250 1435.740 2365.390 1436.160 ;
    END
  END r0_rd_out[363]
  PIN r0_rd_out[364]
    DIRECTION OUTPUT ;
    USE SIGNAL ;
    SHAPE ABUTMENT ;
    PORT
      LAYER met2 ;
      RECT 2387.330 1435.740 2387.470 1436.160 ;
    END
  END r0_rd_out[364]
  PIN r0_rd_out[365]
    DIRECTION OUTPUT ;
    USE SIGNAL ;
    SHAPE ABUTMENT ;
    PORT
      LAYER met2 ;
      RECT 2409.410 1435.740 2409.550 1436.160 ;
    END
  END r0_rd_out[365]
  PIN r0_rd_out[366]
    DIRECTION OUTPUT ;
    USE SIGNAL ;
    SHAPE ABUTMENT ;
    PORT
      LAYER met2 ;
      RECT 2431.490 1435.740 2431.630 1436.160 ;
    END
  END r0_rd_out[366]
  PIN r0_rd_out[367]
    DIRECTION OUTPUT ;
    USE SIGNAL ;
    SHAPE ABUTMENT ;
    PORT
      LAYER met2 ;
      RECT 2453.570 1435.740 2453.710 1436.160 ;
    END
  END r0_rd_out[367]
  PIN r0_rd_out[368]
    DIRECTION OUTPUT ;
    USE SIGNAL ;
    SHAPE ABUTMENT ;
    PORT
      LAYER met2 ;
      RECT 2475.650 1435.740 2475.790 1436.160 ;
    END
  END r0_rd_out[368]
  PIN r0_rd_out[369]
    DIRECTION OUTPUT ;
    USE SIGNAL ;
    SHAPE ABUTMENT ;
    PORT
      LAYER met2 ;
      RECT 2497.730 1435.740 2497.870 1436.160 ;
    END
  END r0_rd_out[369]
  PIN r0_rd_out[370]
    DIRECTION OUTPUT ;
    USE SIGNAL ;
    SHAPE ABUTMENT ;
    PORT
      LAYER met2 ;
      RECT 2519.810 1435.740 2519.950 1436.160 ;
    END
  END r0_rd_out[370]
  PIN r0_rd_out[371]
    DIRECTION OUTPUT ;
    USE SIGNAL ;
    SHAPE ABUTMENT ;
    PORT
      LAYER met2 ;
      RECT 2541.890 1435.740 2542.030 1436.160 ;
    END
  END r0_rd_out[371]
  PIN r0_rd_out[372]
    DIRECTION OUTPUT ;
    USE SIGNAL ;
    SHAPE ABUTMENT ;
    PORT
      LAYER met2 ;
      RECT 2563.970 1435.740 2564.110 1436.160 ;
    END
  END r0_rd_out[372]
  PIN r0_rd_out[373]
    DIRECTION OUTPUT ;
    USE SIGNAL ;
    SHAPE ABUTMENT ;
    PORT
      LAYER met2 ;
      RECT 2586.050 1435.740 2586.190 1436.160 ;
    END
  END r0_rd_out[373]
  PIN r0_rd_out[374]
    DIRECTION OUTPUT ;
    USE SIGNAL ;
    SHAPE ABUTMENT ;
    PORT
      LAYER met2 ;
      RECT 2608.130 1435.740 2608.270 1436.160 ;
    END
  END r0_rd_out[374]
  PIN r0_rd_out[375]
    DIRECTION OUTPUT ;
    USE SIGNAL ;
    SHAPE ABUTMENT ;
    PORT
      LAYER met2 ;
      RECT 2630.210 1435.740 2630.350 1436.160 ;
    END
  END r0_rd_out[375]
  PIN r0_rd_out[376]
    DIRECTION OUTPUT ;
    USE SIGNAL ;
    SHAPE ABUTMENT ;
    PORT
      LAYER met2 ;
      RECT 2652.290 1435.740 2652.430 1436.160 ;
    END
  END r0_rd_out[376]
  PIN r0_rd_out[377]
    DIRECTION OUTPUT ;
    USE SIGNAL ;
    SHAPE ABUTMENT ;
    PORT
      LAYER met2 ;
      RECT 2674.370 1435.740 2674.510 1436.160 ;
    END
  END r0_rd_out[377]
  PIN r0_rd_out[378]
    DIRECTION OUTPUT ;
    USE SIGNAL ;
    SHAPE ABUTMENT ;
    PORT
      LAYER met2 ;
      RECT 2696.450 1435.740 2696.590 1436.160 ;
    END
  END r0_rd_out[378]
  PIN r0_rd_out[379]
    DIRECTION OUTPUT ;
    USE SIGNAL ;
    SHAPE ABUTMENT ;
    PORT
      LAYER met2 ;
      RECT 2718.530 1435.740 2718.670 1436.160 ;
    END
  END r0_rd_out[379]
  PIN r0_rd_out[380]
    DIRECTION OUTPUT ;
    USE SIGNAL ;
    SHAPE ABUTMENT ;
    PORT
      LAYER met2 ;
      RECT 2740.610 1435.740 2740.750 1436.160 ;
    END
  END r0_rd_out[380]
  PIN r0_rd_out[381]
    DIRECTION OUTPUT ;
    USE SIGNAL ;
    SHAPE ABUTMENT ;
    PORT
      LAYER met2 ;
      RECT 2762.690 1435.740 2762.830 1436.160 ;
    END
  END r0_rd_out[381]
  PIN r0_rd_out[382]
    DIRECTION OUTPUT ;
    USE SIGNAL ;
    SHAPE ABUTMENT ;
    PORT
      LAYER met2 ;
      RECT 2784.770 1435.740 2784.910 1436.160 ;
    END
  END r0_rd_out[382]
  PIN r0_rd_out[383]
    DIRECTION OUTPUT ;
    USE SIGNAL ;
    SHAPE ABUTMENT ;
    PORT
      LAYER met2 ;
      RECT 2806.850 1435.740 2806.990 1436.160 ;
    END
  END r0_rd_out[383]
  PIN r0_rd_out[384]
    DIRECTION OUTPUT ;
    USE SIGNAL ;
    SHAPE ABUTMENT ;
    PORT
      LAYER met2 ;
      RECT 2828.930 1435.740 2829.070 1436.160 ;
    END
  END r0_rd_out[384]
  PIN r0_rd_out[385]
    DIRECTION OUTPUT ;
    USE SIGNAL ;
    SHAPE ABUTMENT ;
    PORT
      LAYER met2 ;
      RECT 2851.010 1435.740 2851.150 1436.160 ;
    END
  END r0_rd_out[385]
  PIN r0_rd_out[386]
    DIRECTION OUTPUT ;
    USE SIGNAL ;
    SHAPE ABUTMENT ;
    PORT
      LAYER met2 ;
      RECT 2873.090 1435.740 2873.230 1436.160 ;
    END
  END r0_rd_out[386]
  PIN r0_rd_out[387]
    DIRECTION OUTPUT ;
    USE SIGNAL ;
    SHAPE ABUTMENT ;
    PORT
      LAYER met2 ;
      RECT 2895.170 1435.740 2895.310 1436.160 ;
    END
  END r0_rd_out[387]
  PIN r0_rd_out[388]
    DIRECTION OUTPUT ;
    USE SIGNAL ;
    SHAPE ABUTMENT ;
    PORT
      LAYER met2 ;
      RECT 2917.250 1435.740 2917.390 1436.160 ;
    END
  END r0_rd_out[388]
  PIN r0_rd_out[389]
    DIRECTION OUTPUT ;
    USE SIGNAL ;
    SHAPE ABUTMENT ;
    PORT
      LAYER met2 ;
      RECT 2939.330 1435.740 2939.470 1436.160 ;
    END
  END r0_rd_out[389]
  PIN r0_rd_out[390]
    DIRECTION OUTPUT ;
    USE SIGNAL ;
    SHAPE ABUTMENT ;
    PORT
      LAYER met2 ;
      RECT 2961.410 1435.740 2961.550 1436.160 ;
    END
  END r0_rd_out[390]
  PIN r0_rd_out[391]
    DIRECTION OUTPUT ;
    USE SIGNAL ;
    SHAPE ABUTMENT ;
    PORT
      LAYER met2 ;
      RECT 2983.490 1435.740 2983.630 1436.160 ;
    END
  END r0_rd_out[391]
  PIN r0_rd_out[392]
    DIRECTION OUTPUT ;
    USE SIGNAL ;
    SHAPE ABUTMENT ;
    PORT
      LAYER met2 ;
      RECT 3005.570 1435.740 3005.710 1436.160 ;
    END
  END r0_rd_out[392]
  PIN r0_rd_out[393]
    DIRECTION OUTPUT ;
    USE SIGNAL ;
    SHAPE ABUTMENT ;
    PORT
      LAYER met2 ;
      RECT 3027.650 1435.740 3027.790 1436.160 ;
    END
  END r0_rd_out[393]
  PIN r0_rd_out[394]
    DIRECTION OUTPUT ;
    USE SIGNAL ;
    SHAPE ABUTMENT ;
    PORT
      LAYER met2 ;
      RECT 3049.730 1435.740 3049.870 1436.160 ;
    END
  END r0_rd_out[394]
  PIN r0_rd_out[395]
    DIRECTION OUTPUT ;
    USE SIGNAL ;
    SHAPE ABUTMENT ;
    PORT
      LAYER met2 ;
      RECT 3071.810 1435.740 3071.950 1436.160 ;
    END
  END r0_rd_out[395]
  PIN r0_rd_out[396]
    DIRECTION OUTPUT ;
    USE SIGNAL ;
    SHAPE ABUTMENT ;
    PORT
      LAYER met2 ;
      RECT 3093.890 1435.740 3094.030 1436.160 ;
    END
  END r0_rd_out[396]
  PIN r0_rd_out[397]
    DIRECTION OUTPUT ;
    USE SIGNAL ;
    SHAPE ABUTMENT ;
    PORT
      LAYER met2 ;
      RECT 3115.970 1435.740 3116.110 1436.160 ;
    END
  END r0_rd_out[397]
  PIN r0_rd_out[398]
    DIRECTION OUTPUT ;
    USE SIGNAL ;
    SHAPE ABUTMENT ;
    PORT
      LAYER met2 ;
      RECT 3138.050 1435.740 3138.190 1436.160 ;
    END
  END r0_rd_out[398]
  PIN r0_rd_out[399]
    DIRECTION OUTPUT ;
    USE SIGNAL ;
    SHAPE ABUTMENT ;
    PORT
      LAYER met2 ;
      RECT 3160.130 1435.740 3160.270 1436.160 ;
    END
  END r0_rd_out[399]
  PIN r0_rd_out[400]
    DIRECTION OUTPUT ;
    USE SIGNAL ;
    SHAPE ABUTMENT ;
    PORT
      LAYER met2 ;
      RECT 3182.210 1435.740 3182.350 1436.160 ;
    END
  END r0_rd_out[400]
  PIN r0_rd_out[401]
    DIRECTION OUTPUT ;
    USE SIGNAL ;
    SHAPE ABUTMENT ;
    PORT
      LAYER met2 ;
      RECT 3204.290 1435.740 3204.430 1436.160 ;
    END
  END r0_rd_out[401]
  PIN r0_rd_out[402]
    DIRECTION OUTPUT ;
    USE SIGNAL ;
    SHAPE ABUTMENT ;
    PORT
      LAYER met2 ;
      RECT 3226.370 1435.740 3226.510 1436.160 ;
    END
  END r0_rd_out[402]
  PIN r0_rd_out[403]
    DIRECTION OUTPUT ;
    USE SIGNAL ;
    SHAPE ABUTMENT ;
    PORT
      LAYER met2 ;
      RECT 3248.450 1435.740 3248.590 1436.160 ;
    END
  END r0_rd_out[403]
  PIN r0_rd_out[404]
    DIRECTION OUTPUT ;
    USE SIGNAL ;
    SHAPE ABUTMENT ;
    PORT
      LAYER met2 ;
      RECT 3270.530 1435.740 3270.670 1436.160 ;
    END
  END r0_rd_out[404]
  PIN r0_rd_out[405]
    DIRECTION OUTPUT ;
    USE SIGNAL ;
    SHAPE ABUTMENT ;
    PORT
      LAYER met2 ;
      RECT 3292.610 1435.740 3292.750 1436.160 ;
    END
  END r0_rd_out[405]
  PIN r0_rd_out[406]
    DIRECTION OUTPUT ;
    USE SIGNAL ;
    SHAPE ABUTMENT ;
    PORT
      LAYER met2 ;
      RECT 3314.690 1435.740 3314.830 1436.160 ;
    END
  END r0_rd_out[406]
  PIN r0_rd_out[407]
    DIRECTION OUTPUT ;
    USE SIGNAL ;
    SHAPE ABUTMENT ;
    PORT
      LAYER met2 ;
      RECT 3336.770 1435.740 3336.910 1436.160 ;
    END
  END r0_rd_out[407]
  PIN r0_rd_out[408]
    DIRECTION OUTPUT ;
    USE SIGNAL ;
    SHAPE ABUTMENT ;
    PORT
      LAYER met2 ;
      RECT 3358.850 1435.740 3358.990 1436.160 ;
    END
  END r0_rd_out[408]
  PIN r0_rd_out[409]
    DIRECTION OUTPUT ;
    USE SIGNAL ;
    SHAPE ABUTMENT ;
    PORT
      LAYER met2 ;
      RECT 3380.930 1435.740 3381.070 1436.160 ;
    END
  END r0_rd_out[409]
  PIN r0_rd_out[410]
    DIRECTION OUTPUT ;
    USE SIGNAL ;
    SHAPE ABUTMENT ;
    PORT
      LAYER met2 ;
      RECT 3403.010 1435.740 3403.150 1436.160 ;
    END
  END r0_rd_out[410]
  PIN r0_rd_out[411]
    DIRECTION OUTPUT ;
    USE SIGNAL ;
    SHAPE ABUTMENT ;
    PORT
      LAYER met2 ;
      RECT 3425.090 1435.740 3425.230 1436.160 ;
    END
  END r0_rd_out[411]
  PIN r0_rd_out[412]
    DIRECTION OUTPUT ;
    USE SIGNAL ;
    SHAPE ABUTMENT ;
    PORT
      LAYER met2 ;
      RECT 3447.170 1435.740 3447.310 1436.160 ;
    END
  END r0_rd_out[412]
  PIN r0_rd_out[413]
    DIRECTION OUTPUT ;
    USE SIGNAL ;
    SHAPE ABUTMENT ;
    PORT
      LAYER met2 ;
      RECT 3469.250 1435.740 3469.390 1436.160 ;
    END
  END r0_rd_out[413]
  PIN r0_rd_out[414]
    DIRECTION OUTPUT ;
    USE SIGNAL ;
    SHAPE ABUTMENT ;
    PORT
      LAYER met2 ;
      RECT 3491.330 1435.740 3491.470 1436.160 ;
    END
  END r0_rd_out[414]
  PIN r0_rd_out[415]
    DIRECTION OUTPUT ;
    USE SIGNAL ;
    SHAPE ABUTMENT ;
    PORT
      LAYER met2 ;
      RECT 3513.410 1435.740 3513.550 1436.160 ;
    END
  END r0_rd_out[415]
  PIN r0_rd_out[416]
    DIRECTION OUTPUT ;
    USE SIGNAL ;
    SHAPE ABUTMENT ;
    PORT
      LAYER met2 ;
      RECT 3535.490 1435.740 3535.630 1436.160 ;
    END
  END r0_rd_out[416]
  PIN r0_rd_out[417]
    DIRECTION OUTPUT ;
    USE SIGNAL ;
    SHAPE ABUTMENT ;
    PORT
      LAYER met2 ;
      RECT 3557.570 1435.740 3557.710 1436.160 ;
    END
  END r0_rd_out[417]
  PIN r0_rd_out[418]
    DIRECTION OUTPUT ;
    USE SIGNAL ;
    SHAPE ABUTMENT ;
    PORT
      LAYER met2 ;
      RECT 3579.650 1435.740 3579.790 1436.160 ;
    END
  END r0_rd_out[418]
  PIN r0_rd_out[419]
    DIRECTION OUTPUT ;
    USE SIGNAL ;
    SHAPE ABUTMENT ;
    PORT
      LAYER met2 ;
      RECT 3601.730 1435.740 3601.870 1436.160 ;
    END
  END r0_rd_out[419]
  PIN r0_rd_out[420]
    DIRECTION OUTPUT ;
    USE SIGNAL ;
    SHAPE ABUTMENT ;
    PORT
      LAYER met2 ;
      RECT 3623.810 1435.740 3623.950 1436.160 ;
    END
  END r0_rd_out[420]
  PIN r0_rd_out[421]
    DIRECTION OUTPUT ;
    USE SIGNAL ;
    SHAPE ABUTMENT ;
    PORT
      LAYER met2 ;
      RECT 3645.890 1435.740 3646.030 1436.160 ;
    END
  END r0_rd_out[421]
  PIN r0_rd_out[422]
    DIRECTION OUTPUT ;
    USE SIGNAL ;
    SHAPE ABUTMENT ;
    PORT
      LAYER met2 ;
      RECT 3667.970 1435.740 3668.110 1436.160 ;
    END
  END r0_rd_out[422]
  PIN r0_rd_out[423]
    DIRECTION OUTPUT ;
    USE SIGNAL ;
    SHAPE ABUTMENT ;
    PORT
      LAYER met2 ;
      RECT 3690.050 1435.740 3690.190 1436.160 ;
    END
  END r0_rd_out[423]
  PIN r0_rd_out[424]
    DIRECTION OUTPUT ;
    USE SIGNAL ;
    SHAPE ABUTMENT ;
    PORT
      LAYER met2 ;
      RECT 3712.130 1435.740 3712.270 1436.160 ;
    END
  END r0_rd_out[424]
  PIN r0_rd_out[425]
    DIRECTION OUTPUT ;
    USE SIGNAL ;
    SHAPE ABUTMENT ;
    PORT
      LAYER met2 ;
      RECT 3734.210 1435.740 3734.350 1436.160 ;
    END
  END r0_rd_out[425]
  PIN r0_rd_out[426]
    DIRECTION OUTPUT ;
    USE SIGNAL ;
    SHAPE ABUTMENT ;
    PORT
      LAYER met2 ;
      RECT 3756.290 1435.740 3756.430 1436.160 ;
    END
  END r0_rd_out[426]
  PIN r0_rd_out[427]
    DIRECTION OUTPUT ;
    USE SIGNAL ;
    SHAPE ABUTMENT ;
    PORT
      LAYER met2 ;
      RECT 3778.370 1435.740 3778.510 1436.160 ;
    END
  END r0_rd_out[427]
  PIN r0_rd_out[428]
    DIRECTION OUTPUT ;
    USE SIGNAL ;
    SHAPE ABUTMENT ;
    PORT
      LAYER met2 ;
      RECT 3800.450 1435.740 3800.590 1436.160 ;
    END
  END r0_rd_out[428]
  PIN r0_rd_out[429]
    DIRECTION OUTPUT ;
    USE SIGNAL ;
    SHAPE ABUTMENT ;
    PORT
      LAYER met2 ;
      RECT 3822.530 1435.740 3822.670 1436.160 ;
    END
  END r0_rd_out[429]
  PIN r0_rd_out[430]
    DIRECTION OUTPUT ;
    USE SIGNAL ;
    SHAPE ABUTMENT ;
    PORT
      LAYER met2 ;
      RECT 3844.610 1435.740 3844.750 1436.160 ;
    END
  END r0_rd_out[430]
  PIN r0_rd_out[431]
    DIRECTION OUTPUT ;
    USE SIGNAL ;
    SHAPE ABUTMENT ;
    PORT
      LAYER met2 ;
      RECT 3866.690 1435.740 3866.830 1436.160 ;
    END
  END r0_rd_out[431]
  PIN r0_rd_out[432]
    DIRECTION OUTPUT ;
    USE SIGNAL ;
    SHAPE ABUTMENT ;
    PORT
      LAYER met2 ;
      RECT 3888.770 1435.740 3888.910 1436.160 ;
    END
  END r0_rd_out[432]
  PIN r0_rd_out[433]
    DIRECTION OUTPUT ;
    USE SIGNAL ;
    SHAPE ABUTMENT ;
    PORT
      LAYER met2 ;
      RECT 3910.850 1435.740 3910.990 1436.160 ;
    END
  END r0_rd_out[433]
  PIN r0_rd_out[434]
    DIRECTION OUTPUT ;
    USE SIGNAL ;
    SHAPE ABUTMENT ;
    PORT
      LAYER met2 ;
      RECT 3932.930 1435.740 3933.070 1436.160 ;
    END
  END r0_rd_out[434]
  PIN r0_rd_out[435]
    DIRECTION OUTPUT ;
    USE SIGNAL ;
    SHAPE ABUTMENT ;
    PORT
      LAYER met2 ;
      RECT 3955.010 1435.740 3955.150 1436.160 ;
    END
  END r0_rd_out[435]
  PIN r0_rd_out[436]
    DIRECTION OUTPUT ;
    USE SIGNAL ;
    SHAPE ABUTMENT ;
    PORT
      LAYER met2 ;
      RECT 3977.090 1435.740 3977.230 1436.160 ;
    END
  END r0_rd_out[436]
  PIN r0_rd_out[437]
    DIRECTION OUTPUT ;
    USE SIGNAL ;
    SHAPE ABUTMENT ;
    PORT
      LAYER met2 ;
      RECT 3999.170 1435.740 3999.310 1436.160 ;
    END
  END r0_rd_out[437]
  PIN r0_rd_out[438]
    DIRECTION OUTPUT ;
    USE SIGNAL ;
    SHAPE ABUTMENT ;
    PORT
      LAYER met2 ;
      RECT 4021.250 1435.740 4021.390 1436.160 ;
    END
  END r0_rd_out[438]
  PIN r0_rd_out[439]
    DIRECTION OUTPUT ;
    USE SIGNAL ;
    SHAPE ABUTMENT ;
    PORT
      LAYER met2 ;
      RECT 4043.330 1435.740 4043.470 1436.160 ;
    END
  END r0_rd_out[439]
  PIN r0_rd_out[440]
    DIRECTION OUTPUT ;
    USE SIGNAL ;
    SHAPE ABUTMENT ;
    PORT
      LAYER met2 ;
      RECT 4065.410 1435.740 4065.550 1436.160 ;
    END
  END r0_rd_out[440]
  PIN r0_rd_out[441]
    DIRECTION OUTPUT ;
    USE SIGNAL ;
    SHAPE ABUTMENT ;
    PORT
      LAYER met2 ;
      RECT 4087.490 1435.740 4087.630 1436.160 ;
    END
  END r0_rd_out[441]
  PIN r0_rd_out[442]
    DIRECTION OUTPUT ;
    USE SIGNAL ;
    SHAPE ABUTMENT ;
    PORT
      LAYER met2 ;
      RECT 4109.570 1435.740 4109.710 1436.160 ;
    END
  END r0_rd_out[442]
  PIN r0_rd_out[443]
    DIRECTION OUTPUT ;
    USE SIGNAL ;
    SHAPE ABUTMENT ;
    PORT
      LAYER met2 ;
      RECT 4131.650 1435.740 4131.790 1436.160 ;
    END
  END r0_rd_out[443]
  PIN r0_rd_out[444]
    DIRECTION OUTPUT ;
    USE SIGNAL ;
    SHAPE ABUTMENT ;
    PORT
      LAYER met2 ;
      RECT 4153.730 1435.740 4153.870 1436.160 ;
    END
  END r0_rd_out[444]
  PIN r0_rd_out[445]
    DIRECTION OUTPUT ;
    USE SIGNAL ;
    SHAPE ABUTMENT ;
    PORT
      LAYER met2 ;
      RECT 4175.810 1435.740 4175.950 1436.160 ;
    END
  END r0_rd_out[445]
  PIN r0_rd_out[446]
    DIRECTION OUTPUT ;
    USE SIGNAL ;
    SHAPE ABUTMENT ;
    PORT
      LAYER met2 ;
      RECT 4197.890 1435.740 4198.030 1436.160 ;
    END
  END r0_rd_out[446]
  PIN r0_rd_out[447]
    DIRECTION OUTPUT ;
    USE SIGNAL ;
    SHAPE ABUTMENT ;
    PORT
      LAYER met2 ;
      RECT 4219.970 1435.740 4220.110 1436.160 ;
    END
  END r0_rd_out[447]
  PIN r0_rd_out[448]
    DIRECTION OUTPUT ;
    USE SIGNAL ;
    SHAPE ABUTMENT ;
    PORT
      LAYER met2 ;
      RECT 4242.050 1435.740 4242.190 1436.160 ;
    END
  END r0_rd_out[448]
  PIN r0_rd_out[449]
    DIRECTION OUTPUT ;
    USE SIGNAL ;
    SHAPE ABUTMENT ;
    PORT
      LAYER met2 ;
      RECT 4264.130 1435.740 4264.270 1436.160 ;
    END
  END r0_rd_out[449]
  PIN r0_rd_out[450]
    DIRECTION OUTPUT ;
    USE SIGNAL ;
    SHAPE ABUTMENT ;
    PORT
      LAYER met2 ;
      RECT 4286.210 1435.740 4286.350 1436.160 ;
    END
  END r0_rd_out[450]
  PIN r0_rd_out[451]
    DIRECTION OUTPUT ;
    USE SIGNAL ;
    SHAPE ABUTMENT ;
    PORT
      LAYER met2 ;
      RECT 4308.290 1435.740 4308.430 1436.160 ;
    END
  END r0_rd_out[451]
  PIN r0_rd_out[452]
    DIRECTION OUTPUT ;
    USE SIGNAL ;
    SHAPE ABUTMENT ;
    PORT
      LAYER met2 ;
      RECT 4330.370 1435.740 4330.510 1436.160 ;
    END
  END r0_rd_out[452]
  PIN r0_rd_out[453]
    DIRECTION OUTPUT ;
    USE SIGNAL ;
    SHAPE ABUTMENT ;
    PORT
      LAYER met2 ;
      RECT 4352.450 1435.740 4352.590 1436.160 ;
    END
  END r0_rd_out[453]
  PIN r0_rd_out[454]
    DIRECTION OUTPUT ;
    USE SIGNAL ;
    SHAPE ABUTMENT ;
    PORT
      LAYER met2 ;
      RECT 4374.530 1435.740 4374.670 1436.160 ;
    END
  END r0_rd_out[454]
  PIN r0_rd_out[455]
    DIRECTION OUTPUT ;
    USE SIGNAL ;
    SHAPE ABUTMENT ;
    PORT
      LAYER met2 ;
      RECT 4396.610 1435.740 4396.750 1436.160 ;
    END
  END r0_rd_out[455]
  PIN r0_rd_out[456]
    DIRECTION OUTPUT ;
    USE SIGNAL ;
    SHAPE ABUTMENT ;
    PORT
      LAYER met2 ;
      RECT 4418.690 1435.740 4418.830 1436.160 ;
    END
  END r0_rd_out[456]
  PIN r0_rd_out[457]
    DIRECTION OUTPUT ;
    USE SIGNAL ;
    SHAPE ABUTMENT ;
    PORT
      LAYER met2 ;
      RECT 4440.770 1435.740 4440.910 1436.160 ;
    END
  END r0_rd_out[457]
  PIN r0_rd_out[458]
    DIRECTION OUTPUT ;
    USE SIGNAL ;
    SHAPE ABUTMENT ;
    PORT
      LAYER met2 ;
      RECT 4462.850 1435.740 4462.990 1436.160 ;
    END
  END r0_rd_out[458]
  PIN r0_rd_out[459]
    DIRECTION OUTPUT ;
    USE SIGNAL ;
    SHAPE ABUTMENT ;
    PORT
      LAYER met2 ;
      RECT 4484.930 1435.740 4485.070 1436.160 ;
    END
  END r0_rd_out[459]
  PIN r0_rd_out[460]
    DIRECTION OUTPUT ;
    USE SIGNAL ;
    SHAPE ABUTMENT ;
    PORT
      LAYER met2 ;
      RECT 4507.010 1435.740 4507.150 1436.160 ;
    END
  END r0_rd_out[460]
  PIN r0_rd_out[461]
    DIRECTION OUTPUT ;
    USE SIGNAL ;
    SHAPE ABUTMENT ;
    PORT
      LAYER met2 ;
      RECT 4529.090 1435.740 4529.230 1436.160 ;
    END
  END r0_rd_out[461]
  PIN r0_rd_out[462]
    DIRECTION OUTPUT ;
    USE SIGNAL ;
    SHAPE ABUTMENT ;
    PORT
      LAYER met2 ;
      RECT 4551.170 1435.740 4551.310 1436.160 ;
    END
  END r0_rd_out[462]
  PIN r0_rd_out[463]
    DIRECTION OUTPUT ;
    USE SIGNAL ;
    SHAPE ABUTMENT ;
    PORT
      LAYER met2 ;
      RECT 4573.250 1435.740 4573.390 1436.160 ;
    END
  END r0_rd_out[463]
  PIN r0_rd_out[464]
    DIRECTION OUTPUT ;
    USE SIGNAL ;
    SHAPE ABUTMENT ;
    PORT
      LAYER met2 ;
      RECT 4595.330 1435.740 4595.470 1436.160 ;
    END
  END r0_rd_out[464]
  PIN r0_rd_out[465]
    DIRECTION OUTPUT ;
    USE SIGNAL ;
    SHAPE ABUTMENT ;
    PORT
      LAYER met2 ;
      RECT 4617.410 1435.740 4617.550 1436.160 ;
    END
  END r0_rd_out[465]
  PIN r0_rd_out[466]
    DIRECTION OUTPUT ;
    USE SIGNAL ;
    SHAPE ABUTMENT ;
    PORT
      LAYER met2 ;
      RECT 4639.490 1435.740 4639.630 1436.160 ;
    END
  END r0_rd_out[466]
  PIN r0_rd_out[467]
    DIRECTION OUTPUT ;
    USE SIGNAL ;
    SHAPE ABUTMENT ;
    PORT
      LAYER met2 ;
      RECT 4661.570 1435.740 4661.710 1436.160 ;
    END
  END r0_rd_out[467]
  PIN r0_rd_out[468]
    DIRECTION OUTPUT ;
    USE SIGNAL ;
    SHAPE ABUTMENT ;
    PORT
      LAYER met2 ;
      RECT 4683.650 1435.740 4683.790 1436.160 ;
    END
  END r0_rd_out[468]
  PIN r0_rd_out[469]
    DIRECTION OUTPUT ;
    USE SIGNAL ;
    SHAPE ABUTMENT ;
    PORT
      LAYER met2 ;
      RECT 4705.730 1435.740 4705.870 1436.160 ;
    END
  END r0_rd_out[469]
  PIN r0_rd_out[470]
    DIRECTION OUTPUT ;
    USE SIGNAL ;
    SHAPE ABUTMENT ;
    PORT
      LAYER met2 ;
      RECT 4727.810 1435.740 4727.950 1436.160 ;
    END
  END r0_rd_out[470]
  PIN r0_rd_out[471]
    DIRECTION OUTPUT ;
    USE SIGNAL ;
    SHAPE ABUTMENT ;
    PORT
      LAYER met2 ;
      RECT 4749.890 1435.740 4750.030 1436.160 ;
    END
  END r0_rd_out[471]
  PIN r0_rd_out[472]
    DIRECTION OUTPUT ;
    USE SIGNAL ;
    SHAPE ABUTMENT ;
    PORT
      LAYER met2 ;
      RECT 4771.970 1435.740 4772.110 1436.160 ;
    END
  END r0_rd_out[472]
  PIN r0_rd_out[473]
    DIRECTION OUTPUT ;
    USE SIGNAL ;
    SHAPE ABUTMENT ;
    PORT
      LAYER met2 ;
      RECT 4794.050 1435.740 4794.190 1436.160 ;
    END
  END r0_rd_out[473]
  PIN r0_rd_out[474]
    DIRECTION OUTPUT ;
    USE SIGNAL ;
    SHAPE ABUTMENT ;
    PORT
      LAYER met2 ;
      RECT 4816.130 1435.740 4816.270 1436.160 ;
    END
  END r0_rd_out[474]
  PIN r0_rd_out[475]
    DIRECTION OUTPUT ;
    USE SIGNAL ;
    SHAPE ABUTMENT ;
    PORT
      LAYER met2 ;
      RECT 4838.210 1435.740 4838.350 1436.160 ;
    END
  END r0_rd_out[475]
  PIN r0_rd_out[476]
    DIRECTION OUTPUT ;
    USE SIGNAL ;
    SHAPE ABUTMENT ;
    PORT
      LAYER met2 ;
      RECT 4860.290 1435.740 4860.430 1436.160 ;
    END
  END r0_rd_out[476]
  PIN r0_rd_out[477]
    DIRECTION OUTPUT ;
    USE SIGNAL ;
    SHAPE ABUTMENT ;
    PORT
      LAYER met2 ;
      RECT 4882.370 1435.740 4882.510 1436.160 ;
    END
  END r0_rd_out[477]
  PIN r0_rd_out[478]
    DIRECTION OUTPUT ;
    USE SIGNAL ;
    SHAPE ABUTMENT ;
    PORT
      LAYER met2 ;
      RECT 4904.450 1435.740 4904.590 1436.160 ;
    END
  END r0_rd_out[478]
  PIN r0_rd_out[479]
    DIRECTION OUTPUT ;
    USE SIGNAL ;
    SHAPE ABUTMENT ;
    PORT
      LAYER met2 ;
      RECT 4926.530 1435.740 4926.670 1436.160 ;
    END
  END r0_rd_out[479]
  PIN r0_rd_out[480]
    DIRECTION OUTPUT ;
    USE SIGNAL ;
    SHAPE ABUTMENT ;
    PORT
      LAYER met2 ;
      RECT 4948.610 1435.740 4948.750 1436.160 ;
    END
  END r0_rd_out[480]
  PIN r0_rd_out[481]
    DIRECTION OUTPUT ;
    USE SIGNAL ;
    SHAPE ABUTMENT ;
    PORT
      LAYER met2 ;
      RECT 4970.690 1435.740 4970.830 1436.160 ;
    END
  END r0_rd_out[481]
  PIN r0_rd_out[482]
    DIRECTION OUTPUT ;
    USE SIGNAL ;
    SHAPE ABUTMENT ;
    PORT
      LAYER met2 ;
      RECT 4992.770 1435.740 4992.910 1436.160 ;
    END
  END r0_rd_out[482]
  PIN r0_rd_out[483]
    DIRECTION OUTPUT ;
    USE SIGNAL ;
    SHAPE ABUTMENT ;
    PORT
      LAYER met2 ;
      RECT 5014.850 1435.740 5014.990 1436.160 ;
    END
  END r0_rd_out[483]
  PIN r0_rd_out[484]
    DIRECTION OUTPUT ;
    USE SIGNAL ;
    SHAPE ABUTMENT ;
    PORT
      LAYER met2 ;
      RECT 5036.930 1435.740 5037.070 1436.160 ;
    END
  END r0_rd_out[484]
  PIN r0_rd_out[485]
    DIRECTION OUTPUT ;
    USE SIGNAL ;
    SHAPE ABUTMENT ;
    PORT
      LAYER met2 ;
      RECT 5059.010 1435.740 5059.150 1436.160 ;
    END
  END r0_rd_out[485]
  PIN r0_rd_out[486]
    DIRECTION OUTPUT ;
    USE SIGNAL ;
    SHAPE ABUTMENT ;
    PORT
      LAYER met2 ;
      RECT 5081.090 1435.740 5081.230 1436.160 ;
    END
  END r0_rd_out[486]
  PIN r0_rd_out[487]
    DIRECTION OUTPUT ;
    USE SIGNAL ;
    SHAPE ABUTMENT ;
    PORT
      LAYER met2 ;
      RECT 5103.170 1435.740 5103.310 1436.160 ;
    END
  END r0_rd_out[487]
  PIN r0_rd_out[488]
    DIRECTION OUTPUT ;
    USE SIGNAL ;
    SHAPE ABUTMENT ;
    PORT
      LAYER met2 ;
      RECT 5125.250 1435.740 5125.390 1436.160 ;
    END
  END r0_rd_out[488]
  PIN r0_rd_out[489]
    DIRECTION OUTPUT ;
    USE SIGNAL ;
    SHAPE ABUTMENT ;
    PORT
      LAYER met2 ;
      RECT 5147.330 1435.740 5147.470 1436.160 ;
    END
  END r0_rd_out[489]
  PIN r0_rd_out[490]
    DIRECTION OUTPUT ;
    USE SIGNAL ;
    SHAPE ABUTMENT ;
    PORT
      LAYER met2 ;
      RECT 5169.410 1435.740 5169.550 1436.160 ;
    END
  END r0_rd_out[490]
  PIN r0_rd_out[491]
    DIRECTION OUTPUT ;
    USE SIGNAL ;
    SHAPE ABUTMENT ;
    PORT
      LAYER met2 ;
      RECT 5191.490 1435.740 5191.630 1436.160 ;
    END
  END r0_rd_out[491]
  PIN r0_rd_out[492]
    DIRECTION OUTPUT ;
    USE SIGNAL ;
    SHAPE ABUTMENT ;
    PORT
      LAYER met2 ;
      RECT 5213.570 1435.740 5213.710 1436.160 ;
    END
  END r0_rd_out[492]
  PIN r0_rd_out[493]
    DIRECTION OUTPUT ;
    USE SIGNAL ;
    SHAPE ABUTMENT ;
    PORT
      LAYER met2 ;
      RECT 5235.650 1435.740 5235.790 1436.160 ;
    END
  END r0_rd_out[493]
  PIN r0_rd_out[494]
    DIRECTION OUTPUT ;
    USE SIGNAL ;
    SHAPE ABUTMENT ;
    PORT
      LAYER met2 ;
      RECT 5257.730 1435.740 5257.870 1436.160 ;
    END
  END r0_rd_out[494]
  PIN r0_rd_out[495]
    DIRECTION OUTPUT ;
    USE SIGNAL ;
    SHAPE ABUTMENT ;
    PORT
      LAYER met2 ;
      RECT 5279.810 1435.740 5279.950 1436.160 ;
    END
  END r0_rd_out[495]
  PIN r0_rd_out[496]
    DIRECTION OUTPUT ;
    USE SIGNAL ;
    SHAPE ABUTMENT ;
    PORT
      LAYER met2 ;
      RECT 5301.890 1435.740 5302.030 1436.160 ;
    END
  END r0_rd_out[496]
  PIN r0_rd_out[497]
    DIRECTION OUTPUT ;
    USE SIGNAL ;
    SHAPE ABUTMENT ;
    PORT
      LAYER met2 ;
      RECT 5323.970 1435.740 5324.110 1436.160 ;
    END
  END r0_rd_out[497]
  PIN r0_rd_out[498]
    DIRECTION OUTPUT ;
    USE SIGNAL ;
    SHAPE ABUTMENT ;
    PORT
      LAYER met2 ;
      RECT 5346.050 1435.740 5346.190 1436.160 ;
    END
  END r0_rd_out[498]
  PIN r0_rd_out[499]
    DIRECTION OUTPUT ;
    USE SIGNAL ;
    SHAPE ABUTMENT ;
    PORT
      LAYER met2 ;
      RECT 5368.130 1435.740 5368.270 1436.160 ;
    END
  END r0_rd_out[499]
  PIN r0_rd_out[500]
    DIRECTION OUTPUT ;
    USE SIGNAL ;
    SHAPE ABUTMENT ;
    PORT
      LAYER met2 ;
      RECT 5390.210 1435.740 5390.350 1436.160 ;
    END
  END r0_rd_out[500]
  PIN r0_rd_out[501]
    DIRECTION OUTPUT ;
    USE SIGNAL ;
    SHAPE ABUTMENT ;
    PORT
      LAYER met2 ;
      RECT 5412.290 1435.740 5412.430 1436.160 ;
    END
  END r0_rd_out[501]
  PIN r0_rd_out[502]
    DIRECTION OUTPUT ;
    USE SIGNAL ;
    SHAPE ABUTMENT ;
    PORT
      LAYER met2 ;
      RECT 5434.370 1435.740 5434.510 1436.160 ;
    END
  END r0_rd_out[502]
  PIN r0_rd_out[503]
    DIRECTION OUTPUT ;
    USE SIGNAL ;
    SHAPE ABUTMENT ;
    PORT
      LAYER met2 ;
      RECT 5456.450 1435.740 5456.590 1436.160 ;
    END
  END r0_rd_out[503]
  PIN r0_rd_out[504]
    DIRECTION OUTPUT ;
    USE SIGNAL ;
    SHAPE ABUTMENT ;
    PORT
      LAYER met2 ;
      RECT 5478.530 1435.740 5478.670 1436.160 ;
    END
  END r0_rd_out[504]
  PIN r0_rd_out[505]
    DIRECTION OUTPUT ;
    USE SIGNAL ;
    SHAPE ABUTMENT ;
    PORT
      LAYER met2 ;
      RECT 5500.610 1435.740 5500.750 1436.160 ;
    END
  END r0_rd_out[505]
  PIN r0_rd_out[506]
    DIRECTION OUTPUT ;
    USE SIGNAL ;
    SHAPE ABUTMENT ;
    PORT
      LAYER met2 ;
      RECT 5522.690 1435.740 5522.830 1436.160 ;
    END
  END r0_rd_out[506]
  PIN r0_rd_out[507]
    DIRECTION OUTPUT ;
    USE SIGNAL ;
    SHAPE ABUTMENT ;
    PORT
      LAYER met2 ;
      RECT 5544.770 1435.740 5544.910 1436.160 ;
    END
  END r0_rd_out[507]
  PIN r0_rd_out[508]
    DIRECTION OUTPUT ;
    USE SIGNAL ;
    SHAPE ABUTMENT ;
    PORT
      LAYER met2 ;
      RECT 5566.850 1435.740 5566.990 1436.160 ;
    END
  END r0_rd_out[508]
  PIN r0_rd_out[509]
    DIRECTION OUTPUT ;
    USE SIGNAL ;
    SHAPE ABUTMENT ;
    PORT
      LAYER met2 ;
      RECT 5588.930 1435.740 5589.070 1436.160 ;
    END
  END r0_rd_out[509]
  PIN r0_rd_out[510]
    DIRECTION OUTPUT ;
    USE SIGNAL ;
    SHAPE ABUTMENT ;
    PORT
      LAYER met2 ;
      RECT 5611.010 1435.740 5611.150 1436.160 ;
    END
  END r0_rd_out[510]
  PIN r0_rd_out[511]
    DIRECTION OUTPUT ;
    USE SIGNAL ;
    SHAPE ABUTMENT ;
    PORT
      LAYER met2 ;
      RECT 5633.090 1435.740 5633.230 1436.160 ;
    END
  END r0_rd_out[511]
  PIN w0_addr_in[0]
    DIRECTION INPUT ;
    USE SIGNAL ;
    SHAPE ABUTMENT ;
    PORT
      LAYER met3 ;
      RECT 0.000 1309.530 0.900 1309.830 ;
    END
  END w0_addr_in[0]
  PIN w0_addr_in[1]
    DIRECTION INPUT ;
    USE SIGNAL ;
    SHAPE ABUTMENT ;
    PORT
      LAYER met3 ;
      RECT 0.000 1319.730 0.900 1320.030 ;
    END
  END w0_addr_in[1]
  PIN w0_addr_in[2]
    DIRECTION INPUT ;
    USE SIGNAL ;
    SHAPE ABUTMENT ;
    PORT
      LAYER met3 ;
      RECT 0.000 1329.930 0.900 1330.230 ;
    END
  END w0_addr_in[2]
  PIN w0_addr_in[3]
    DIRECTION INPUT ;
    USE SIGNAL ;
    SHAPE ABUTMENT ;
    PORT
      LAYER met3 ;
      RECT 0.000 1340.130 0.900 1340.430 ;
    END
  END w0_addr_in[3]
  PIN w0_addr_in[4]
    DIRECTION INPUT ;
    USE SIGNAL ;
    SHAPE ABUTMENT ;
    PORT
      LAYER met3 ;
      RECT 0.000 1350.330 0.900 1350.630 ;
    END
  END w0_addr_in[4]
  PIN w0_addr_in[5]
    DIRECTION INPUT ;
    USE SIGNAL ;
    SHAPE ABUTMENT ;
    PORT
      LAYER met3 ;
      RECT 0.000 1360.530 0.900 1360.830 ;
    END
  END w0_addr_in[5]
  PIN w0_addr_in[6]
    DIRECTION INPUT ;
    USE SIGNAL ;
    SHAPE ABUTMENT ;
    PORT
      LAYER met3 ;
      RECT 5871.000 1309.530 5871.900 1309.830 ;
    END
  END w0_addr_in[6]
  PIN w0_addr_in[7]
    DIRECTION INPUT ;
    USE SIGNAL ;
    SHAPE ABUTMENT ;
    PORT
      LAYER met3 ;
      RECT 5871.000 1319.730 5871.900 1320.030 ;
    END
  END w0_addr_in[7]
  PIN w0_addr_in[8]
    DIRECTION INPUT ;
    USE SIGNAL ;
    SHAPE ABUTMENT ;
    PORT
      LAYER met3 ;
      RECT 5871.000 1329.930 5871.900 1330.230 ;
    END
  END w0_addr_in[8]
  PIN w0_addr_in[9]
    DIRECTION INPUT ;
    USE SIGNAL ;
    SHAPE ABUTMENT ;
    PORT
      LAYER met3 ;
      RECT 5871.000 1340.130 5871.900 1340.430 ;
    END
  END w0_addr_in[9]
  PIN w0_addr_in[10]
    DIRECTION INPUT ;
    USE SIGNAL ;
    SHAPE ABUTMENT ;
    PORT
      LAYER met3 ;
      RECT 5871.000 1350.330 5871.900 1350.630 ;
    END
  END w0_addr_in[10]
  PIN r0_addr_in[0]
    DIRECTION INPUT ;
    USE SIGNAL ;
    SHAPE ABUTMENT ;
    PORT
      LAYER met3 ;
      RECT 0.000 1370.730 0.900 1371.030 ;
    END
  END r0_addr_in[0]
  PIN r0_addr_in[1]
    DIRECTION INPUT ;
    USE SIGNAL ;
    SHAPE ABUTMENT ;
    PORT
      LAYER met3 ;
      RECT 0.000 1380.930 0.900 1381.230 ;
    END
  END r0_addr_in[1]
  PIN r0_addr_in[2]
    DIRECTION INPUT ;
    USE SIGNAL ;
    SHAPE ABUTMENT ;
    PORT
      LAYER met3 ;
      RECT 0.000 1391.130 0.900 1391.430 ;
    END
  END r0_addr_in[2]
  PIN r0_addr_in[3]
    DIRECTION INPUT ;
    USE SIGNAL ;
    SHAPE ABUTMENT ;
    PORT
      LAYER met3 ;
      RECT 0.000 1401.330 0.900 1401.630 ;
    END
  END r0_addr_in[3]
  PIN r0_addr_in[4]
    DIRECTION INPUT ;
    USE SIGNAL ;
    SHAPE ABUTMENT ;
    PORT
      LAYER met3 ;
      RECT 0.000 1411.530 0.900 1411.830 ;
    END
  END r0_addr_in[4]
  PIN r0_addr_in[5]
    DIRECTION INPUT ;
    USE SIGNAL ;
    SHAPE ABUTMENT ;
    PORT
      LAYER met3 ;
      RECT 0.000 1421.730 0.900 1422.030 ;
    END
  END r0_addr_in[5]
  PIN r0_addr_in[6]
    DIRECTION INPUT ;
    USE SIGNAL ;
    SHAPE ABUTMENT ;
    PORT
      LAYER met3 ;
      RECT 5871.000 1360.530 5871.900 1360.830 ;
    END
  END r0_addr_in[6]
  PIN r0_addr_in[7]
    DIRECTION INPUT ;
    USE SIGNAL ;
    SHAPE ABUTMENT ;
    PORT
      LAYER met3 ;
      RECT 5871.000 1370.730 5871.900 1371.030 ;
    END
  END r0_addr_in[7]
  PIN r0_addr_in[8]
    DIRECTION INPUT ;
    USE SIGNAL ;
    SHAPE ABUTMENT ;
    PORT
      LAYER met3 ;
      RECT 5871.000 1380.930 5871.900 1381.230 ;
    END
  END r0_addr_in[8]
  PIN r0_addr_in[9]
    DIRECTION INPUT ;
    USE SIGNAL ;
    SHAPE ABUTMENT ;
    PORT
      LAYER met3 ;
      RECT 5871.000 1391.130 5871.900 1391.430 ;
    END
  END r0_addr_in[9]
  PIN r0_addr_in[10]
    DIRECTION INPUT ;
    USE SIGNAL ;
    SHAPE ABUTMENT ;
    PORT
      LAYER met3 ;
      RECT 5871.000 1401.330 5871.900 1401.630 ;
    END
  END r0_addr_in[10]
  PIN w0_we_in
    DIRECTION INPUT ;
    USE SIGNAL ;
    SHAPE ABUTMENT ;
    PORT
      LAYER met2 ;
      RECT 5655.170 1435.740 5655.310 1436.160 ;
    END
  END w0_we_in
  PIN w0_ce_in
    DIRECTION INPUT ;
    USE SIGNAL ;
    SHAPE ABUTMENT ;
    PORT
      LAYER met2 ;
      RECT 5677.250 1435.740 5677.390 1436.160 ;
    END
  END w0_ce_in
  PIN w0_clk
    DIRECTION INPUT ;
    USE SIGNAL ;
    SHAPE ABUTMENT ;
    PORT
      LAYER met2 ;
      RECT 5699.330 1435.740 5699.470 1436.160 ;
    END
  END w0_clk
  PIN r0_ce_in
    DIRECTION INPUT ;
    USE SIGNAL ;
    SHAPE ABUTMENT ;
    PORT
      LAYER met2 ;
      RECT 5721.410 1435.740 5721.550 1436.160 ;
    END
  END r0_ce_in
  PIN r0_clk
    DIRECTION INPUT ;
    USE SIGNAL ;
    SHAPE ABUTMENT ;
    PORT
      LAYER met2 ;
      RECT 5743.490 1435.740 5743.630 1436.160 ;
    END
  END r0_clk
  PIN VSS
    DIRECTION INOUT ;
    USE GROUND ;
    PORT
      LAYER met4 ;
      RECT 2.160 4.080 3.360 1432.080 ;
      RECT 13.040 4.080 14.240 1432.080 ;
      RECT 23.920 4.080 25.120 1432.080 ;
      RECT 34.800 4.080 36.000 1432.080 ;
      RECT 45.680 4.080 46.880 1432.080 ;
      RECT 56.560 4.080 57.760 1432.080 ;
      RECT 67.440 4.080 68.640 1432.080 ;
      RECT 78.320 4.080 79.520 1432.080 ;
      RECT 89.200 4.080 90.400 1432.080 ;
      RECT 100.080 4.080 101.280 1432.080 ;
      RECT 110.960 4.080 112.160 1432.080 ;
      RECT 121.840 4.080 123.040 1432.080 ;
      RECT 132.720 4.080 133.920 1432.080 ;
      RECT 143.600 4.080 144.800 1432.080 ;
      RECT 154.480 4.080 155.680 1432.080 ;
      RECT 165.360 4.080 166.560 1432.080 ;
      RECT 176.240 4.080 177.440 1432.080 ;
      RECT 187.120 4.080 188.320 1432.080 ;
      RECT 198.000 4.080 199.200 1432.080 ;
      RECT 208.880 4.080 210.080 1432.080 ;
      RECT 219.760 4.080 220.960 1432.080 ;
      RECT 230.640 4.080 231.840 1432.080 ;
      RECT 241.520 4.080 242.720 1432.080 ;
      RECT 252.400 4.080 253.600 1432.080 ;
      RECT 263.280 4.080 264.480 1432.080 ;
      RECT 274.160 4.080 275.360 1432.080 ;
      RECT 285.040 4.080 286.240 1432.080 ;
      RECT 295.920 4.080 297.120 1432.080 ;
      RECT 306.800 4.080 308.000 1432.080 ;
      RECT 317.680 4.080 318.880 1432.080 ;
      RECT 328.560 4.080 329.760 1432.080 ;
      RECT 339.440 4.080 340.640 1432.080 ;
      RECT 350.320 4.080 351.520 1432.080 ;
      RECT 361.200 4.080 362.400 1432.080 ;
      RECT 372.080 4.080 373.280 1432.080 ;
      RECT 382.960 4.080 384.160 1432.080 ;
      RECT 393.840 4.080 395.040 1432.080 ;
      RECT 404.720 4.080 405.920 1432.080 ;
      RECT 415.600 4.080 416.800 1432.080 ;
      RECT 426.480 4.080 427.680 1432.080 ;
      RECT 437.360 4.080 438.560 1432.080 ;
      RECT 448.240 4.080 449.440 1432.080 ;
      RECT 459.120 4.080 460.320 1432.080 ;
      RECT 470.000 4.080 471.200 1432.080 ;
      RECT 480.880 4.080 482.080 1432.080 ;
      RECT 491.760 4.080 492.960 1432.080 ;
      RECT 502.640 4.080 503.840 1432.080 ;
      RECT 513.520 4.080 514.720 1432.080 ;
      RECT 524.400 4.080 525.600 1432.080 ;
      RECT 535.280 4.080 536.480 1432.080 ;
      RECT 546.160 4.080 547.360 1432.080 ;
      RECT 557.040 4.080 558.240 1432.080 ;
      RECT 567.920 4.080 569.120 1432.080 ;
      RECT 578.800 4.080 580.000 1432.080 ;
      RECT 589.680 4.080 590.880 1432.080 ;
      RECT 600.560 4.080 601.760 1432.080 ;
      RECT 611.440 4.080 612.640 1432.080 ;
      RECT 622.320 4.080 623.520 1432.080 ;
      RECT 633.200 4.080 634.400 1432.080 ;
      RECT 644.080 4.080 645.280 1432.080 ;
      RECT 654.960 4.080 656.160 1432.080 ;
      RECT 665.840 4.080 667.040 1432.080 ;
      RECT 676.720 4.080 677.920 1432.080 ;
      RECT 687.600 4.080 688.800 1432.080 ;
      RECT 698.480 4.080 699.680 1432.080 ;
      RECT 709.360 4.080 710.560 1432.080 ;
      RECT 720.240 4.080 721.440 1432.080 ;
      RECT 731.120 4.080 732.320 1432.080 ;
      RECT 742.000 4.080 743.200 1432.080 ;
      RECT 752.880 4.080 754.080 1432.080 ;
      RECT 763.760 4.080 764.960 1432.080 ;
      RECT 774.640 4.080 775.840 1432.080 ;
      RECT 785.520 4.080 786.720 1432.080 ;
      RECT 796.400 4.080 797.600 1432.080 ;
      RECT 807.280 4.080 808.480 1432.080 ;
      RECT 818.160 4.080 819.360 1432.080 ;
      RECT 829.040 4.080 830.240 1432.080 ;
      RECT 839.920 4.080 841.120 1432.080 ;
      RECT 850.800 4.080 852.000 1432.080 ;
      RECT 861.680 4.080 862.880 1432.080 ;
      RECT 872.560 4.080 873.760 1432.080 ;
      RECT 883.440 4.080 884.640 1432.080 ;
      RECT 894.320 4.080 895.520 1432.080 ;
      RECT 905.200 4.080 906.400 1432.080 ;
      RECT 916.080 4.080 917.280 1432.080 ;
      RECT 926.960 4.080 928.160 1432.080 ;
      RECT 937.840 4.080 939.040 1432.080 ;
      RECT 948.720 4.080 949.920 1432.080 ;
      RECT 959.600 4.080 960.800 1432.080 ;
      RECT 970.480 4.080 971.680 1432.080 ;
      RECT 981.360 4.080 982.560 1432.080 ;
      RECT 992.240 4.080 993.440 1432.080 ;
      RECT 1003.120 4.080 1004.320 1432.080 ;
      RECT 1014.000 4.080 1015.200 1432.080 ;
      RECT 1024.880 4.080 1026.080 1432.080 ;
      RECT 1035.760 4.080 1036.960 1432.080 ;
      RECT 1046.640 4.080 1047.840 1432.080 ;
      RECT 1057.520 4.080 1058.720 1432.080 ;
      RECT 1068.400 4.080 1069.600 1432.080 ;
      RECT 1079.280 4.080 1080.480 1432.080 ;
      RECT 1090.160 4.080 1091.360 1432.080 ;
      RECT 1101.040 4.080 1102.240 1432.080 ;
      RECT 1111.920 4.080 1113.120 1432.080 ;
      RECT 1122.800 4.080 1124.000 1432.080 ;
      RECT 1133.680 4.080 1134.880 1432.080 ;
      RECT 1144.560 4.080 1145.760 1432.080 ;
      RECT 1155.440 4.080 1156.640 1432.080 ;
      RECT 1166.320 4.080 1167.520 1432.080 ;
      RECT 1177.200 4.080 1178.400 1432.080 ;
      RECT 1188.080 4.080 1189.280 1432.080 ;
      RECT 1198.960 4.080 1200.160 1432.080 ;
      RECT 1209.840 4.080 1211.040 1432.080 ;
      RECT 1220.720 4.080 1221.920 1432.080 ;
      RECT 1231.600 4.080 1232.800 1432.080 ;
      RECT 1242.480 4.080 1243.680 1432.080 ;
      RECT 1253.360 4.080 1254.560 1432.080 ;
      RECT 1264.240 4.080 1265.440 1432.080 ;
      RECT 1275.120 4.080 1276.320 1432.080 ;
      RECT 1286.000 4.080 1287.200 1432.080 ;
      RECT 1296.880 4.080 1298.080 1432.080 ;
      RECT 1307.760 4.080 1308.960 1432.080 ;
      RECT 1318.640 4.080 1319.840 1432.080 ;
      RECT 1329.520 4.080 1330.720 1432.080 ;
      RECT 1340.400 4.080 1341.600 1432.080 ;
      RECT 1351.280 4.080 1352.480 1432.080 ;
      RECT 1362.160 4.080 1363.360 1432.080 ;
      RECT 1373.040 4.080 1374.240 1432.080 ;
      RECT 1383.920 4.080 1385.120 1432.080 ;
      RECT 1394.800 4.080 1396.000 1432.080 ;
      RECT 1405.680 4.080 1406.880 1432.080 ;
      RECT 1416.560 4.080 1417.760 1432.080 ;
      RECT 1427.440 4.080 1428.640 1432.080 ;
      RECT 1438.320 4.080 1439.520 1432.080 ;
      RECT 1449.200 4.080 1450.400 1432.080 ;
      RECT 1460.080 4.080 1461.280 1432.080 ;
      RECT 1470.960 4.080 1472.160 1432.080 ;
      RECT 1481.840 4.080 1483.040 1432.080 ;
      RECT 1492.720 4.080 1493.920 1432.080 ;
      RECT 1503.600 4.080 1504.800 1432.080 ;
      RECT 1514.480 4.080 1515.680 1432.080 ;
      RECT 1525.360 4.080 1526.560 1432.080 ;
      RECT 1536.240 4.080 1537.440 1432.080 ;
      RECT 1547.120 4.080 1548.320 1432.080 ;
      RECT 1558.000 4.080 1559.200 1432.080 ;
      RECT 1568.880 4.080 1570.080 1432.080 ;
      RECT 1579.760 4.080 1580.960 1432.080 ;
      RECT 1590.640 4.080 1591.840 1432.080 ;
      RECT 1601.520 4.080 1602.720 1432.080 ;
      RECT 1612.400 4.080 1613.600 1432.080 ;
      RECT 1623.280 4.080 1624.480 1432.080 ;
      RECT 1634.160 4.080 1635.360 1432.080 ;
      RECT 1645.040 4.080 1646.240 1432.080 ;
      RECT 1655.920 4.080 1657.120 1432.080 ;
      RECT 1666.800 4.080 1668.000 1432.080 ;
      RECT 1677.680 4.080 1678.880 1432.080 ;
      RECT 1688.560 4.080 1689.760 1432.080 ;
      RECT 1699.440 4.080 1700.640 1432.080 ;
      RECT 1710.320 4.080 1711.520 1432.080 ;
      RECT 1721.200 4.080 1722.400 1432.080 ;
      RECT 1732.080 4.080 1733.280 1432.080 ;
      RECT 1742.960 4.080 1744.160 1432.080 ;
      RECT 1753.840 4.080 1755.040 1432.080 ;
      RECT 1764.720 4.080 1765.920 1432.080 ;
      RECT 1775.600 4.080 1776.800 1432.080 ;
      RECT 1786.480 4.080 1787.680 1432.080 ;
      RECT 1797.360 4.080 1798.560 1432.080 ;
      RECT 1808.240 4.080 1809.440 1432.080 ;
      RECT 1819.120 4.080 1820.320 1432.080 ;
      RECT 1830.000 4.080 1831.200 1432.080 ;
      RECT 1840.880 4.080 1842.080 1432.080 ;
      RECT 1851.760 4.080 1852.960 1432.080 ;
      RECT 1862.640 4.080 1863.840 1432.080 ;
      RECT 1873.520 4.080 1874.720 1432.080 ;
      RECT 1884.400 4.080 1885.600 1432.080 ;
      RECT 1895.280 4.080 1896.480 1432.080 ;
      RECT 1906.160 4.080 1907.360 1432.080 ;
      RECT 1917.040 4.080 1918.240 1432.080 ;
      RECT 1927.920 4.080 1929.120 1432.080 ;
      RECT 1938.800 4.080 1940.000 1432.080 ;
      RECT 1949.680 4.080 1950.880 1432.080 ;
      RECT 1960.560 4.080 1961.760 1432.080 ;
      RECT 1971.440 4.080 1972.640 1432.080 ;
      RECT 1982.320 4.080 1983.520 1432.080 ;
      RECT 1993.200 4.080 1994.400 1432.080 ;
      RECT 2004.080 4.080 2005.280 1432.080 ;
      RECT 2014.960 4.080 2016.160 1432.080 ;
      RECT 2025.840 4.080 2027.040 1432.080 ;
      RECT 2036.720 4.080 2037.920 1432.080 ;
      RECT 2047.600 4.080 2048.800 1432.080 ;
      RECT 2058.480 4.080 2059.680 1432.080 ;
      RECT 2069.360 4.080 2070.560 1432.080 ;
      RECT 2080.240 4.080 2081.440 1432.080 ;
      RECT 2091.120 4.080 2092.320 1432.080 ;
      RECT 2102.000 4.080 2103.200 1432.080 ;
      RECT 2112.880 4.080 2114.080 1432.080 ;
      RECT 2123.760 4.080 2124.960 1432.080 ;
      RECT 2134.640 4.080 2135.840 1432.080 ;
      RECT 2145.520 4.080 2146.720 1432.080 ;
      RECT 2156.400 4.080 2157.600 1432.080 ;
      RECT 2167.280 4.080 2168.480 1432.080 ;
      RECT 2178.160 4.080 2179.360 1432.080 ;
      RECT 2189.040 4.080 2190.240 1432.080 ;
      RECT 2199.920 4.080 2201.120 1432.080 ;
      RECT 2210.800 4.080 2212.000 1432.080 ;
      RECT 2221.680 4.080 2222.880 1432.080 ;
      RECT 2232.560 4.080 2233.760 1432.080 ;
      RECT 2243.440 4.080 2244.640 1432.080 ;
      RECT 2254.320 4.080 2255.520 1432.080 ;
      RECT 2265.200 4.080 2266.400 1432.080 ;
      RECT 2276.080 4.080 2277.280 1432.080 ;
      RECT 2286.960 4.080 2288.160 1432.080 ;
      RECT 2297.840 4.080 2299.040 1432.080 ;
      RECT 2308.720 4.080 2309.920 1432.080 ;
      RECT 2319.600 4.080 2320.800 1432.080 ;
      RECT 2330.480 4.080 2331.680 1432.080 ;
      RECT 2341.360 4.080 2342.560 1432.080 ;
      RECT 2352.240 4.080 2353.440 1432.080 ;
      RECT 2363.120 4.080 2364.320 1432.080 ;
      RECT 2374.000 4.080 2375.200 1432.080 ;
      RECT 2384.880 4.080 2386.080 1432.080 ;
      RECT 2395.760 4.080 2396.960 1432.080 ;
      RECT 2406.640 4.080 2407.840 1432.080 ;
      RECT 2417.520 4.080 2418.720 1432.080 ;
      RECT 2428.400 4.080 2429.600 1432.080 ;
      RECT 2439.280 4.080 2440.480 1432.080 ;
      RECT 2450.160 4.080 2451.360 1432.080 ;
      RECT 2461.040 4.080 2462.240 1432.080 ;
      RECT 2471.920 4.080 2473.120 1432.080 ;
      RECT 2482.800 4.080 2484.000 1432.080 ;
      RECT 2493.680 4.080 2494.880 1432.080 ;
      RECT 2504.560 4.080 2505.760 1432.080 ;
      RECT 2515.440 4.080 2516.640 1432.080 ;
      RECT 2526.320 4.080 2527.520 1432.080 ;
      RECT 2537.200 4.080 2538.400 1432.080 ;
      RECT 2548.080 4.080 2549.280 1432.080 ;
      RECT 2558.960 4.080 2560.160 1432.080 ;
      RECT 2569.840 4.080 2571.040 1432.080 ;
      RECT 2580.720 4.080 2581.920 1432.080 ;
      RECT 2591.600 4.080 2592.800 1432.080 ;
      RECT 2602.480 4.080 2603.680 1432.080 ;
      RECT 2613.360 4.080 2614.560 1432.080 ;
      RECT 2624.240 4.080 2625.440 1432.080 ;
      RECT 2635.120 4.080 2636.320 1432.080 ;
      RECT 2646.000 4.080 2647.200 1432.080 ;
      RECT 2656.880 4.080 2658.080 1432.080 ;
      RECT 2667.760 4.080 2668.960 1432.080 ;
      RECT 2678.640 4.080 2679.840 1432.080 ;
      RECT 2689.520 4.080 2690.720 1432.080 ;
      RECT 2700.400 4.080 2701.600 1432.080 ;
      RECT 2711.280 4.080 2712.480 1432.080 ;
      RECT 2722.160 4.080 2723.360 1432.080 ;
      RECT 2733.040 4.080 2734.240 1432.080 ;
      RECT 2743.920 4.080 2745.120 1432.080 ;
      RECT 2754.800 4.080 2756.000 1432.080 ;
      RECT 2765.680 4.080 2766.880 1432.080 ;
      RECT 2776.560 4.080 2777.760 1432.080 ;
      RECT 2787.440 4.080 2788.640 1432.080 ;
      RECT 2798.320 4.080 2799.520 1432.080 ;
      RECT 2809.200 4.080 2810.400 1432.080 ;
      RECT 2820.080 4.080 2821.280 1432.080 ;
      RECT 2830.960 4.080 2832.160 1432.080 ;
      RECT 2841.840 4.080 2843.040 1432.080 ;
      RECT 2852.720 4.080 2853.920 1432.080 ;
      RECT 2863.600 4.080 2864.800 1432.080 ;
      RECT 2874.480 4.080 2875.680 1432.080 ;
      RECT 2885.360 4.080 2886.560 1432.080 ;
      RECT 2896.240 4.080 2897.440 1432.080 ;
      RECT 2907.120 4.080 2908.320 1432.080 ;
      RECT 2918.000 4.080 2919.200 1432.080 ;
      RECT 2928.880 4.080 2930.080 1432.080 ;
      RECT 2939.760 4.080 2940.960 1432.080 ;
      RECT 2950.640 4.080 2951.840 1432.080 ;
      RECT 2961.520 4.080 2962.720 1432.080 ;
      RECT 2972.400 4.080 2973.600 1432.080 ;
      RECT 2983.280 4.080 2984.480 1432.080 ;
      RECT 2994.160 4.080 2995.360 1432.080 ;
      RECT 3005.040 4.080 3006.240 1432.080 ;
      RECT 3015.920 4.080 3017.120 1432.080 ;
      RECT 3026.800 4.080 3028.000 1432.080 ;
      RECT 3037.680 4.080 3038.880 1432.080 ;
      RECT 3048.560 4.080 3049.760 1432.080 ;
      RECT 3059.440 4.080 3060.640 1432.080 ;
      RECT 3070.320 4.080 3071.520 1432.080 ;
      RECT 3081.200 4.080 3082.400 1432.080 ;
      RECT 3092.080 4.080 3093.280 1432.080 ;
      RECT 3102.960 4.080 3104.160 1432.080 ;
      RECT 3113.840 4.080 3115.040 1432.080 ;
      RECT 3124.720 4.080 3125.920 1432.080 ;
      RECT 3135.600 4.080 3136.800 1432.080 ;
      RECT 3146.480 4.080 3147.680 1432.080 ;
      RECT 3157.360 4.080 3158.560 1432.080 ;
      RECT 3168.240 4.080 3169.440 1432.080 ;
      RECT 3179.120 4.080 3180.320 1432.080 ;
      RECT 3190.000 4.080 3191.200 1432.080 ;
      RECT 3200.880 4.080 3202.080 1432.080 ;
      RECT 3211.760 4.080 3212.960 1432.080 ;
      RECT 3222.640 4.080 3223.840 1432.080 ;
      RECT 3233.520 4.080 3234.720 1432.080 ;
      RECT 3244.400 4.080 3245.600 1432.080 ;
      RECT 3255.280 4.080 3256.480 1432.080 ;
      RECT 3266.160 4.080 3267.360 1432.080 ;
      RECT 3277.040 4.080 3278.240 1432.080 ;
      RECT 3287.920 4.080 3289.120 1432.080 ;
      RECT 3298.800 4.080 3300.000 1432.080 ;
      RECT 3309.680 4.080 3310.880 1432.080 ;
      RECT 3320.560 4.080 3321.760 1432.080 ;
      RECT 3331.440 4.080 3332.640 1432.080 ;
      RECT 3342.320 4.080 3343.520 1432.080 ;
      RECT 3353.200 4.080 3354.400 1432.080 ;
      RECT 3364.080 4.080 3365.280 1432.080 ;
      RECT 3374.960 4.080 3376.160 1432.080 ;
      RECT 3385.840 4.080 3387.040 1432.080 ;
      RECT 3396.720 4.080 3397.920 1432.080 ;
      RECT 3407.600 4.080 3408.800 1432.080 ;
      RECT 3418.480 4.080 3419.680 1432.080 ;
      RECT 3429.360 4.080 3430.560 1432.080 ;
      RECT 3440.240 4.080 3441.440 1432.080 ;
      RECT 3451.120 4.080 3452.320 1432.080 ;
      RECT 3462.000 4.080 3463.200 1432.080 ;
      RECT 3472.880 4.080 3474.080 1432.080 ;
      RECT 3483.760 4.080 3484.960 1432.080 ;
      RECT 3494.640 4.080 3495.840 1432.080 ;
      RECT 3505.520 4.080 3506.720 1432.080 ;
      RECT 3516.400 4.080 3517.600 1432.080 ;
      RECT 3527.280 4.080 3528.480 1432.080 ;
      RECT 3538.160 4.080 3539.360 1432.080 ;
      RECT 3549.040 4.080 3550.240 1432.080 ;
      RECT 3559.920 4.080 3561.120 1432.080 ;
      RECT 3570.800 4.080 3572.000 1432.080 ;
      RECT 3581.680 4.080 3582.880 1432.080 ;
      RECT 3592.560 4.080 3593.760 1432.080 ;
      RECT 3603.440 4.080 3604.640 1432.080 ;
      RECT 3614.320 4.080 3615.520 1432.080 ;
      RECT 3625.200 4.080 3626.400 1432.080 ;
      RECT 3636.080 4.080 3637.280 1432.080 ;
      RECT 3646.960 4.080 3648.160 1432.080 ;
      RECT 3657.840 4.080 3659.040 1432.080 ;
      RECT 3668.720 4.080 3669.920 1432.080 ;
      RECT 3679.600 4.080 3680.800 1432.080 ;
      RECT 3690.480 4.080 3691.680 1432.080 ;
      RECT 3701.360 4.080 3702.560 1432.080 ;
      RECT 3712.240 4.080 3713.440 1432.080 ;
      RECT 3723.120 4.080 3724.320 1432.080 ;
      RECT 3734.000 4.080 3735.200 1432.080 ;
      RECT 3744.880 4.080 3746.080 1432.080 ;
      RECT 3755.760 4.080 3756.960 1432.080 ;
      RECT 3766.640 4.080 3767.840 1432.080 ;
      RECT 3777.520 4.080 3778.720 1432.080 ;
      RECT 3788.400 4.080 3789.600 1432.080 ;
      RECT 3799.280 4.080 3800.480 1432.080 ;
      RECT 3810.160 4.080 3811.360 1432.080 ;
      RECT 3821.040 4.080 3822.240 1432.080 ;
      RECT 3831.920 4.080 3833.120 1432.080 ;
      RECT 3842.800 4.080 3844.000 1432.080 ;
      RECT 3853.680 4.080 3854.880 1432.080 ;
      RECT 3864.560 4.080 3865.760 1432.080 ;
      RECT 3875.440 4.080 3876.640 1432.080 ;
      RECT 3886.320 4.080 3887.520 1432.080 ;
      RECT 3897.200 4.080 3898.400 1432.080 ;
      RECT 3908.080 4.080 3909.280 1432.080 ;
      RECT 3918.960 4.080 3920.160 1432.080 ;
      RECT 3929.840 4.080 3931.040 1432.080 ;
      RECT 3940.720 4.080 3941.920 1432.080 ;
      RECT 3951.600 4.080 3952.800 1432.080 ;
      RECT 3962.480 4.080 3963.680 1432.080 ;
      RECT 3973.360 4.080 3974.560 1432.080 ;
      RECT 3984.240 4.080 3985.440 1432.080 ;
      RECT 3995.120 4.080 3996.320 1432.080 ;
      RECT 4006.000 4.080 4007.200 1432.080 ;
      RECT 4016.880 4.080 4018.080 1432.080 ;
      RECT 4027.760 4.080 4028.960 1432.080 ;
      RECT 4038.640 4.080 4039.840 1432.080 ;
      RECT 4049.520 4.080 4050.720 1432.080 ;
      RECT 4060.400 4.080 4061.600 1432.080 ;
      RECT 4071.280 4.080 4072.480 1432.080 ;
      RECT 4082.160 4.080 4083.360 1432.080 ;
      RECT 4093.040 4.080 4094.240 1432.080 ;
      RECT 4103.920 4.080 4105.120 1432.080 ;
      RECT 4114.800 4.080 4116.000 1432.080 ;
      RECT 4125.680 4.080 4126.880 1432.080 ;
      RECT 4136.560 4.080 4137.760 1432.080 ;
      RECT 4147.440 4.080 4148.640 1432.080 ;
      RECT 4158.320 4.080 4159.520 1432.080 ;
      RECT 4169.200 4.080 4170.400 1432.080 ;
      RECT 4180.080 4.080 4181.280 1432.080 ;
      RECT 4190.960 4.080 4192.160 1432.080 ;
      RECT 4201.840 4.080 4203.040 1432.080 ;
      RECT 4212.720 4.080 4213.920 1432.080 ;
      RECT 4223.600 4.080 4224.800 1432.080 ;
      RECT 4234.480 4.080 4235.680 1432.080 ;
      RECT 4245.360 4.080 4246.560 1432.080 ;
      RECT 4256.240 4.080 4257.440 1432.080 ;
      RECT 4267.120 4.080 4268.320 1432.080 ;
      RECT 4278.000 4.080 4279.200 1432.080 ;
      RECT 4288.880 4.080 4290.080 1432.080 ;
      RECT 4299.760 4.080 4300.960 1432.080 ;
      RECT 4310.640 4.080 4311.840 1432.080 ;
      RECT 4321.520 4.080 4322.720 1432.080 ;
      RECT 4332.400 4.080 4333.600 1432.080 ;
      RECT 4343.280 4.080 4344.480 1432.080 ;
      RECT 4354.160 4.080 4355.360 1432.080 ;
      RECT 4365.040 4.080 4366.240 1432.080 ;
      RECT 4375.920 4.080 4377.120 1432.080 ;
      RECT 4386.800 4.080 4388.000 1432.080 ;
      RECT 4397.680 4.080 4398.880 1432.080 ;
      RECT 4408.560 4.080 4409.760 1432.080 ;
      RECT 4419.440 4.080 4420.640 1432.080 ;
      RECT 4430.320 4.080 4431.520 1432.080 ;
      RECT 4441.200 4.080 4442.400 1432.080 ;
      RECT 4452.080 4.080 4453.280 1432.080 ;
      RECT 4462.960 4.080 4464.160 1432.080 ;
      RECT 4473.840 4.080 4475.040 1432.080 ;
      RECT 4484.720 4.080 4485.920 1432.080 ;
      RECT 4495.600 4.080 4496.800 1432.080 ;
      RECT 4506.480 4.080 4507.680 1432.080 ;
      RECT 4517.360 4.080 4518.560 1432.080 ;
      RECT 4528.240 4.080 4529.440 1432.080 ;
      RECT 4539.120 4.080 4540.320 1432.080 ;
      RECT 4550.000 4.080 4551.200 1432.080 ;
      RECT 4560.880 4.080 4562.080 1432.080 ;
      RECT 4571.760 4.080 4572.960 1432.080 ;
      RECT 4582.640 4.080 4583.840 1432.080 ;
      RECT 4593.520 4.080 4594.720 1432.080 ;
      RECT 4604.400 4.080 4605.600 1432.080 ;
      RECT 4615.280 4.080 4616.480 1432.080 ;
      RECT 4626.160 4.080 4627.360 1432.080 ;
      RECT 4637.040 4.080 4638.240 1432.080 ;
      RECT 4647.920 4.080 4649.120 1432.080 ;
      RECT 4658.800 4.080 4660.000 1432.080 ;
      RECT 4669.680 4.080 4670.880 1432.080 ;
      RECT 4680.560 4.080 4681.760 1432.080 ;
      RECT 4691.440 4.080 4692.640 1432.080 ;
      RECT 4702.320 4.080 4703.520 1432.080 ;
      RECT 4713.200 4.080 4714.400 1432.080 ;
      RECT 4724.080 4.080 4725.280 1432.080 ;
      RECT 4734.960 4.080 4736.160 1432.080 ;
      RECT 4745.840 4.080 4747.040 1432.080 ;
      RECT 4756.720 4.080 4757.920 1432.080 ;
      RECT 4767.600 4.080 4768.800 1432.080 ;
      RECT 4778.480 4.080 4779.680 1432.080 ;
      RECT 4789.360 4.080 4790.560 1432.080 ;
      RECT 4800.240 4.080 4801.440 1432.080 ;
      RECT 4811.120 4.080 4812.320 1432.080 ;
      RECT 4822.000 4.080 4823.200 1432.080 ;
      RECT 4832.880 4.080 4834.080 1432.080 ;
      RECT 4843.760 4.080 4844.960 1432.080 ;
      RECT 4854.640 4.080 4855.840 1432.080 ;
      RECT 4865.520 4.080 4866.720 1432.080 ;
      RECT 4876.400 4.080 4877.600 1432.080 ;
      RECT 4887.280 4.080 4888.480 1432.080 ;
      RECT 4898.160 4.080 4899.360 1432.080 ;
      RECT 4909.040 4.080 4910.240 1432.080 ;
      RECT 4919.920 4.080 4921.120 1432.080 ;
      RECT 4930.800 4.080 4932.000 1432.080 ;
      RECT 4941.680 4.080 4942.880 1432.080 ;
      RECT 4952.560 4.080 4953.760 1432.080 ;
      RECT 4963.440 4.080 4964.640 1432.080 ;
      RECT 4974.320 4.080 4975.520 1432.080 ;
      RECT 4985.200 4.080 4986.400 1432.080 ;
      RECT 4996.080 4.080 4997.280 1432.080 ;
      RECT 5006.960 4.080 5008.160 1432.080 ;
      RECT 5017.840 4.080 5019.040 1432.080 ;
      RECT 5028.720 4.080 5029.920 1432.080 ;
      RECT 5039.600 4.080 5040.800 1432.080 ;
      RECT 5050.480 4.080 5051.680 1432.080 ;
      RECT 5061.360 4.080 5062.560 1432.080 ;
      RECT 5072.240 4.080 5073.440 1432.080 ;
      RECT 5083.120 4.080 5084.320 1432.080 ;
      RECT 5094.000 4.080 5095.200 1432.080 ;
      RECT 5104.880 4.080 5106.080 1432.080 ;
      RECT 5115.760 4.080 5116.960 1432.080 ;
      RECT 5126.640 4.080 5127.840 1432.080 ;
      RECT 5137.520 4.080 5138.720 1432.080 ;
      RECT 5148.400 4.080 5149.600 1432.080 ;
      RECT 5159.280 4.080 5160.480 1432.080 ;
      RECT 5170.160 4.080 5171.360 1432.080 ;
      RECT 5181.040 4.080 5182.240 1432.080 ;
      RECT 5191.920 4.080 5193.120 1432.080 ;
      RECT 5202.800 4.080 5204.000 1432.080 ;
      RECT 5213.680 4.080 5214.880 1432.080 ;
      RECT 5224.560 4.080 5225.760 1432.080 ;
      RECT 5235.440 4.080 5236.640 1432.080 ;
      RECT 5246.320 4.080 5247.520 1432.080 ;
      RECT 5257.200 4.080 5258.400 1432.080 ;
      RECT 5268.080 4.080 5269.280 1432.080 ;
      RECT 5278.960 4.080 5280.160 1432.080 ;
      RECT 5289.840 4.080 5291.040 1432.080 ;
      RECT 5300.720 4.080 5301.920 1432.080 ;
      RECT 5311.600 4.080 5312.800 1432.080 ;
      RECT 5322.480 4.080 5323.680 1432.080 ;
      RECT 5333.360 4.080 5334.560 1432.080 ;
      RECT 5344.240 4.080 5345.440 1432.080 ;
      RECT 5355.120 4.080 5356.320 1432.080 ;
      RECT 5366.000 4.080 5367.200 1432.080 ;
      RECT 5376.880 4.080 5378.080 1432.080 ;
      RECT 5387.760 4.080 5388.960 1432.080 ;
      RECT 5398.640 4.080 5399.840 1432.080 ;
      RECT 5409.520 4.080 5410.720 1432.080 ;
      RECT 5420.400 4.080 5421.600 1432.080 ;
      RECT 5431.280 4.080 5432.480 1432.080 ;
      RECT 5442.160 4.080 5443.360 1432.080 ;
      RECT 5453.040 4.080 5454.240 1432.080 ;
      RECT 5463.920 4.080 5465.120 1432.080 ;
      RECT 5474.800 4.080 5476.000 1432.080 ;
      RECT 5485.680 4.080 5486.880 1432.080 ;
      RECT 5496.560 4.080 5497.760 1432.080 ;
      RECT 5507.440 4.080 5508.640 1432.080 ;
      RECT 5518.320 4.080 5519.520 1432.080 ;
      RECT 5529.200 4.080 5530.400 1432.080 ;
      RECT 5540.080 4.080 5541.280 1432.080 ;
      RECT 5550.960 4.080 5552.160 1432.080 ;
      RECT 5561.840 4.080 5563.040 1432.080 ;
      RECT 5572.720 4.080 5573.920 1432.080 ;
      RECT 5583.600 4.080 5584.800 1432.080 ;
      RECT 5594.480 4.080 5595.680 1432.080 ;
      RECT 5605.360 4.080 5606.560 1432.080 ;
      RECT 5616.240 4.080 5617.440 1432.080 ;
      RECT 5627.120 4.080 5628.320 1432.080 ;
      RECT 5638.000 4.080 5639.200 1432.080 ;
      RECT 5648.880 4.080 5650.080 1432.080 ;
      RECT 5659.760 4.080 5660.960 1432.080 ;
      RECT 5670.640 4.080 5671.840 1432.080 ;
      RECT 5681.520 4.080 5682.720 1432.080 ;
      RECT 5692.400 4.080 5693.600 1432.080 ;
      RECT 5703.280 4.080 5704.480 1432.080 ;
      RECT 5714.160 4.080 5715.360 1432.080 ;
      RECT 5725.040 4.080 5726.240 1432.080 ;
      RECT 5735.920 4.080 5737.120 1432.080 ;
      RECT 5746.800 4.080 5748.000 1432.080 ;
      RECT 5757.680 4.080 5758.880 1432.080 ;
      RECT 5768.560 4.080 5769.760 1432.080 ;
      RECT 5779.440 4.080 5780.640 1432.080 ;
      RECT 5790.320 4.080 5791.520 1432.080 ;
      RECT 5801.200 4.080 5802.400 1432.080 ;
      RECT 5812.080 4.080 5813.280 1432.080 ;
      RECT 5822.960 4.080 5824.160 1432.080 ;
      RECT 5833.840 4.080 5835.040 1432.080 ;
      RECT 5844.720 4.080 5845.920 1432.080 ;
      RECT 5855.600 4.080 5856.800 1432.080 ;
      RECT 5866.480 4.080 5867.680 1432.080 ;
    END
  END VSS
  PIN VDD
    DIRECTION INOUT ;
    USE POWER ;
    PORT
      LAYER met4 ;
      RECT 2.160 4.080 3.360 1432.080 ;
      RECT 13.040 4.080 14.240 1432.080 ;
      RECT 23.920 4.080 25.120 1432.080 ;
      RECT 34.800 4.080 36.000 1432.080 ;
      RECT 45.680 4.080 46.880 1432.080 ;
      RECT 56.560 4.080 57.760 1432.080 ;
      RECT 67.440 4.080 68.640 1432.080 ;
      RECT 78.320 4.080 79.520 1432.080 ;
      RECT 89.200 4.080 90.400 1432.080 ;
      RECT 100.080 4.080 101.280 1432.080 ;
      RECT 110.960 4.080 112.160 1432.080 ;
      RECT 121.840 4.080 123.040 1432.080 ;
      RECT 132.720 4.080 133.920 1432.080 ;
      RECT 143.600 4.080 144.800 1432.080 ;
      RECT 154.480 4.080 155.680 1432.080 ;
      RECT 165.360 4.080 166.560 1432.080 ;
      RECT 176.240 4.080 177.440 1432.080 ;
      RECT 187.120 4.080 188.320 1432.080 ;
      RECT 198.000 4.080 199.200 1432.080 ;
      RECT 208.880 4.080 210.080 1432.080 ;
      RECT 219.760 4.080 220.960 1432.080 ;
      RECT 230.640 4.080 231.840 1432.080 ;
      RECT 241.520 4.080 242.720 1432.080 ;
      RECT 252.400 4.080 253.600 1432.080 ;
      RECT 263.280 4.080 264.480 1432.080 ;
      RECT 274.160 4.080 275.360 1432.080 ;
      RECT 285.040 4.080 286.240 1432.080 ;
      RECT 295.920 4.080 297.120 1432.080 ;
      RECT 306.800 4.080 308.000 1432.080 ;
      RECT 317.680 4.080 318.880 1432.080 ;
      RECT 328.560 4.080 329.760 1432.080 ;
      RECT 339.440 4.080 340.640 1432.080 ;
      RECT 350.320 4.080 351.520 1432.080 ;
      RECT 361.200 4.080 362.400 1432.080 ;
      RECT 372.080 4.080 373.280 1432.080 ;
      RECT 382.960 4.080 384.160 1432.080 ;
      RECT 393.840 4.080 395.040 1432.080 ;
      RECT 404.720 4.080 405.920 1432.080 ;
      RECT 415.600 4.080 416.800 1432.080 ;
      RECT 426.480 4.080 427.680 1432.080 ;
      RECT 437.360 4.080 438.560 1432.080 ;
      RECT 448.240 4.080 449.440 1432.080 ;
      RECT 459.120 4.080 460.320 1432.080 ;
      RECT 470.000 4.080 471.200 1432.080 ;
      RECT 480.880 4.080 482.080 1432.080 ;
      RECT 491.760 4.080 492.960 1432.080 ;
      RECT 502.640 4.080 503.840 1432.080 ;
      RECT 513.520 4.080 514.720 1432.080 ;
      RECT 524.400 4.080 525.600 1432.080 ;
      RECT 535.280 4.080 536.480 1432.080 ;
      RECT 546.160 4.080 547.360 1432.080 ;
      RECT 557.040 4.080 558.240 1432.080 ;
      RECT 567.920 4.080 569.120 1432.080 ;
      RECT 578.800 4.080 580.000 1432.080 ;
      RECT 589.680 4.080 590.880 1432.080 ;
      RECT 600.560 4.080 601.760 1432.080 ;
      RECT 611.440 4.080 612.640 1432.080 ;
      RECT 622.320 4.080 623.520 1432.080 ;
      RECT 633.200 4.080 634.400 1432.080 ;
      RECT 644.080 4.080 645.280 1432.080 ;
      RECT 654.960 4.080 656.160 1432.080 ;
      RECT 665.840 4.080 667.040 1432.080 ;
      RECT 676.720 4.080 677.920 1432.080 ;
      RECT 687.600 4.080 688.800 1432.080 ;
      RECT 698.480 4.080 699.680 1432.080 ;
      RECT 709.360 4.080 710.560 1432.080 ;
      RECT 720.240 4.080 721.440 1432.080 ;
      RECT 731.120 4.080 732.320 1432.080 ;
      RECT 742.000 4.080 743.200 1432.080 ;
      RECT 752.880 4.080 754.080 1432.080 ;
      RECT 763.760 4.080 764.960 1432.080 ;
      RECT 774.640 4.080 775.840 1432.080 ;
      RECT 785.520 4.080 786.720 1432.080 ;
      RECT 796.400 4.080 797.600 1432.080 ;
      RECT 807.280 4.080 808.480 1432.080 ;
      RECT 818.160 4.080 819.360 1432.080 ;
      RECT 829.040 4.080 830.240 1432.080 ;
      RECT 839.920 4.080 841.120 1432.080 ;
      RECT 850.800 4.080 852.000 1432.080 ;
      RECT 861.680 4.080 862.880 1432.080 ;
      RECT 872.560 4.080 873.760 1432.080 ;
      RECT 883.440 4.080 884.640 1432.080 ;
      RECT 894.320 4.080 895.520 1432.080 ;
      RECT 905.200 4.080 906.400 1432.080 ;
      RECT 916.080 4.080 917.280 1432.080 ;
      RECT 926.960 4.080 928.160 1432.080 ;
      RECT 937.840 4.080 939.040 1432.080 ;
      RECT 948.720 4.080 949.920 1432.080 ;
      RECT 959.600 4.080 960.800 1432.080 ;
      RECT 970.480 4.080 971.680 1432.080 ;
      RECT 981.360 4.080 982.560 1432.080 ;
      RECT 992.240 4.080 993.440 1432.080 ;
      RECT 1003.120 4.080 1004.320 1432.080 ;
      RECT 1014.000 4.080 1015.200 1432.080 ;
      RECT 1024.880 4.080 1026.080 1432.080 ;
      RECT 1035.760 4.080 1036.960 1432.080 ;
      RECT 1046.640 4.080 1047.840 1432.080 ;
      RECT 1057.520 4.080 1058.720 1432.080 ;
      RECT 1068.400 4.080 1069.600 1432.080 ;
      RECT 1079.280 4.080 1080.480 1432.080 ;
      RECT 1090.160 4.080 1091.360 1432.080 ;
      RECT 1101.040 4.080 1102.240 1432.080 ;
      RECT 1111.920 4.080 1113.120 1432.080 ;
      RECT 1122.800 4.080 1124.000 1432.080 ;
      RECT 1133.680 4.080 1134.880 1432.080 ;
      RECT 1144.560 4.080 1145.760 1432.080 ;
      RECT 1155.440 4.080 1156.640 1432.080 ;
      RECT 1166.320 4.080 1167.520 1432.080 ;
      RECT 1177.200 4.080 1178.400 1432.080 ;
      RECT 1188.080 4.080 1189.280 1432.080 ;
      RECT 1198.960 4.080 1200.160 1432.080 ;
      RECT 1209.840 4.080 1211.040 1432.080 ;
      RECT 1220.720 4.080 1221.920 1432.080 ;
      RECT 1231.600 4.080 1232.800 1432.080 ;
      RECT 1242.480 4.080 1243.680 1432.080 ;
      RECT 1253.360 4.080 1254.560 1432.080 ;
      RECT 1264.240 4.080 1265.440 1432.080 ;
      RECT 1275.120 4.080 1276.320 1432.080 ;
      RECT 1286.000 4.080 1287.200 1432.080 ;
      RECT 1296.880 4.080 1298.080 1432.080 ;
      RECT 1307.760 4.080 1308.960 1432.080 ;
      RECT 1318.640 4.080 1319.840 1432.080 ;
      RECT 1329.520 4.080 1330.720 1432.080 ;
      RECT 1340.400 4.080 1341.600 1432.080 ;
      RECT 1351.280 4.080 1352.480 1432.080 ;
      RECT 1362.160 4.080 1363.360 1432.080 ;
      RECT 1373.040 4.080 1374.240 1432.080 ;
      RECT 1383.920 4.080 1385.120 1432.080 ;
      RECT 1394.800 4.080 1396.000 1432.080 ;
      RECT 1405.680 4.080 1406.880 1432.080 ;
      RECT 1416.560 4.080 1417.760 1432.080 ;
      RECT 1427.440 4.080 1428.640 1432.080 ;
      RECT 1438.320 4.080 1439.520 1432.080 ;
      RECT 1449.200 4.080 1450.400 1432.080 ;
      RECT 1460.080 4.080 1461.280 1432.080 ;
      RECT 1470.960 4.080 1472.160 1432.080 ;
      RECT 1481.840 4.080 1483.040 1432.080 ;
      RECT 1492.720 4.080 1493.920 1432.080 ;
      RECT 1503.600 4.080 1504.800 1432.080 ;
      RECT 1514.480 4.080 1515.680 1432.080 ;
      RECT 1525.360 4.080 1526.560 1432.080 ;
      RECT 1536.240 4.080 1537.440 1432.080 ;
      RECT 1547.120 4.080 1548.320 1432.080 ;
      RECT 1558.000 4.080 1559.200 1432.080 ;
      RECT 1568.880 4.080 1570.080 1432.080 ;
      RECT 1579.760 4.080 1580.960 1432.080 ;
      RECT 1590.640 4.080 1591.840 1432.080 ;
      RECT 1601.520 4.080 1602.720 1432.080 ;
      RECT 1612.400 4.080 1613.600 1432.080 ;
      RECT 1623.280 4.080 1624.480 1432.080 ;
      RECT 1634.160 4.080 1635.360 1432.080 ;
      RECT 1645.040 4.080 1646.240 1432.080 ;
      RECT 1655.920 4.080 1657.120 1432.080 ;
      RECT 1666.800 4.080 1668.000 1432.080 ;
      RECT 1677.680 4.080 1678.880 1432.080 ;
      RECT 1688.560 4.080 1689.760 1432.080 ;
      RECT 1699.440 4.080 1700.640 1432.080 ;
      RECT 1710.320 4.080 1711.520 1432.080 ;
      RECT 1721.200 4.080 1722.400 1432.080 ;
      RECT 1732.080 4.080 1733.280 1432.080 ;
      RECT 1742.960 4.080 1744.160 1432.080 ;
      RECT 1753.840 4.080 1755.040 1432.080 ;
      RECT 1764.720 4.080 1765.920 1432.080 ;
      RECT 1775.600 4.080 1776.800 1432.080 ;
      RECT 1786.480 4.080 1787.680 1432.080 ;
      RECT 1797.360 4.080 1798.560 1432.080 ;
      RECT 1808.240 4.080 1809.440 1432.080 ;
      RECT 1819.120 4.080 1820.320 1432.080 ;
      RECT 1830.000 4.080 1831.200 1432.080 ;
      RECT 1840.880 4.080 1842.080 1432.080 ;
      RECT 1851.760 4.080 1852.960 1432.080 ;
      RECT 1862.640 4.080 1863.840 1432.080 ;
      RECT 1873.520 4.080 1874.720 1432.080 ;
      RECT 1884.400 4.080 1885.600 1432.080 ;
      RECT 1895.280 4.080 1896.480 1432.080 ;
      RECT 1906.160 4.080 1907.360 1432.080 ;
      RECT 1917.040 4.080 1918.240 1432.080 ;
      RECT 1927.920 4.080 1929.120 1432.080 ;
      RECT 1938.800 4.080 1940.000 1432.080 ;
      RECT 1949.680 4.080 1950.880 1432.080 ;
      RECT 1960.560 4.080 1961.760 1432.080 ;
      RECT 1971.440 4.080 1972.640 1432.080 ;
      RECT 1982.320 4.080 1983.520 1432.080 ;
      RECT 1993.200 4.080 1994.400 1432.080 ;
      RECT 2004.080 4.080 2005.280 1432.080 ;
      RECT 2014.960 4.080 2016.160 1432.080 ;
      RECT 2025.840 4.080 2027.040 1432.080 ;
      RECT 2036.720 4.080 2037.920 1432.080 ;
      RECT 2047.600 4.080 2048.800 1432.080 ;
      RECT 2058.480 4.080 2059.680 1432.080 ;
      RECT 2069.360 4.080 2070.560 1432.080 ;
      RECT 2080.240 4.080 2081.440 1432.080 ;
      RECT 2091.120 4.080 2092.320 1432.080 ;
      RECT 2102.000 4.080 2103.200 1432.080 ;
      RECT 2112.880 4.080 2114.080 1432.080 ;
      RECT 2123.760 4.080 2124.960 1432.080 ;
      RECT 2134.640 4.080 2135.840 1432.080 ;
      RECT 2145.520 4.080 2146.720 1432.080 ;
      RECT 2156.400 4.080 2157.600 1432.080 ;
      RECT 2167.280 4.080 2168.480 1432.080 ;
      RECT 2178.160 4.080 2179.360 1432.080 ;
      RECT 2189.040 4.080 2190.240 1432.080 ;
      RECT 2199.920 4.080 2201.120 1432.080 ;
      RECT 2210.800 4.080 2212.000 1432.080 ;
      RECT 2221.680 4.080 2222.880 1432.080 ;
      RECT 2232.560 4.080 2233.760 1432.080 ;
      RECT 2243.440 4.080 2244.640 1432.080 ;
      RECT 2254.320 4.080 2255.520 1432.080 ;
      RECT 2265.200 4.080 2266.400 1432.080 ;
      RECT 2276.080 4.080 2277.280 1432.080 ;
      RECT 2286.960 4.080 2288.160 1432.080 ;
      RECT 2297.840 4.080 2299.040 1432.080 ;
      RECT 2308.720 4.080 2309.920 1432.080 ;
      RECT 2319.600 4.080 2320.800 1432.080 ;
      RECT 2330.480 4.080 2331.680 1432.080 ;
      RECT 2341.360 4.080 2342.560 1432.080 ;
      RECT 2352.240 4.080 2353.440 1432.080 ;
      RECT 2363.120 4.080 2364.320 1432.080 ;
      RECT 2374.000 4.080 2375.200 1432.080 ;
      RECT 2384.880 4.080 2386.080 1432.080 ;
      RECT 2395.760 4.080 2396.960 1432.080 ;
      RECT 2406.640 4.080 2407.840 1432.080 ;
      RECT 2417.520 4.080 2418.720 1432.080 ;
      RECT 2428.400 4.080 2429.600 1432.080 ;
      RECT 2439.280 4.080 2440.480 1432.080 ;
      RECT 2450.160 4.080 2451.360 1432.080 ;
      RECT 2461.040 4.080 2462.240 1432.080 ;
      RECT 2471.920 4.080 2473.120 1432.080 ;
      RECT 2482.800 4.080 2484.000 1432.080 ;
      RECT 2493.680 4.080 2494.880 1432.080 ;
      RECT 2504.560 4.080 2505.760 1432.080 ;
      RECT 2515.440 4.080 2516.640 1432.080 ;
      RECT 2526.320 4.080 2527.520 1432.080 ;
      RECT 2537.200 4.080 2538.400 1432.080 ;
      RECT 2548.080 4.080 2549.280 1432.080 ;
      RECT 2558.960 4.080 2560.160 1432.080 ;
      RECT 2569.840 4.080 2571.040 1432.080 ;
      RECT 2580.720 4.080 2581.920 1432.080 ;
      RECT 2591.600 4.080 2592.800 1432.080 ;
      RECT 2602.480 4.080 2603.680 1432.080 ;
      RECT 2613.360 4.080 2614.560 1432.080 ;
      RECT 2624.240 4.080 2625.440 1432.080 ;
      RECT 2635.120 4.080 2636.320 1432.080 ;
      RECT 2646.000 4.080 2647.200 1432.080 ;
      RECT 2656.880 4.080 2658.080 1432.080 ;
      RECT 2667.760 4.080 2668.960 1432.080 ;
      RECT 2678.640 4.080 2679.840 1432.080 ;
      RECT 2689.520 4.080 2690.720 1432.080 ;
      RECT 2700.400 4.080 2701.600 1432.080 ;
      RECT 2711.280 4.080 2712.480 1432.080 ;
      RECT 2722.160 4.080 2723.360 1432.080 ;
      RECT 2733.040 4.080 2734.240 1432.080 ;
      RECT 2743.920 4.080 2745.120 1432.080 ;
      RECT 2754.800 4.080 2756.000 1432.080 ;
      RECT 2765.680 4.080 2766.880 1432.080 ;
      RECT 2776.560 4.080 2777.760 1432.080 ;
      RECT 2787.440 4.080 2788.640 1432.080 ;
      RECT 2798.320 4.080 2799.520 1432.080 ;
      RECT 2809.200 4.080 2810.400 1432.080 ;
      RECT 2820.080 4.080 2821.280 1432.080 ;
      RECT 2830.960 4.080 2832.160 1432.080 ;
      RECT 2841.840 4.080 2843.040 1432.080 ;
      RECT 2852.720 4.080 2853.920 1432.080 ;
      RECT 2863.600 4.080 2864.800 1432.080 ;
      RECT 2874.480 4.080 2875.680 1432.080 ;
      RECT 2885.360 4.080 2886.560 1432.080 ;
      RECT 2896.240 4.080 2897.440 1432.080 ;
      RECT 2907.120 4.080 2908.320 1432.080 ;
      RECT 2918.000 4.080 2919.200 1432.080 ;
      RECT 2928.880 4.080 2930.080 1432.080 ;
      RECT 2939.760 4.080 2940.960 1432.080 ;
      RECT 2950.640 4.080 2951.840 1432.080 ;
      RECT 2961.520 4.080 2962.720 1432.080 ;
      RECT 2972.400 4.080 2973.600 1432.080 ;
      RECT 2983.280 4.080 2984.480 1432.080 ;
      RECT 2994.160 4.080 2995.360 1432.080 ;
      RECT 3005.040 4.080 3006.240 1432.080 ;
      RECT 3015.920 4.080 3017.120 1432.080 ;
      RECT 3026.800 4.080 3028.000 1432.080 ;
      RECT 3037.680 4.080 3038.880 1432.080 ;
      RECT 3048.560 4.080 3049.760 1432.080 ;
      RECT 3059.440 4.080 3060.640 1432.080 ;
      RECT 3070.320 4.080 3071.520 1432.080 ;
      RECT 3081.200 4.080 3082.400 1432.080 ;
      RECT 3092.080 4.080 3093.280 1432.080 ;
      RECT 3102.960 4.080 3104.160 1432.080 ;
      RECT 3113.840 4.080 3115.040 1432.080 ;
      RECT 3124.720 4.080 3125.920 1432.080 ;
      RECT 3135.600 4.080 3136.800 1432.080 ;
      RECT 3146.480 4.080 3147.680 1432.080 ;
      RECT 3157.360 4.080 3158.560 1432.080 ;
      RECT 3168.240 4.080 3169.440 1432.080 ;
      RECT 3179.120 4.080 3180.320 1432.080 ;
      RECT 3190.000 4.080 3191.200 1432.080 ;
      RECT 3200.880 4.080 3202.080 1432.080 ;
      RECT 3211.760 4.080 3212.960 1432.080 ;
      RECT 3222.640 4.080 3223.840 1432.080 ;
      RECT 3233.520 4.080 3234.720 1432.080 ;
      RECT 3244.400 4.080 3245.600 1432.080 ;
      RECT 3255.280 4.080 3256.480 1432.080 ;
      RECT 3266.160 4.080 3267.360 1432.080 ;
      RECT 3277.040 4.080 3278.240 1432.080 ;
      RECT 3287.920 4.080 3289.120 1432.080 ;
      RECT 3298.800 4.080 3300.000 1432.080 ;
      RECT 3309.680 4.080 3310.880 1432.080 ;
      RECT 3320.560 4.080 3321.760 1432.080 ;
      RECT 3331.440 4.080 3332.640 1432.080 ;
      RECT 3342.320 4.080 3343.520 1432.080 ;
      RECT 3353.200 4.080 3354.400 1432.080 ;
      RECT 3364.080 4.080 3365.280 1432.080 ;
      RECT 3374.960 4.080 3376.160 1432.080 ;
      RECT 3385.840 4.080 3387.040 1432.080 ;
      RECT 3396.720 4.080 3397.920 1432.080 ;
      RECT 3407.600 4.080 3408.800 1432.080 ;
      RECT 3418.480 4.080 3419.680 1432.080 ;
      RECT 3429.360 4.080 3430.560 1432.080 ;
      RECT 3440.240 4.080 3441.440 1432.080 ;
      RECT 3451.120 4.080 3452.320 1432.080 ;
      RECT 3462.000 4.080 3463.200 1432.080 ;
      RECT 3472.880 4.080 3474.080 1432.080 ;
      RECT 3483.760 4.080 3484.960 1432.080 ;
      RECT 3494.640 4.080 3495.840 1432.080 ;
      RECT 3505.520 4.080 3506.720 1432.080 ;
      RECT 3516.400 4.080 3517.600 1432.080 ;
      RECT 3527.280 4.080 3528.480 1432.080 ;
      RECT 3538.160 4.080 3539.360 1432.080 ;
      RECT 3549.040 4.080 3550.240 1432.080 ;
      RECT 3559.920 4.080 3561.120 1432.080 ;
      RECT 3570.800 4.080 3572.000 1432.080 ;
      RECT 3581.680 4.080 3582.880 1432.080 ;
      RECT 3592.560 4.080 3593.760 1432.080 ;
      RECT 3603.440 4.080 3604.640 1432.080 ;
      RECT 3614.320 4.080 3615.520 1432.080 ;
      RECT 3625.200 4.080 3626.400 1432.080 ;
      RECT 3636.080 4.080 3637.280 1432.080 ;
      RECT 3646.960 4.080 3648.160 1432.080 ;
      RECT 3657.840 4.080 3659.040 1432.080 ;
      RECT 3668.720 4.080 3669.920 1432.080 ;
      RECT 3679.600 4.080 3680.800 1432.080 ;
      RECT 3690.480 4.080 3691.680 1432.080 ;
      RECT 3701.360 4.080 3702.560 1432.080 ;
      RECT 3712.240 4.080 3713.440 1432.080 ;
      RECT 3723.120 4.080 3724.320 1432.080 ;
      RECT 3734.000 4.080 3735.200 1432.080 ;
      RECT 3744.880 4.080 3746.080 1432.080 ;
      RECT 3755.760 4.080 3756.960 1432.080 ;
      RECT 3766.640 4.080 3767.840 1432.080 ;
      RECT 3777.520 4.080 3778.720 1432.080 ;
      RECT 3788.400 4.080 3789.600 1432.080 ;
      RECT 3799.280 4.080 3800.480 1432.080 ;
      RECT 3810.160 4.080 3811.360 1432.080 ;
      RECT 3821.040 4.080 3822.240 1432.080 ;
      RECT 3831.920 4.080 3833.120 1432.080 ;
      RECT 3842.800 4.080 3844.000 1432.080 ;
      RECT 3853.680 4.080 3854.880 1432.080 ;
      RECT 3864.560 4.080 3865.760 1432.080 ;
      RECT 3875.440 4.080 3876.640 1432.080 ;
      RECT 3886.320 4.080 3887.520 1432.080 ;
      RECT 3897.200 4.080 3898.400 1432.080 ;
      RECT 3908.080 4.080 3909.280 1432.080 ;
      RECT 3918.960 4.080 3920.160 1432.080 ;
      RECT 3929.840 4.080 3931.040 1432.080 ;
      RECT 3940.720 4.080 3941.920 1432.080 ;
      RECT 3951.600 4.080 3952.800 1432.080 ;
      RECT 3962.480 4.080 3963.680 1432.080 ;
      RECT 3973.360 4.080 3974.560 1432.080 ;
      RECT 3984.240 4.080 3985.440 1432.080 ;
      RECT 3995.120 4.080 3996.320 1432.080 ;
      RECT 4006.000 4.080 4007.200 1432.080 ;
      RECT 4016.880 4.080 4018.080 1432.080 ;
      RECT 4027.760 4.080 4028.960 1432.080 ;
      RECT 4038.640 4.080 4039.840 1432.080 ;
      RECT 4049.520 4.080 4050.720 1432.080 ;
      RECT 4060.400 4.080 4061.600 1432.080 ;
      RECT 4071.280 4.080 4072.480 1432.080 ;
      RECT 4082.160 4.080 4083.360 1432.080 ;
      RECT 4093.040 4.080 4094.240 1432.080 ;
      RECT 4103.920 4.080 4105.120 1432.080 ;
      RECT 4114.800 4.080 4116.000 1432.080 ;
      RECT 4125.680 4.080 4126.880 1432.080 ;
      RECT 4136.560 4.080 4137.760 1432.080 ;
      RECT 4147.440 4.080 4148.640 1432.080 ;
      RECT 4158.320 4.080 4159.520 1432.080 ;
      RECT 4169.200 4.080 4170.400 1432.080 ;
      RECT 4180.080 4.080 4181.280 1432.080 ;
      RECT 4190.960 4.080 4192.160 1432.080 ;
      RECT 4201.840 4.080 4203.040 1432.080 ;
      RECT 4212.720 4.080 4213.920 1432.080 ;
      RECT 4223.600 4.080 4224.800 1432.080 ;
      RECT 4234.480 4.080 4235.680 1432.080 ;
      RECT 4245.360 4.080 4246.560 1432.080 ;
      RECT 4256.240 4.080 4257.440 1432.080 ;
      RECT 4267.120 4.080 4268.320 1432.080 ;
      RECT 4278.000 4.080 4279.200 1432.080 ;
      RECT 4288.880 4.080 4290.080 1432.080 ;
      RECT 4299.760 4.080 4300.960 1432.080 ;
      RECT 4310.640 4.080 4311.840 1432.080 ;
      RECT 4321.520 4.080 4322.720 1432.080 ;
      RECT 4332.400 4.080 4333.600 1432.080 ;
      RECT 4343.280 4.080 4344.480 1432.080 ;
      RECT 4354.160 4.080 4355.360 1432.080 ;
      RECT 4365.040 4.080 4366.240 1432.080 ;
      RECT 4375.920 4.080 4377.120 1432.080 ;
      RECT 4386.800 4.080 4388.000 1432.080 ;
      RECT 4397.680 4.080 4398.880 1432.080 ;
      RECT 4408.560 4.080 4409.760 1432.080 ;
      RECT 4419.440 4.080 4420.640 1432.080 ;
      RECT 4430.320 4.080 4431.520 1432.080 ;
      RECT 4441.200 4.080 4442.400 1432.080 ;
      RECT 4452.080 4.080 4453.280 1432.080 ;
      RECT 4462.960 4.080 4464.160 1432.080 ;
      RECT 4473.840 4.080 4475.040 1432.080 ;
      RECT 4484.720 4.080 4485.920 1432.080 ;
      RECT 4495.600 4.080 4496.800 1432.080 ;
      RECT 4506.480 4.080 4507.680 1432.080 ;
      RECT 4517.360 4.080 4518.560 1432.080 ;
      RECT 4528.240 4.080 4529.440 1432.080 ;
      RECT 4539.120 4.080 4540.320 1432.080 ;
      RECT 4550.000 4.080 4551.200 1432.080 ;
      RECT 4560.880 4.080 4562.080 1432.080 ;
      RECT 4571.760 4.080 4572.960 1432.080 ;
      RECT 4582.640 4.080 4583.840 1432.080 ;
      RECT 4593.520 4.080 4594.720 1432.080 ;
      RECT 4604.400 4.080 4605.600 1432.080 ;
      RECT 4615.280 4.080 4616.480 1432.080 ;
      RECT 4626.160 4.080 4627.360 1432.080 ;
      RECT 4637.040 4.080 4638.240 1432.080 ;
      RECT 4647.920 4.080 4649.120 1432.080 ;
      RECT 4658.800 4.080 4660.000 1432.080 ;
      RECT 4669.680 4.080 4670.880 1432.080 ;
      RECT 4680.560 4.080 4681.760 1432.080 ;
      RECT 4691.440 4.080 4692.640 1432.080 ;
      RECT 4702.320 4.080 4703.520 1432.080 ;
      RECT 4713.200 4.080 4714.400 1432.080 ;
      RECT 4724.080 4.080 4725.280 1432.080 ;
      RECT 4734.960 4.080 4736.160 1432.080 ;
      RECT 4745.840 4.080 4747.040 1432.080 ;
      RECT 4756.720 4.080 4757.920 1432.080 ;
      RECT 4767.600 4.080 4768.800 1432.080 ;
      RECT 4778.480 4.080 4779.680 1432.080 ;
      RECT 4789.360 4.080 4790.560 1432.080 ;
      RECT 4800.240 4.080 4801.440 1432.080 ;
      RECT 4811.120 4.080 4812.320 1432.080 ;
      RECT 4822.000 4.080 4823.200 1432.080 ;
      RECT 4832.880 4.080 4834.080 1432.080 ;
      RECT 4843.760 4.080 4844.960 1432.080 ;
      RECT 4854.640 4.080 4855.840 1432.080 ;
      RECT 4865.520 4.080 4866.720 1432.080 ;
      RECT 4876.400 4.080 4877.600 1432.080 ;
      RECT 4887.280 4.080 4888.480 1432.080 ;
      RECT 4898.160 4.080 4899.360 1432.080 ;
      RECT 4909.040 4.080 4910.240 1432.080 ;
      RECT 4919.920 4.080 4921.120 1432.080 ;
      RECT 4930.800 4.080 4932.000 1432.080 ;
      RECT 4941.680 4.080 4942.880 1432.080 ;
      RECT 4952.560 4.080 4953.760 1432.080 ;
      RECT 4963.440 4.080 4964.640 1432.080 ;
      RECT 4974.320 4.080 4975.520 1432.080 ;
      RECT 4985.200 4.080 4986.400 1432.080 ;
      RECT 4996.080 4.080 4997.280 1432.080 ;
      RECT 5006.960 4.080 5008.160 1432.080 ;
      RECT 5017.840 4.080 5019.040 1432.080 ;
      RECT 5028.720 4.080 5029.920 1432.080 ;
      RECT 5039.600 4.080 5040.800 1432.080 ;
      RECT 5050.480 4.080 5051.680 1432.080 ;
      RECT 5061.360 4.080 5062.560 1432.080 ;
      RECT 5072.240 4.080 5073.440 1432.080 ;
      RECT 5083.120 4.080 5084.320 1432.080 ;
      RECT 5094.000 4.080 5095.200 1432.080 ;
      RECT 5104.880 4.080 5106.080 1432.080 ;
      RECT 5115.760 4.080 5116.960 1432.080 ;
      RECT 5126.640 4.080 5127.840 1432.080 ;
      RECT 5137.520 4.080 5138.720 1432.080 ;
      RECT 5148.400 4.080 5149.600 1432.080 ;
      RECT 5159.280 4.080 5160.480 1432.080 ;
      RECT 5170.160 4.080 5171.360 1432.080 ;
      RECT 5181.040 4.080 5182.240 1432.080 ;
      RECT 5191.920 4.080 5193.120 1432.080 ;
      RECT 5202.800 4.080 5204.000 1432.080 ;
      RECT 5213.680 4.080 5214.880 1432.080 ;
      RECT 5224.560 4.080 5225.760 1432.080 ;
      RECT 5235.440 4.080 5236.640 1432.080 ;
      RECT 5246.320 4.080 5247.520 1432.080 ;
      RECT 5257.200 4.080 5258.400 1432.080 ;
      RECT 5268.080 4.080 5269.280 1432.080 ;
      RECT 5278.960 4.080 5280.160 1432.080 ;
      RECT 5289.840 4.080 5291.040 1432.080 ;
      RECT 5300.720 4.080 5301.920 1432.080 ;
      RECT 5311.600 4.080 5312.800 1432.080 ;
      RECT 5322.480 4.080 5323.680 1432.080 ;
      RECT 5333.360 4.080 5334.560 1432.080 ;
      RECT 5344.240 4.080 5345.440 1432.080 ;
      RECT 5355.120 4.080 5356.320 1432.080 ;
      RECT 5366.000 4.080 5367.200 1432.080 ;
      RECT 5376.880 4.080 5378.080 1432.080 ;
      RECT 5387.760 4.080 5388.960 1432.080 ;
      RECT 5398.640 4.080 5399.840 1432.080 ;
      RECT 5409.520 4.080 5410.720 1432.080 ;
      RECT 5420.400 4.080 5421.600 1432.080 ;
      RECT 5431.280 4.080 5432.480 1432.080 ;
      RECT 5442.160 4.080 5443.360 1432.080 ;
      RECT 5453.040 4.080 5454.240 1432.080 ;
      RECT 5463.920 4.080 5465.120 1432.080 ;
      RECT 5474.800 4.080 5476.000 1432.080 ;
      RECT 5485.680 4.080 5486.880 1432.080 ;
      RECT 5496.560 4.080 5497.760 1432.080 ;
      RECT 5507.440 4.080 5508.640 1432.080 ;
      RECT 5518.320 4.080 5519.520 1432.080 ;
      RECT 5529.200 4.080 5530.400 1432.080 ;
      RECT 5540.080 4.080 5541.280 1432.080 ;
      RECT 5550.960 4.080 5552.160 1432.080 ;
      RECT 5561.840 4.080 5563.040 1432.080 ;
      RECT 5572.720 4.080 5573.920 1432.080 ;
      RECT 5583.600 4.080 5584.800 1432.080 ;
      RECT 5594.480 4.080 5595.680 1432.080 ;
      RECT 5605.360 4.080 5606.560 1432.080 ;
      RECT 5616.240 4.080 5617.440 1432.080 ;
      RECT 5627.120 4.080 5628.320 1432.080 ;
      RECT 5638.000 4.080 5639.200 1432.080 ;
      RECT 5648.880 4.080 5650.080 1432.080 ;
      RECT 5659.760 4.080 5660.960 1432.080 ;
      RECT 5670.640 4.080 5671.840 1432.080 ;
      RECT 5681.520 4.080 5682.720 1432.080 ;
      RECT 5692.400 4.080 5693.600 1432.080 ;
      RECT 5703.280 4.080 5704.480 1432.080 ;
      RECT 5714.160 4.080 5715.360 1432.080 ;
      RECT 5725.040 4.080 5726.240 1432.080 ;
      RECT 5735.920 4.080 5737.120 1432.080 ;
      RECT 5746.800 4.080 5748.000 1432.080 ;
      RECT 5757.680 4.080 5758.880 1432.080 ;
      RECT 5768.560 4.080 5769.760 1432.080 ;
      RECT 5779.440 4.080 5780.640 1432.080 ;
      RECT 5790.320 4.080 5791.520 1432.080 ;
      RECT 5801.200 4.080 5802.400 1432.080 ;
      RECT 5812.080 4.080 5813.280 1432.080 ;
      RECT 5822.960 4.080 5824.160 1432.080 ;
      RECT 5833.840 4.080 5835.040 1432.080 ;
      RECT 5844.720 4.080 5845.920 1432.080 ;
      RECT 5855.600 4.080 5856.800 1432.080 ;
      RECT 5866.480 4.080 5867.680 1432.080 ;
    END
  END VDD
  OBS
    LAYER met1 ;
    RECT 0 0 5871.900 1436.160 ;
    LAYER met2 ;
    RECT 0 0 5871.900 1436.160 ;
    LAYER met3 ;
    RECT 0 0 5871.900 1436.160 ;
    LAYER met4 ;
    RECT 0 0 5871.900 1436.160 ;
  END
END fakeram_512x2048_1r1w

END LIBRARY
